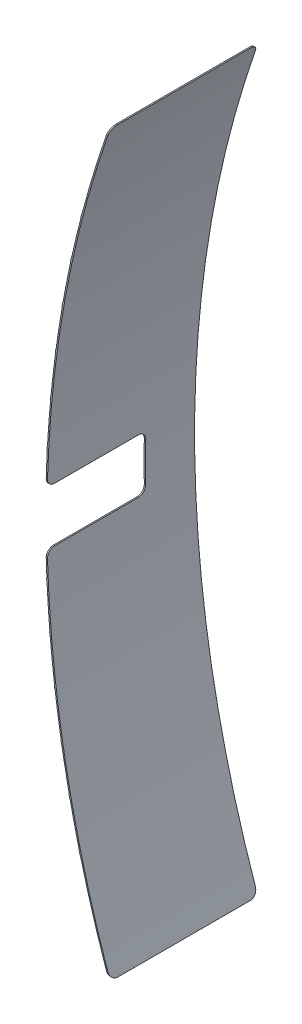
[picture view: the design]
ISO-10303-21;
HEADER;
FILE_DESCRIPTION(('STEP AP214'),'2;1');
FILE_NAME('part.step','',(''),(''),'','','');
FILE_SCHEMA(('AUTOMOTIVE_DESIGN { 1 0 10303 214 1 1 1 1 }'));
ENDSEC;
DATA;
#1=APPLICATION_CONTEXT('core data for automotive mechanical design processes');
#2=APPLICATION_PROTOCOL_DEFINITION('international standard','automotive_design',2000,#1);
#3=PRODUCT_CONTEXT('',#1,'mechanical');
#4=PRODUCT('Part','Part','',(#3));
#5=PRODUCT_RELATED_PRODUCT_CATEGORY('part','',(#4));
#6=PRODUCT_DEFINITION_FORMATION('','',#4);
#7=PRODUCT_DEFINITION_CONTEXT('part definition',#1,'design');
#8=PRODUCT_DEFINITION('design','',#6,#7);
#9=PRODUCT_DEFINITION_SHAPE('','',#8);
#10=(LENGTH_UNIT() NAMED_UNIT(*) SI_UNIT(.MILLI.,.METRE.));
#11=(NAMED_UNIT(*) PLANE_ANGLE_UNIT() SI_UNIT($,.RADIAN.));
#12=(NAMED_UNIT(*) SI_UNIT($,.STERADIAN.) SOLID_ANGLE_UNIT());
#13=UNCERTAINTY_MEASURE_WITH_UNIT(LENGTH_MEASURE(1.E-05),#10,'distance_accuracy_value','');
#14=(GEOMETRIC_REPRESENTATION_CONTEXT(3) GLOBAL_UNCERTAINTY_ASSIGNED_CONTEXT((#13)) GLOBAL_UNIT_ASSIGNED_CONTEXT((#10,
#11,#12)) REPRESENTATION_CONTEXT('',''));
#15=CARTESIAN_POINT('',(0.,0.,0.));
#16=DIRECTION('',(0.,0.,1.));
#17=DIRECTION('',(1.,0.,0.));
#18=AXIS2_PLACEMENT_3D('',#15,#16,#17);
#19=CARTESIAN_POINT('',(0.,0.,6.));
#20=DIRECTION('',(0.,0.,-1.));
#21=DIRECTION('',(-1.,0.,0.));
#22=AXIS2_PLACEMENT_3D('',#19,#20,#21);
#23=CYLINDRICAL_SURFACE('',#22,45.05);
#24=DIRECTION('',(0.,0.,1.));
#25=VECTOR('',#24,1.);
#26=CARTESIAN_POINT('',(-42.6888704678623,14.3931524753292,3.45));
#27=LINE('',#26,#25);
#28=CARTESIAN_POINT('',(-42.6888704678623,14.3931524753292,3.45));
#29=VERTEX_POINT('',#28);
#30=CARTESIAN_POINT('',(-42.6888704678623,14.3931524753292,3.65));
#31=VERTEX_POINT('',#30);
#32=EDGE_CURVE('E1607',#29,#31,#27,.T.);
#33=ORIENTED_EDGE('',*,*,#32,.T.);
#34=CARTESIAN_POINT('',(0.,0.,3.65));
#35=DIRECTION('',(0.,0.,-1.));
#36=DIRECTION('',(-0.947588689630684,0.319492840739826,0.));
#37=AXIS2_PLACEMENT_3D('',#34,#35,#36);
#38=CIRCLE('',#37,45.05);
#39=CARTESIAN_POINT('',(-43.0423392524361,13.2988545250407,3.65));
#40=VERTEX_POINT('',#39);
#41=EDGE_CURVE('E2961',#40,#31,#38,.T.);
#42=ORIENTED_EDGE('',*,*,#41,.F.);
#43=DIRECTION('',(0.,0.,1.));
#44=VECTOR('',#43,1.);
#45=CARTESIAN_POINT('',(-43.0423392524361,13.2988545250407,3.65));
#46=LINE('',#45,#44);
#47=CARTESIAN_POINT('',(-43.0423392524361,13.2988545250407,4.8));
#48=VERTEX_POINT('',#47);
#49=EDGE_CURVE('E3004',#40,#48,#46,.T.);
#50=ORIENTED_EDGE('',*,*,#49,.T.);
#51=CARTESIAN_POINT('',(0.,0.,4.8));
#52=DIRECTION('',(0.,0.,-1.));
#53=DIRECTION('',(-0.955434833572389,0.295202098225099,0.));
#54=AXIS2_PLACEMENT_3D('',#51,#52,#53);
#55=CIRCLE('',#54,45.05);
#56=CARTESIAN_POINT('',(-43.1009553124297,13.1076371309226,4.8));
#57=VERTEX_POINT('',#56);
#58=EDGE_CURVE('E2965',#57,#48,#55,.T.);
#59=ORIENTED_EDGE('',*,*,#58,.F.);
#60=DIRECTION('',(0.,0.,-1.));
#61=VECTOR('',#60,1.);
#62=CARTESIAN_POINT('',(-43.1009553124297,13.1076371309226,4.8));
#63=LINE('',#62,#61);
#64=CARTESIAN_POINT('',(-43.1009553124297,13.1076371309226,3.65));
#65=VERTEX_POINT('',#64);
#66=EDGE_CURVE('E2999',#57,#65,#63,.T.);
#67=ORIENTED_EDGE('',*,*,#66,.T.);
#68=CARTESIAN_POINT('',(0.,0.,3.65));
#69=DIRECTION('',(0.,0.,-1.));
#70=DIRECTION('',(-0.956735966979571,0.290957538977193,0.));
#71=AXIS2_PLACEMENT_3D('',#68,#69,#70);
#72=CIRCLE('',#71,45.05);
#73=CARTESIAN_POINT('',(-43.4214778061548,12.003239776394,3.65));
#74=VERTEX_POINT('',#73);
#75=EDGE_CURVE('E2994',#74,#65,#72,.T.);
#76=ORIENTED_EDGE('',*,*,#75,.F.);
#77=DIRECTION('',(0.,0.,-1.));
#78=VECTOR('',#77,1.);
#79=CARTESIAN_POINT('',(-43.4214778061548,12.003239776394,3.65));
#80=LINE('',#79,#78);
#81=CARTESIAN_POINT('',(-43.4214778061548,12.003239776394,3.45));
#82=VERTEX_POINT('',#81);
#83=EDGE_CURVE('E3003',#74,#82,#80,.T.);
#84=ORIENTED_EDGE('',*,*,#83,.T.);
#85=CARTESIAN_POINT('',(0.,0.,3.45));
#86=DIRECTION('',(0.,0.,-1.));
#87=DIRECTION('',(-0.956735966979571,0.290957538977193,0.));
#88=AXIS2_PLACEMENT_3D('',#85,#86,#87);
#89=CIRCLE('',#88,45.05);
#90=CARTESIAN_POINT('',(-43.1009553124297,13.1076371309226,3.45));
#91=VERTEX_POINT('',#90);
#92=EDGE_CURVE('E3011',#82,#91,#89,.T.);
#93=ORIENTED_EDGE('',*,*,#92,.T.);
#94=DIRECTION('',(0.,0.,-1.));
#95=VECTOR('',#94,1.);
#96=CARTESIAN_POINT('',(-43.1009553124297,13.1076371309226,3.45));
#97=LINE('',#96,#95);
#98=CARTESIAN_POINT('',(-43.1009553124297,13.1076371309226,2.3));
#99=VERTEX_POINT('',#98);
#100=EDGE_CURVE('E3015',#91,#99,#97,.T.);
#101=ORIENTED_EDGE('',*,*,#100,.T.);
#102=CARTESIAN_POINT('',(0.,0.,2.3));
#103=DIRECTION('',(0.,0.,-1.));
#104=DIRECTION('',(-0.955434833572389,0.295202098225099,0.));
#105=AXIS2_PLACEMENT_3D('',#102,#103,#104);
#106=CIRCLE('',#105,45.05);
#107=CARTESIAN_POINT('',(-43.0423392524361,13.2988545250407,2.3));
#108=VERTEX_POINT('',#107);
#109=EDGE_CURVE('E3019',#99,#108,#106,.T.);
#110=ORIENTED_EDGE('',*,*,#109,.T.);
#111=DIRECTION('',(0.,0.,1.));
#112=VECTOR('',#111,1.);
#113=CARTESIAN_POINT('',(-43.0423392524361,13.2988545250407,2.3));
#114=LINE('',#113,#112);
#115=CARTESIAN_POINT('',(-43.0423392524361,13.2988545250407,3.45));
#116=VERTEX_POINT('',#115);
#117=EDGE_CURVE('E3023',#108,#116,#114,.T.);
#118=ORIENTED_EDGE('',*,*,#117,.T.);
#119=CARTESIAN_POINT('',(0.,0.,3.45));
#120=DIRECTION('',(0.,0.,-1.));
#121=DIRECTION('',(-0.947588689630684,0.319492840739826,0.));
#122=AXIS2_PLACEMENT_3D('',#119,#120,#121);
#123=CIRCLE('',#122,45.05);
#124=EDGE_CURVE('E803',#116,#29,#123,.T.);
#125=ORIENTED_EDGE('',*,*,#124,.T.);
#126=EDGE_LOOP('',(#33,#42,#50,#59,#67,#76,#84,#93,#101,#110,#118,#125));
#127=FACE_BOUND('',#126,.T.);
#128=CARTESIAN_POINT('',(0.,0.,6.));
#129=DIRECTION('',(0.,0.,1.));
#130=DIRECTION('',(1.,0.,0.));
#131=AXIS2_PLACEMENT_3D('',#128,#129,#130);
#132=CIRCLE('',#131,45.05);
#133=CARTESIAN_POINT('',(-44.9868555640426,2.38439226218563,6.));
#134=VERTEX_POINT('',#133);
#135=CARTESIAN_POINT('',(-45.0282411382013,1.4,6.));
#136=VERTEX_POINT('',#135);
#137=EDGE_CURVE('E835',#134,#136,#132,.T.);
#138=ORIENTED_EDGE('',*,*,#137,.F.);
#139=DIRECTION('',(0.,0.,-1.));
#140=VECTOR('',#139,1.);
#141=CARTESIAN_POINT('',(-44.9868555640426,2.38439226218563,6.));
#142=LINE('',#141,#140);
#143=CARTESIAN_POINT('',(-44.9868555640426,2.38439226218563,2.));
#144=VERTEX_POINT('',#143);
#145=EDGE_CURVE('E798',#134,#144,#142,.T.);
#146=ORIENTED_EDGE('',*,*,#145,.T.);
#147=CARTESIAN_POINT('',(0.,0.,2.));
#148=DIRECTION('',(0.,0.,-1.));
#149=DIRECTION('',(-0.998353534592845,0.0573604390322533,0.));
#150=AXIS2_PLACEMENT_3D('',#147,#148,#149);
#151=CIRCLE('',#150,45.05);
#152=CARTESIAN_POINT('',(-44.9758267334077,2.58408777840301,2.));
#153=VERTEX_POINT('',#152);
#154=EDGE_CURVE('E802',#144,#153,#151,.T.);
#155=ORIENTED_EDGE('',*,*,#154,.T.);
#156=DIRECTION('',(0.,0.,1.));
#157=VECTOR('',#156,1.);
#158=CARTESIAN_POINT('',(-44.9758267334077,2.58408777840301,2.));
#159=LINE('',#158,#157);
#160=CARTESIAN_POINT('',(-44.9758267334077,2.58408777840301,6.));
#161=VERTEX_POINT('',#160);
#162=EDGE_CURVE('E807',#153,#161,#159,.T.);
#163=ORIENTED_EDGE('',*,*,#162,.T.);
#164=CARTESIAN_POINT('',(-44.8557062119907,4.1794880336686,6.));
#165=VERTEX_POINT('',#164);
#166=EDGE_CURVE('E829',#165,#161,#132,.T.);
#167=ORIENTED_EDGE('',*,*,#166,.F.);
#168=DIRECTION('',(0.,0.,-1.));
#169=VECTOR('',#168,1.);
#170=CARTESIAN_POINT('',(-44.8557062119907,4.1794880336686,5.99999999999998));
#171=LINE('',#170,#169);
#172=CARTESIAN_POINT('',(-44.8557062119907,4.1794880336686,1.99999999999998));
#173=VERTEX_POINT('',#172);
#174=EDGE_CURVE('E810',#165,#173,#171,.T.);
#175=ORIENTED_EDGE('',*,*,#174,.T.);
#176=CARTESIAN_POINT('',(0.,0.,1.99999999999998));
#177=DIRECTION('',(0.,0.,-1.));
#178=DIRECTION('',(-0.995265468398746,0.0971938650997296,0.));
#179=AXIS2_PLACEMENT_3D('',#176,#177,#178);
#180=CIRCLE('',#179,45.05);
#181=CARTESIAN_POINT('',(-44.8367093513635,4.37858362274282,1.99999999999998));
#182=VERTEX_POINT('',#181);
#183=EDGE_CURVE('E840',#173,#182,#180,.T.);
#184=ORIENTED_EDGE('',*,*,#183,.T.);
#185=DIRECTION('',(0.,0.,1.));
#186=VECTOR('',#185,1.);
#187=CARTESIAN_POINT('',(-44.8367093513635,4.37858362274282,1.99999999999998));
#188=LINE('',#187,#186);
#189=CARTESIAN_POINT('',(-44.8367093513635,4.37858362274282,6.));
#190=VERTEX_POINT('',#189);
#191=EDGE_CURVE('E844',#182,#190,#188,.T.);
#192=ORIENTED_EDGE('',*,*,#191,.T.);
#193=CARTESIAN_POINT('',(-44.6529564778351,5.96791234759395,6.));
#194=VERTEX_POINT('',#193);
#195=EDGE_CURVE('E869',#194,#190,#132,.T.);
#196=ORIENTED_EDGE('',*,*,#195,.F.);
#197=DIRECTION('',(0.,0.,-1.));
#198=VECTOR('',#197,1.);
#199=CARTESIAN_POINT('',(-44.6529564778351,5.96791234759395,5.99999999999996));
#200=LINE('',#199,#198);
#201=CARTESIAN_POINT('',(-44.6529564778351,5.96791234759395,1.99999999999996));
#202=VERTEX_POINT('',#201);
#203=EDGE_CURVE('E848',#194,#202,#200,.T.);
#204=ORIENTED_EDGE('',*,*,#203,.T.);
#205=CARTESIAN_POINT('',(0.,0.,1.99999999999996));
#206=DIRECTION('',(0.,0.,-1.));
#207=DIRECTION('',(-0.990588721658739,0.136872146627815,0.));
#208=AXIS2_PLACEMENT_3D('',#205,#206,#207);
#209=CIRCLE('',#208,45.05);
#210=CARTESIAN_POINT('',(-44.6260219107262,6.16609020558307,1.99999999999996));
#211=VERTEX_POINT('',#210);
#212=EDGE_CURVE('E1213',#202,#211,#209,.T.);
#213=ORIENTED_EDGE('',*,*,#212,.T.);
#214=DIRECTION('',(0.,0.,1.));
#215=VECTOR('',#214,1.);
#216=CARTESIAN_POINT('',(-44.6260219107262,6.16609020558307,1.99999999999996));
#217=LINE('',#216,#215);
#218=CARTESIAN_POINT('',(-44.6260219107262,6.16609020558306,6.));
#219=VERTEX_POINT('',#218);
#220=EDGE_CURVE('E1174',#211,#219,#217,.T.);
#221=ORIENTED_EDGE('',*,*,#220,.T.);
#222=CARTESIAN_POINT('',(-44.3789299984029,7.74681045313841,6.));
#223=VERTEX_POINT('',#222);
#224=EDGE_CURVE('E1207',#223,#219,#132,.T.);
#225=ORIENTED_EDGE('',*,*,#224,.F.);
#226=DIRECTION('',(0.,0.,-1.));
#227=VECTOR('',#226,1.);
#228=CARTESIAN_POINT('',(-44.3789299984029,7.74681045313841,5.99999999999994));
#229=LINE('',#228,#227);
#230=CARTESIAN_POINT('',(-44.3789299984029,7.74681045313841,1.99999999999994));
#231=VERTEX_POINT('',#230);
#232=EDGE_CURVE('E1169',#223,#231,#229,.T.);
#233=ORIENTED_EDGE('',*,*,#232,.T.);
#234=CARTESIAN_POINT('',(0.,0.,1.99999999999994));
#235=DIRECTION('',(0.,0.,-1.));
#236=DIRECTION('',(-0.984330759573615,0.176331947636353,0.));
#237=AXIS2_PLACEMENT_3D('',#234,#235,#236);
#238=CIRCLE('',#237,45.05);
#239=CARTESIAN_POINT('',(-44.3441007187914,7.9437542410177,1.99999999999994));
#240=VERTEX_POINT('',#239);
#241=EDGE_CURVE('E1173',#231,#240,#238,.T.);
#242=ORIENTED_EDGE('',*,*,#241,.T.);
#243=DIRECTION('',(0.,0.,1.));
#244=VECTOR('',#243,1.);
#245=CARTESIAN_POINT('',(-44.3441007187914,7.9437542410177,1.99999999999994));
#246=LINE('',#245,#244);
#247=CARTESIAN_POINT('',(-44.3441007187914,7.94375424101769,6.));
#248=VERTEX_POINT('',#247);
#249=EDGE_CURVE('E1133',#240,#248,#246,.T.);
#250=ORIENTED_EDGE('',*,*,#249,.T.);
#251=CARTESIAN_POINT('',(-44.0340641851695,9.51334280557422,6.));
#252=VERTEX_POINT('',#251);
#253=EDGE_CURVE('E1166',#252,#248,#132,.T.);
#254=ORIENTED_EDGE('',*,*,#253,.F.);
#255=DIRECTION('',(0.,0.,-1.));
#256=VECTOR('',#255,1.);
#257=CARTESIAN_POINT('',(-44.0340641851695,9.51334280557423,5.99999999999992));
#258=LINE('',#257,#256);
#259=CARTESIAN_POINT('',(-44.0340641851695,9.51334280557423,1.99999999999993));
#260=VERTEX_POINT('',#259);
#261=EDGE_CURVE('E1128',#252,#260,#258,.T.);
#262=ORIENTED_EDGE('',*,*,#261,.T.);
#263=CARTESIAN_POINT('',(0.,0.,1.99999999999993));
#264=DIRECTION('',(0.,0.,-1.));
#265=DIRECTION('',(-0.976501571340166,0.215510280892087,0.));
#266=AXIS2_PLACEMENT_3D('',#263,#264,#265);
#267=CIRCLE('',#266,45.05);
#268=CARTESIAN_POINT('',(-43.9913957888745,9.70873815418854,1.99999999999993));
#269=VERTEX_POINT('',#268);
#270=EDGE_CURVE('E1132',#260,#269,#267,.T.);
#271=ORIENTED_EDGE('',*,*,#270,.T.);
#272=DIRECTION('',(0.,0.,1.));
#273=VECTOR('',#272,1.);
#274=CARTESIAN_POINT('',(-43.9913957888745,9.70873815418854,1.99999999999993));
#275=LINE('',#274,#273);
#276=CARTESIAN_POINT('',(-43.9913957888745,9.70873815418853,6.));
#277=VERTEX_POINT('',#276);
#278=EDGE_CURVE('E1089',#269,#277,#275,.T.);
#279=ORIENTED_EDGE('',*,*,#278,.T.);
#280=CARTESIAN_POINT('',(-43.6189095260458,11.2646895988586,6.));
#281=VERTEX_POINT('',#280);
#282=EDGE_CURVE('E1125',#281,#277,#132,.T.);
#283=ORIENTED_EDGE('',*,*,#282,.F.);
#284=DIRECTION('',(0.,0.,-1.));
#285=VECTOR('',#284,1.);
#286=CARTESIAN_POINT('',(-43.6189095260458,11.2646895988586,5.99999999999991));
#287=LINE('',#286,#285);
#288=CARTESIAN_POINT('',(-43.6189095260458,11.2646895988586,1.99999999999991));
#289=VERTEX_POINT('',#288);
#290=EDGE_CURVE('E1084',#281,#289,#287,.T.);
#291=ORIENTED_EDGE('',*,*,#290,.T.);
#292=CARTESIAN_POINT('',(0.,0.,1.99999999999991));
#293=DIRECTION('',(0.,0.,-1.));
#294=DIRECTION('',(-0.967113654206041,0.254344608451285,0.));
#295=AXIS2_PLACEMENT_3D('',#292,#293,#294);
#296=CIRCLE('',#295,45.05);
#297=CARTESIAN_POINT('',(-43.5684701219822,11.4582246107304,1.99999999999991));
#298=VERTEX_POINT('',#297);
#299=EDGE_CURVE('E1088',#289,#298,#296,.T.);
#300=ORIENTED_EDGE('',*,*,#299,.T.);
#301=DIRECTION('',(0.,0.,1.));
#302=VECTOR('',#301,1.);
#303=CARTESIAN_POINT('',(-43.5684701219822,11.4582246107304,1.99999999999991));
#304=LINE('',#303,#302);
#305=CARTESIAN_POINT('',(-43.5684701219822,11.4582246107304,6.));
#306=VERTEX_POINT('',#305);
#307=EDGE_CURVE('E1093',#298,#306,#304,.T.);
#308=ORIENTED_EDGE('',*,*,#307,.T.);
#309=CARTESIAN_POINT('',(-42.5841813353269,14.7,6.));
#310=VERTEX_POINT('',#309);
#311=EDGE_CURVE('E1118',#310,#306,#132,.T.);
#312=ORIENTED_EDGE('',*,*,#311,.F.);
#313=CARTESIAN_POINT('',(-42.5841813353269,14.7,6.));
#314=CARTESIAN_POINT('',(-42.5780912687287,14.7176435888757,6.00001047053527));
#315=CARTESIAN_POINT('',(-42.5719889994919,14.7352842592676,5.99844396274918));
#316=CARTESIAN_POINT('',(-42.5599276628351,14.7700841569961,5.99223149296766));
#317=CARTESIAN_POINT('',(-42.5539687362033,14.7872429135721,5.98758262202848));
#318=CARTESIAN_POINT('',(-42.5423680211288,14.8205849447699,5.97527400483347));
#319=CARTESIAN_POINT('',(-42.5367265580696,14.8367672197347,5.96761123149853));
#320=CARTESIAN_POINT('',(-42.5259502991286,14.8676264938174,5.94944240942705));
#321=CARTESIAN_POINT('',(-42.5208151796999,14.8823044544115,5.93893819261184));
#322=CARTESIAN_POINT('',(-42.511362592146,14.9092840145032,5.91565912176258));
#323=CARTESIAN_POINT('',(-42.5070264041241,14.9216402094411,5.90295528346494));
#324=CARTESIAN_POINT('',(-42.4991634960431,14.9440203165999,5.87540998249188));
#325=CARTESIAN_POINT('',(-42.4956367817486,14.9540442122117,5.86056850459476));
#326=CARTESIAN_POINT('',(-42.4897118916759,14.9708703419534,5.83006126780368));
#327=CARTESIAN_POINT('',(-42.4872619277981,14.9778205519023,5.81448703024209));
#328=CARTESIAN_POINT('',(-42.4833208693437,14.9889954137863,5.78228609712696));
#329=CARTESIAN_POINT('',(-42.4818283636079,14.99322407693,5.76566099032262));
#330=CARTESIAN_POINT('',(-42.4803770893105,14.9973352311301,5.7407286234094));
#331=CARTESIAN_POINT('',(-42.4800244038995,14.9983341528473,5.73261314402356));
#332=CARTESIAN_POINT('',(-42.4795541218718,14.9996660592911,5.71633322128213));
#333=CARTESIAN_POINT('',(-42.4794361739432,15.0000000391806,5.70816886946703));
#334=CARTESIAN_POINT('',(-42.4794362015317,15.,5.70000000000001));
#335=B_SPLINE_CURVE_WITH_KNOTS('',3,(#313,#314,#315,#316,#317,#318,#319,#320,#321,#322,#323,
#324,#325,#326,#327,#328,#329,#330,#331,#332,#333,#334),.UNSPECIFIED.,.F.,.F.,(4,2,2,2,2,2,2,2,
2,2,4),(0.,0.0559326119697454,0.111918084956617,0.167959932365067,0.223965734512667,
0.278419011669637,0.332872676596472,0.384302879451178,0.435657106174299,0.460183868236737,
0.484673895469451),.UNSPECIFIED.);
#336=CARTESIAN_POINT('',(-42.4794362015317,15.,5.7));
#337=VERTEX_POINT('',#336);
#338=EDGE_CURVE('E1097',#310,#337,#335,.T.);
#339=ORIENTED_EDGE('',*,*,#338,.T.);
#340=DIRECTION('',(0.,0.,-1.));
#341=VECTOR('',#340,1.);
#342=CARTESIAN_POINT('',(-42.4794362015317,15.,6.));
#343=LINE('',#342,#341);
#344=CARTESIAN_POINT('',(-42.4794362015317,15.,0.3));
#345=VERTEX_POINT('',#344);
#346=EDGE_CURVE('E1366',#337,#345,#343,.T.);
#347=ORIENTED_EDGE('',*,*,#346,.T.);
#348=CARTESIAN_POINT('',(-42.4794362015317,15.,0.3));
#349=CARTESIAN_POINT('',(-42.4794298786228,15.000017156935,0.283811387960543));
#350=CARTESIAN_POINT('',(-42.4798984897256,14.9986908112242,0.267632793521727));
#351=CARTESIAN_POINT('',(-42.4817365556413,14.9934843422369,0.235782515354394));
#352=CARTESIAN_POINT('',(-42.4831038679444,14.9896102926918,0.220109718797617));
#353=CARTESIAN_POINT('',(-42.4866905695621,14.9794409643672,0.189678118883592));
#354=CARTESIAN_POINT('',(-42.4889098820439,14.9731459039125,0.174919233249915));
#355=CARTESIAN_POINT('',(-42.4941171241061,14.9583612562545,0.146692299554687));
#356=CARTESIAN_POINT('',(-42.4971052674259,14.9498710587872,0.133224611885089));
#357=CARTESIAN_POINT('',(-42.5038299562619,14.930741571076,0.107593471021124));
#358=CARTESIAN_POINT('',(-42.5075828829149,14.9200551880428,0.0954695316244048));
#359=CARTESIAN_POINT('',(-42.5156689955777,14.8969976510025,0.0731757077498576));
#360=CARTESIAN_POINT('',(-42.5200023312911,14.8846260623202,0.0630063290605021));
#361=CARTESIAN_POINT('',(-42.5293703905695,14.8578385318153,0.044328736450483));
#362=CARTESIAN_POINT('',(-42.5344303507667,14.8433482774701,0.0359398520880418));
#363=CARTESIAN_POINT('',(-42.5449099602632,14.8132842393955,0.0217136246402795));
#364=CARTESIAN_POINT('',(-42.550329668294,14.7977102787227,0.0158766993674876));
#365=CARTESIAN_POINT('',(-42.5604846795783,14.7684746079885,0.0075907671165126));
#366=CARTESIAN_POINT('',(-42.5651884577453,14.7549123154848,0.00474587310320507));
#367=CARTESIAN_POINT('',(-42.5746573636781,14.7275681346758,0.0009503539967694));
#368=CARTESIAN_POINT('',(-42.5794223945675,14.7137865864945,-2.9621701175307E-06));
#369=CARTESIAN_POINT('',(-42.5841813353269,14.7,0.));
#370=B_SPLINE_CURVE_WITH_KNOTS('',3,(#348,#349,#350,#351,#352,#353,#354,#355,#356,#357,#358,
#359,#360,#361,#362,#363,#364,#365,#366,#367,#368,#369),.UNSPECIFIED.,.F.,.F.,(4,2,2,2,2,2,2,2,
2,2,4),(0.,0.0484894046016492,0.0968636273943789,0.145233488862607,0.193616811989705,
0.243172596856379,0.292741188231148,0.344985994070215,0.397239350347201,0.441019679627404,
0.484737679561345),.UNSPECIFIED.);
#371=CARTESIAN_POINT('',(-42.5841813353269,14.7,0.));
#372=VERTEX_POINT('',#371);
#373=EDGE_CURVE('E1369',#345,#372,#370,.T.);
#374=ORIENTED_EDGE('',*,*,#373,.T.);
#375=CARTESIAN_POINT('',(0.,0.,0.));
#376=DIRECTION('',(0.,0.,1.));
#377=DIRECTION('',(1.,0.,0.));
#378=AXIS2_PLACEMENT_3D('',#375,#376,#377);
#379=CIRCLE('',#378,45.05);
#380=CARTESIAN_POINT('',(-44.9404229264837,3.14020495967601,0.));
#381=VERTEX_POINT('',#380);
#382=EDGE_CURVE('E1351',#372,#381,#379,.T.);
#383=ORIENTED_EDGE('',*,*,#382,.T.);
#384=CARTESIAN_POINT('',(-45.049773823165,0.142753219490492,2.));
#385=CARTESIAN_POINT('',(-45.0466050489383,1.14274861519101,1.33333305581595));
#386=CARTESIAN_POINT('',(-45.010127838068,2.14263688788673,0.666666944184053));
#387=CARTESIAN_POINT('',(-44.9404229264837,3.14020495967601,0.));
#388=B_SPLINE_CURVE_WITH_KNOTS('',3,(#384,#385,#386,#387),.UNSPECIFIED.,.F.,.F.,(4,4),(0.,1.),.UNSPECIFIED.);
#389=CARTESIAN_POINT('',(-45.049773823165,0.142753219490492,2.));
#390=VERTEX_POINT('',#389);
#391=EDGE_CURVE('E3118',#381,#390,#388,.F.);
#392=ORIENTED_EDGE('',*,*,#391,.T.);
#393=CARTESIAN_POINT('',(0.,0.,2.));
#394=DIRECTION('',(0.,0.,-1.));
#395=DIRECTION('',(-1.,0.,0.));
#396=AXIS2_PLACEMENT_3D('',#393,#394,#395);
#397=CIRCLE('',#396,45.05);
#398=CARTESIAN_POINT('',(-45.0428962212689,0.8,2.));
#399=VERTEX_POINT('',#398);
#400=EDGE_CURVE('E1353',#390,#399,#397,.T.);
#401=ORIENTED_EDGE('',*,*,#400,.T.);
#402=CARTESIAN_POINT('',(-45.0428962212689,0.8,2.));
#403=CARTESIAN_POINT('',(-45.0425967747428,0.816880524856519,1.99998568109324));
#404=CARTESIAN_POINT('',(-45.0422871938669,0.833756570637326,2.00142390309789));
#405=CARTESIAN_POINT('',(-45.041659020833,0.86701807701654,2.00709957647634));
#406=CARTESIAN_POINT('',(-45.0413404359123,0.883403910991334,2.01133483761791));
#407=CARTESIAN_POINT('',(-45.0407048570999,0.91523886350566,2.02250171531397));
#408=CARTESIAN_POINT('',(-45.0403878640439,0.93068752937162,2.0294346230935));
#409=CARTESIAN_POINT('',(-45.0397683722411,0.960199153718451,2.04579405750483));
#410=CARTESIAN_POINT('',(-45.0394658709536,0.974262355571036,2.05522014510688));
#411=CARTESIAN_POINT('',(-45.0388883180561,1.00060639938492,2.07629995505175));
#412=CARTESIAN_POINT('',(-45.0386132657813,1.01288728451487,2.08795362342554));
#413=CARTESIAN_POINT('',(-45.0381031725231,1.0353206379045,2.11316085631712));
#414=CARTESIAN_POINT('',(-45.0378681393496,1.0454726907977,2.12671479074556));
#415=CARTESIAN_POINT('',(-45.0374494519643,1.06335656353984,2.15533428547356));
#416=CARTESIAN_POINT('',(-45.0372657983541,1.0710883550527,2.17039986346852));
#417=CARTESIAN_POINT('',(-45.0369590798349,1.08390876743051,2.20161286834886));
#418=CARTESIAN_POINT('',(-45.0368359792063,1.08899894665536,2.21775965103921));
#419=CARTESIAN_POINT('',(-45.0366873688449,1.09512406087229,2.2450047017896));
#420=CARTESIAN_POINT('',(-45.0366428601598,1.09695143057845,2.25593128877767));
#421=CARTESIAN_POINT('',(-45.0365833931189,1.09938923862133,2.27790371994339));
#422=CARTESIAN_POINT('',(-45.0365683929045,1.10000140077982,2.28894937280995));
#423=CARTESIAN_POINT('',(-45.0365684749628,1.10000000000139,2.29999999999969));
#424=B_SPLINE_CURVE_WITH_KNOTS('',3,(#402,#403,#404,#405,#406,#407,#408,#409,#410,#411,#412,
#413,#414,#415,#416,#417,#418,#419,#420,#421,#422,#423),.UNSPECIFIED.,.F.,.F.,(4,2,2,2,2,2,2,2,
2,2,4),(0.,0.0505822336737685,0.101124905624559,0.151691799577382,0.202249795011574,
0.252806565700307,0.303373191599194,0.353940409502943,0.404477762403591,0.437650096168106,
0.4707753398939),.UNSPECIFIED.);
#425=CARTESIAN_POINT('',(-45.0365684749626,1.1,2.3));
#426=VERTEX_POINT('',#425);
#427=EDGE_CURVE('E1459',#399,#426,#424,.T.);
#428=ORIENTED_EDGE('',*,*,#427,.T.);
#429=DIRECTION('',(0.,0.,-1.));
#430=VECTOR('',#429,1.);
#431=CARTESIAN_POINT('',(-45.0365684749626,1.1,6.));
#432=LINE('',#431,#430);
#433=CARTESIAN_POINT('',(-45.0365684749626,1.1,5.7));
#434=VERTEX_POINT('',#433);
#435=EDGE_CURVE('E1466',#426,#434,#432,.F.);
#436=ORIENTED_EDGE('',*,*,#435,.T.);
#437=CARTESIAN_POINT('',(-45.0365684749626,1.1,5.7));
#438=CARTESIAN_POINT('',(-45.0365685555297,1.0999856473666,5.71687353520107));
#439=CARTESIAN_POINT('',(-45.0365337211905,1.1014227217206,5.73374276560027));
#440=CARTESIAN_POINT('',(-45.0363948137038,1.10709378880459,5.76699097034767));
#441=CARTESIAN_POINT('',(-45.0362907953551,1.11132556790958,5.78337032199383));
#442=CARTESIAN_POINT('',(-45.0360140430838,1.12248308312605,5.81519290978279));
#443=CARTESIAN_POINT('',(-45.0358412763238,1.12941010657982,5.83063569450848));
#444=CARTESIAN_POINT('',(-45.0354284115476,1.14575512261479,5.86013649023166));
#445=CARTESIAN_POINT('',(-45.0351883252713,1.15517268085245,5.87419474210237));
#446=CARTESIAN_POINT('',(-45.034643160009,1.17623380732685,5.90053198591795));
#447=CARTESIAN_POINT('',(-45.0343380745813,1.18787759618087,5.91281080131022));
#448=CARTESIAN_POINT('',(-45.0336667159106,1.2130624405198,5.93524181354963));
#449=CARTESIAN_POINT('',(-45.0333004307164,1.22660386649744,5.94539359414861));
#450=CARTESIAN_POINT('',(-45.0325123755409,1.25520264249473,5.96328400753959));
#451=CARTESIAN_POINT('',(-45.0320905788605,1.27026072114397,5.97102147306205));
#452=CARTESIAN_POINT('',(-45.0311997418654,1.30145788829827,5.98385473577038));
#453=CARTESIAN_POINT('',(-45.0307307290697,1.31759634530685,5.98895206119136));
#454=CARTESIAN_POINT('',(-45.0299230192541,1.34486073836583,5.99509831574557));
#455=CARTESIAN_POINT('',(-45.0295945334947,1.35581581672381,5.99693536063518));
#456=CARTESIAN_POINT('',(-45.0289258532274,1.37784578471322,5.99938604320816));
#457=CARTESIAN_POINT('',(-45.0285856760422,1.38892048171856,6.00000141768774));
#458=CARTESIAN_POINT('',(-45.0282411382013,1.39999999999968,6.00000000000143));
#459=B_SPLINE_CURVE_WITH_KNOTS('',3,(#437,#438,#439,#440,#441,#442,#443,#444,#445,#446,#447,
#448,#449,#450,#451,#452,#453,#454,#455,#456,#457,#458),.UNSPECIFIED.,.F.,.F.,(4,2,2,2,2,2,2,2,
2,2,4),(0.,0.0505533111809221,0.1010666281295,0.151604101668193,0.202132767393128,
0.252666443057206,0.303209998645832,0.353777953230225,0.404316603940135,0.437591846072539,
0.47081974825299),.UNSPECIFIED.);
#460=EDGE_CURVE('E1444',#434,#136,#459,.T.);
#461=ORIENTED_EDGE('',*,*,#460,.T.);
#462=EDGE_LOOP('',(#138,#146,#155,#163,#167,#175,#184,#192,#196,#204,#213,#221,#225,#233,#242,
#250,#254,#262,#271,#279,#283,#291,#300,#308,#312,#339,#347,#374,#383,#392,#401,#428,#436,#461));
#463=FACE_BOUND('',#462,.T.);
#464=ADVANCED_FACE('F690',(#127,#463),#23,.T.);
#465=CARTESIAN_POINT('',(0.,0.,6.));
#466=DIRECTION('',(0.,0.,1.));
#467=DIRECTION('',(1.,0.,0.));
#468=AXIS2_PLACEMENT_3D('',#465,#466,#467);
#469=PLANE('',#468);
#470=ORIENTED_EDGE('',*,*,#311,.T.);
#471=DIRECTION('',(0.967113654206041,-0.254344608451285,0.));
#472=VECTOR('',#471,1.);
#473=CARTESIAN_POINT('',(-43.5684701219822,11.4582246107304,6.));
#474=LINE('',#473,#472);
#475=CARTESIAN_POINT('',(-43.5781412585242,11.4607680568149,6.));
#476=VERTEX_POINT('',#475);
#477=EDGE_CURVE('E863',#476,#306,#474,.T.);
#478=ORIENTED_EDGE('',*,*,#477,.F.);
#479=CARTESIAN_POINT('',(0.,0.,6.));
#480=DIRECTION('',(0.,0.,-1.));
#481=DIRECTION('',(-1.,0.,0.));
#482=AXIS2_PLACEMENT_3D('',#479,#480,#481);
#483=CIRCLE('',#482,45.06);
#484=CARTESIAN_POINT('',(-43.6285918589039,11.2671900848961,6.));
#485=VERTEX_POINT('',#484);
#486=EDGE_CURVE('E1113',#476,#485,#483,.F.);
#487=ORIENTED_EDGE('',*,*,#486,.T.);
#488=DIRECTION('',(0.968233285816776,-0.250048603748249,0.));
#489=VECTOR('',#488,1.);
#490=CARTESIAN_POINT('',(-43.6189095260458,11.2646895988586,6.));
#491=LINE('',#490,#489);
#492=EDGE_CURVE('E1117',#485,#281,#491,.T.);
#493=ORIENTED_EDGE('',*,*,#492,.T.);
#494=ORIENTED_EDGE('',*,*,#282,.T.);
#495=DIRECTION('',(0.976501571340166,-0.215510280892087,0.));
#496=VECTOR('',#495,1.);
#497=CARTESIAN_POINT('',(-43.9913957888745,9.70873815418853,6.));
#498=LINE('',#497,#496);
#499=CARTESIAN_POINT('',(-44.0011608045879,9.71089325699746,6.));
#500=VERTEX_POINT('',#499);
#501=EDGE_CURVE('E1112',#500,#277,#498,.T.);
#502=ORIENTED_EDGE('',*,*,#501,.F.);
#503=CARTESIAN_POINT('',(0.,0.,6.));
#504=DIRECTION('',(0.,0.,-1.));
#505=DIRECTION('',(-1.,0.,0.));
#506=AXIS2_PLACEMENT_3D('',#503,#504,#505);
#507=CIRCLE('',#506,45.06);
#508=CARTESIAN_POINT('',(-44.0438386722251,9.51545453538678,6.));
#509=VERTEX_POINT('',#508);
#510=EDGE_CURVE('E1155',#500,#509,#507,.F.);
#511=ORIENTED_EDGE('',*,*,#510,.T.);
#512=DIRECTION('',(0.977448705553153,-0.21117298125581,0.));
#513=VECTOR('',#512,1.);
#514=CARTESIAN_POINT('',(-44.0340641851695,9.51334280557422,6.));
#515=LINE('',#514,#513);
#516=EDGE_CURVE('E1159',#509,#252,#515,.T.);
#517=ORIENTED_EDGE('',*,*,#516,.T.);
#518=ORIENTED_EDGE('',*,*,#253,.T.);
#519=DIRECTION('',(0.984330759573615,-0.176331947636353,0.));
#520=VECTOR('',#519,1.);
#521=CARTESIAN_POINT('',(-44.3441007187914,7.94375424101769,6.));
#522=LINE('',#521,#520);
#523=CARTESIAN_POINT('',(-44.3539440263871,7.94551756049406,6.));
#524=VERTEX_POINT('',#523);
#525=EDGE_CURVE('E1154',#524,#248,#522,.T.);
#526=ORIENTED_EDGE('',*,*,#525,.F.);
#527=CARTESIAN_POINT('',(0.,0.,6.));
#528=DIRECTION('',(0.,0.,-1.));
#529=DIRECTION('',(-1.,0.,0.));
#530=AXIS2_PLACEMENT_3D('',#527,#528,#529);
#531=CIRCLE('',#530,45.06);
#532=CARTESIAN_POINT('',(-44.3887810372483,7.74853005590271,6.));
#533=VERTEX_POINT('',#532);
#534=EDGE_CURVE('E1196',#524,#533,#531,.F.);
#535=ORIENTED_EDGE('',*,*,#534,.T.);
#536=DIRECTION('',(0.985103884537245,-0.171960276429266,0.));
#537=VECTOR('',#536,1.);
#538=CARTESIAN_POINT('',(-44.3789299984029,7.74681045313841,6.));
#539=LINE('',#538,#537);
#540=EDGE_CURVE('E1200',#533,#223,#539,.T.);
#541=ORIENTED_EDGE('',*,*,#540,.T.);
#542=ORIENTED_EDGE('',*,*,#224,.T.);
#543=DIRECTION('',(0.990588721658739,-0.136872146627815,0.));
#544=VECTOR('',#543,1.);
#545=CARTESIAN_POINT('',(-44.6260219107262,6.16609020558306,6.));
#546=LINE('',#545,#544);
#547=CARTESIAN_POINT('',(-44.6359277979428,6.16745892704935,6.));
#548=VERTEX_POINT('',#547);
#549=EDGE_CURVE('E1195',#548,#219,#546,.T.);
#550=ORIENTED_EDGE('',*,*,#549,.F.);
#551=CARTESIAN_POINT('',(0.,0.,6.));
#552=DIRECTION('',(0.,0.,-1.));
#553=DIRECTION('',(-1.,0.,0.));
#554=AXIS2_PLACEMENT_3D('',#551,#552,#553);
#555=CIRCLE('',#554,45.06);
#556=CARTESIAN_POINT('',(-44.6628683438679,5.96923707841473,6.));
#557=VERTEX_POINT('',#556);
#558=EDGE_CURVE('E1233',#548,#557,#555,.F.);
#559=ORIENTED_EDGE('',*,*,#558,.T.);
#560=DIRECTION('',(0.991186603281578,-0.132473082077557,0.));
#561=VECTOR('',#560,1.);
#562=CARTESIAN_POINT('',(-44.6529564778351,5.96791234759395,6.));
#563=LINE('',#562,#561);
#564=EDGE_CURVE('E1237',#557,#194,#563,.T.);
#565=ORIENTED_EDGE('',*,*,#564,.T.);
#566=ORIENTED_EDGE('',*,*,#195,.T.);
#567=DIRECTION('',(0.995265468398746,-0.0971938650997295,0.));
#568=VECTOR('',#567,1.);
#569=CARTESIAN_POINT('',(-44.8367093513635,4.37858362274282,6.));
#570=LINE('',#569,#568);
#571=CARTESIAN_POINT('',(-44.8466620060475,4.37955556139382,6.));
#572=VERTEX_POINT('',#571);
#573=EDGE_CURVE('E823',#572,#190,#570,.T.);
#574=ORIENTED_EDGE('',*,*,#573,.F.);
#575=CARTESIAN_POINT('',(0.,0.,6.));
#576=DIRECTION('',(0.,0.,-1.));
#577=DIRECTION('',(-1.,0.,0.));
#578=AXIS2_PLACEMENT_3D('',#575,#576,#577);
#579=CIRCLE('',#578,45.06);
#580=CARTESIAN_POINT('',(-44.8656630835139,4.18041577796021,6.));
#581=VERTEX_POINT('',#580);
#582=EDGE_CURVE('E864',#572,#581,#579,.F.);
#583=ORIENTED_EDGE('',*,*,#582,.T.);
#584=DIRECTION('',(0.995687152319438,-0.0927744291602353,0.));
#585=VECTOR('',#584,1.);
#586=CARTESIAN_POINT('',(-44.8557062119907,4.1794880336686,6.));
#587=LINE('',#586,#585);
#588=EDGE_CURVE('E868',#581,#165,#587,.T.);
#589=ORIENTED_EDGE('',*,*,#588,.T.);
#590=ORIENTED_EDGE('',*,*,#166,.T.);
#591=DIRECTION('',(0.998353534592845,-0.0573604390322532,0.));
#592=VECTOR('',#591,1.);
#593=CARTESIAN_POINT('',(-44.9758267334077,2.58408777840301,6.));
#594=LINE('',#593,#592);
#595=CARTESIAN_POINT('',(-44.9858102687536,2.58466138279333,6.));
#596=VERTEX_POINT('',#595);
#597=EDGE_CURVE('E13',#596,#161,#594,.T.);
#598=ORIENTED_EDGE('',*,*,#597,.F.);
#599=CARTESIAN_POINT('',(0.,0.,6.));
#600=DIRECTION('',(0.,0.,-1.));
#601=DIRECTION('',(-1.,0.,0.));
#602=AXIS2_PLACEMENT_3D('',#599,#600,#601);
#603=CIRCLE('',#602,45.06);
#604=CARTESIAN_POINT('',(-44.9968415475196,2.38492153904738,6.));
#605=VERTEX_POINT('',#604);
#606=EDGE_CURVE('E824',#596,#605,#603,.F.);
#607=ORIENTED_EDGE('',*,*,#606,.T.);
#608=DIRECTION('',(0.998598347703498,-0.0529276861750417,0.));
#609=VECTOR('',#608,1.);
#610=CARTESIAN_POINT('',(-44.9868555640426,2.38439226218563,6.));
#611=LINE('',#610,#609);
#612=EDGE_CURVE('E828',#605,#134,#611,.T.);
#613=ORIENTED_EDGE('',*,*,#612,.T.);
#614=ORIENTED_EDGE('',*,*,#137,.T.);
#615=DIRECTION('',(-1.,0.,0.));
#616=VECTOR('',#615,1.);
#617=CARTESIAN_POINT('',(-44.9865535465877,1.4,6.));
#618=LINE('',#617,#616);
#619=CARTESIAN_POINT('',(-44.9782169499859,1.4,6.));
#620=VERTEX_POINT('',#619);
#621=EDGE_CURVE('E1578',#136,#620,#618,.F.);
#622=ORIENTED_EDGE('',*,*,#621,.T.);
#623=CARTESIAN_POINT('',(0.,0.,6.));
#624=DIRECTION('',(0.,0.,-1.));
#625=DIRECTION('',(1.,0.,0.));
#626=AXIS2_PLACEMENT_3D('',#623,#624,#625);
#627=CIRCLE('',#626,45.);
#628=CARTESIAN_POINT('',(-42.5312826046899,14.7,6.));
#629=VERTEX_POINT('',#628);
#630=EDGE_CURVE('E1620',#620,#629,#627,.T.);
#631=ORIENTED_EDGE('',*,*,#630,.T.);
#632=DIRECTION('',(-1.,0.,0.));
#633=VECTOR('',#632,1.);
#634=CARTESIAN_POINT('',(-42.4794362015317,14.7,6.));
#635=LINE('',#634,#633);
#636=EDGE_CURVE('E1529',#629,#310,#635,.T.);
#637=ORIENTED_EDGE('',*,*,#636,.T.);
#638=EDGE_LOOP('',(#470,#478,#487,#493,#494,#502,#511,#517,#518,#526,#535,#541,#542,#550,#559,
#565,#566,#574,#583,#589,#590,#598,#607,#613,#614,#622,#631,#637));
#639=FACE_BOUND('',#638,.T.);
#640=ADVANCED_FACE('F1593',(#639),#469,.T.);
#641=CARTESIAN_POINT('',(0.,0.,6.));
#642=DIRECTION('',(0.,0.,-1.));
#643=DIRECTION('',(-1.,0.,0.));
#644=AXIS2_PLACEMENT_3D('',#641,#642,#643);
#645=CYLINDRICAL_SURFACE('',#644,45.);
#646=ORIENTED_EDGE('',*,*,#630,.F.);
#647=CARTESIAN_POINT('',(-44.9782169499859,1.4,6.));
#648=CARTESIAN_POINT('',(-44.978742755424,1.3831190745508,6.0000143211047));
#649=CARTESIAN_POINT('',(-44.9792582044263,1.36624202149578,5.99857602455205));
#650=CARTESIAN_POINT('',(-44.9802561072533,1.33297727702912,5.99289946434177));
#651=CARTESIAN_POINT('',(-44.9807385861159,1.31658921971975,5.98866335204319));
#652=CARTESIAN_POINT('',(-44.981659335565,1.28474893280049,5.97749340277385));
#653=CARTESIAN_POINT('',(-44.9820975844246,1.26929716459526,5.97055824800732));
#654=CARTESIAN_POINT('',(-44.9829208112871,1.23977937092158,5.95419268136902));
#655=CARTESIAN_POINT('',(-44.9833057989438,1.22571309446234,5.94476272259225));
#656=CARTESIAN_POINT('',(-44.9840159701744,1.19936704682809,5.92367628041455));
#657=CARTESIAN_POINT('',(-44.9843411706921,1.18708676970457,5.91202042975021));
#658=CARTESIAN_POINT('',(-44.9849275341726,1.16465486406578,5.88680840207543));
#659=CARTESIAN_POINT('',(-44.9851886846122,1.15450365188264,5.8732518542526));
#660=CARTESIAN_POINT('',(-44.9856440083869,1.13662369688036,5.84462960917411));
#661=CARTESIAN_POINT('',(-44.985838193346,1.12889453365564,5.82956417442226));
#662=CARTESIAN_POINT('',(-44.9861579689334,1.11607909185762,5.79835187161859));
#663=CARTESIAN_POINT('',(-44.9862836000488,1.11099125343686,5.78220564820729));
#664=CARTESIAN_POINT('',(-44.9864342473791,1.10487083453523,5.75496673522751));
#665=CARTESIAN_POINT('',(-44.9864790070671,1.10304537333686,5.7440457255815));
#666=CARTESIAN_POINT('',(-44.9865386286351,1.10061012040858,5.72208467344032));
#667=CARTESIAN_POINT('',(-44.9865535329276,1.09999860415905,5.71104482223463));
#668=CARTESIAN_POINT('',(-44.9865535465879,1.0999999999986,5.70000000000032));
#669=B_SPLINE_CURVE_WITH_KNOTS('',3,(#647,#648,#649,#650,#651,#652,#653,#654,#655,#656,#657,
#658,#659,#660,#661,#662,#663,#664,#665,#666,#667,#668),.UNSPECIFIED.,.F.,.F.,(4,2,2,2,2,2,2,2,
2,2,4),(0.,0.0506002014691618,0.101161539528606,0.151747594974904,0.202324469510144,
0.252886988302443,0.303459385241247,0.354022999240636,0.404556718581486,0.437711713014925,
0.470819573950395),.UNSPECIFIED.);
#670=CARTESIAN_POINT('',(-44.9865535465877,1.1,5.7));
#671=VERTEX_POINT('',#670);
#672=EDGE_CURVE('E1521',#620,#671,#669,.T.);
#673=ORIENTED_EDGE('',*,*,#672,.T.);
#674=DIRECTION('',(0.,0.,-1.));
#675=VECTOR('',#674,1.);
#676=CARTESIAN_POINT('',(-44.9865535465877,1.1,6.));
#677=LINE('',#676,#675);
#678=CARTESIAN_POINT('',(-44.9865535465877,1.1,2.3));
#679=VERTEX_POINT('',#678);
#680=EDGE_CURVE('E1528',#671,#679,#677,.T.);
#681=ORIENTED_EDGE('',*,*,#680,.T.);
#682=CARTESIAN_POINT('',(-44.9865535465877,1.1,2.3));
#683=CARTESIAN_POINT('',(-44.9865529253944,1.1000143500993,2.28312587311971));
#684=CARTESIAN_POINT('',(-44.986588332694,1.09857717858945,2.2662560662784));
#685=CARTESIAN_POINT('',(-44.9867266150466,1.09290573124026,2.23300679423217));
#686=CARTESIAN_POINT('',(-44.9868294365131,1.0886736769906,2.21662695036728));
#687=CARTESIAN_POINT('',(-44.9870980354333,1.07751543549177,2.18480344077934));
#688=CARTESIAN_POINT('',(-44.9872638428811,1.07058796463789,2.16936022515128));
#689=CARTESIAN_POINT('',(-44.9876498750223,1.05424178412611,2.13985852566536));
#690=CARTESIAN_POINT('',(-44.987870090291,1.04482350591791,2.12579980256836));
#691=CARTESIAN_POINT('',(-44.9883543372,1.02376001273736,2.09946097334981));
#692=CARTESIAN_POINT('',(-44.9886183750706,1.01211448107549,2.08718112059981));
#693=CARTESIAN_POINT('',(-44.9891779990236,0.986925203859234,2.0647482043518));
#694=CARTESIAN_POINT('',(-44.9894735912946,0.973381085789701,2.0545955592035));
#695=CARTESIAN_POINT('',(-44.990083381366,0.944776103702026,2.03670413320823));
#696=CARTESIAN_POINT('',(-44.9903975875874,0.929714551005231,2.02896645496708));
#697=CARTESIAN_POINT('',(-44.9910315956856,0.898509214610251,2.0161336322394));
#698=CARTESIAN_POINT('',(-44.9913513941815,0.882366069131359,2.01103694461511));
#699=CARTESIAN_POINT('',(-44.9918760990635,0.855103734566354,2.00489534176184));
#700=CARTESIAN_POINT('',(-44.9920828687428,0.844155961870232,2.00306071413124));
#701=CARTESIAN_POINT('',(-44.9924905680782,0.822140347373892,2.00061320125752));
#702=CARTESIAN_POINT('',(-44.9926915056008,0.811072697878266,1.99999858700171));
#703=CARTESIAN_POINT('',(-44.9928883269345,0.800000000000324,1.99999999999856));
#704=B_SPLINE_CURVE_WITH_KNOTS('',3,(#682,#683,#684,#685,#686,#687,#688,#689,#690,#691,#692,
#693,#694,#695,#696,#697,#698,#699,#700,#701,#702,#703),.UNSPECIFIED.,.F.,.F.,(4,2,2,2,2,2,2,2,
2,2,4),(0.,0.0505550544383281,0.101069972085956,0.15160897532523,0.202139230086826,
0.252676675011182,0.303224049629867,0.353794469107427,0.404335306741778,0.437579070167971,
0.470775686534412),.UNSPECIFIED.);
#705=CARTESIAN_POINT('',(-44.9928883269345,0.8,2.));
#706=VERTEX_POINT('',#705);
#707=EDGE_CURVE('E1467',#679,#706,#704,.T.);
#708=ORIENTED_EDGE('',*,*,#707,.T.);
#709=CARTESIAN_POINT('',(0.,0.,2.));
#710=DIRECTION('',(0.,0.,-1.));
#711=DIRECTION('',(-1.,0.,0.));
#712=AXIS2_PLACEMENT_3D('',#709,#710,#711);
#713=CIRCLE('',#712,45.);
#714=CARTESIAN_POINT('',(-44.9928883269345,-0.8,2.));
#715=VERTEX_POINT('',#714);
#716=EDGE_CURVE('E1495',#706,#715,#713,.F.);
#717=ORIENTED_EDGE('',*,*,#716,.T.);
#718=CARTESIAN_POINT('',(-44.9928883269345,-0.8,2.));
#719=CARTESIAN_POINT('',(-44.9925885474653,-0.816880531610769,1.99998568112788));
#720=CARTESIAN_POINT('',(-44.9922786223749,-0.833756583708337,2.00142390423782));
#721=CARTESIAN_POINT('',(-44.9916497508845,-0.867018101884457,2.00709958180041));
#722=CARTESIAN_POINT('',(-44.9913308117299,-0.883403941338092,2.01133484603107));
#723=CARTESIAN_POINT('',(-44.9906945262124,-0.915238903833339,2.02250173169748));
#724=CARTESIAN_POINT('',(-44.9903771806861,-0.930687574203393,2.02943464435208));
#725=CARTESIAN_POINT('',(-44.9897570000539,-0.960199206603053,2.04579409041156));
#726=CARTESIAN_POINT('',(-44.9894541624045,-0.974262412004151,2.05522018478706));
#727=CARTESIAN_POINT('',(-44.9888759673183,-1.00060646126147,2.07630001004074));
#728=CARTESIAN_POINT('',(-44.9886006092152,-1.01288734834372,2.08795368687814));
#729=CARTESIAN_POINT('',(-44.9880899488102,-1.03532070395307,2.11316093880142));
#730=CARTESIAN_POINT('',(-44.987854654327,-1.04547275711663,2.12671488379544));
#731=CARTESIAN_POINT('',(-44.9874355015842,-1.06335662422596,2.15533439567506));
#732=CARTESIAN_POINT('',(-44.9872516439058,-1.07108841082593,2.17039997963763));
#733=CARTESIAN_POINT('',(-44.9869445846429,-1.08390881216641,2.20161299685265));
#734=CARTESIAN_POINT('',(-44.9868213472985,-1.08899898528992,2.21775978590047));
#735=CARTESIAN_POINT('',(-44.9866725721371,-1.09512408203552,2.24500482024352));
#736=CARTESIAN_POINT('',(-44.9866280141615,-1.09695144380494,2.25593138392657));
#737=CARTESIAN_POINT('',(-44.986568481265,-1.09938924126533,2.2779037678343));
#738=CARTESIAN_POINT('',(-44.986553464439,-1.100001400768,2.28894939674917));
#739=CARTESIAN_POINT('',(-44.9865535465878,-1.10000000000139,2.29999999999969));
#740=B_SPLINE_CURVE_WITH_KNOTS('',3,(#718,#719,#720,#721,#722,#723,#724,#725,#726,#727,#728,
#729,#730,#731,#732,#733,#734,#735,#736,#737,#738,#739),.UNSPECIFIED.,.F.,.F.,(4,2,2,2,2,2,2,2,
2,2,4),(0.,0.0505822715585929,0.101124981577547,0.151691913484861,0.202249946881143,
0.252806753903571,0.303373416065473,0.353940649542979,0.404478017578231,0.437650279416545,
0.470775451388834),.UNSPECIFIED.);
#741=CARTESIAN_POINT('',(-44.9865535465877,-1.1,2.3));
#742=VERTEX_POINT('',#741);
#743=EDGE_CURVE('E1487',#715,#742,#740,.T.);
#744=ORIENTED_EDGE('',*,*,#743,.T.);
#745=DIRECTION('',(0.,0.,-1.));
#746=VECTOR('',#745,1.);
#747=CARTESIAN_POINT('',(-44.9865535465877,-1.1,6.));
#748=LINE('',#747,#746);
#749=CARTESIAN_POINT('',(-44.9865535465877,-1.1,5.7));
#750=VERTEX_POINT('',#749);
#751=EDGE_CURVE('E1494',#742,#750,#748,.F.);
#752=ORIENTED_EDGE('',*,*,#751,.T.);
#753=CARTESIAN_POINT('',(-44.9865535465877,-1.1,5.7));
#754=CARTESIAN_POINT('',(-44.9865536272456,-1.09998564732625,5.71687352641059));
#755=CARTESIAN_POINT('',(-44.9865187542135,-1.10142272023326,5.73374274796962));
#756=CARTESIAN_POINT('',(-44.9863796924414,-1.10709378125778,5.76699093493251));
#757=CARTESIAN_POINT('',(-44.986275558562,-1.11132555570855,5.78337027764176));
#758=CARTESIAN_POINT('',(-44.9859984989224,-1.12248305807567,5.81519284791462));
#759=CARTESIAN_POINT('',(-44.9858255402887,-1.12941007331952,5.83063562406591));
#760=CARTESIAN_POINT('',(-44.9854122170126,-1.14575506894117,5.86013640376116));
#761=CARTESIAN_POINT('',(-44.985171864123,-1.1551726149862,5.87419464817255));
#762=CARTESIAN_POINT('',(-44.9846260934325,-1.17623371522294,5.900531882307));
#763=CARTESIAN_POINT('',(-44.984320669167,-1.18787749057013,5.9128106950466));
#764=CARTESIAN_POINT('',(-44.9836485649,-1.21306230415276,5.93524170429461));
#765=CARTESIAN_POINT('',(-44.9832818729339,-1.22660371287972,5.94539348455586));
#766=CARTESIAN_POINT('',(-44.9824929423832,-1.25520245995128,5.96328390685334));
#767=CARTESIAN_POINT('',(-44.9820706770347,-1.27026052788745,5.97102138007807));
#768=CARTESIAN_POINT('',(-44.9811788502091,-1.30145767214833,5.98385466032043));
#769=CARTESIAN_POINT('',(-44.980709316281,-1.3175961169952,5.9889519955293));
#770=CARTESIAN_POINT('',(-44.9799007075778,-1.34486053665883,5.99509827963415));
#771=CARTESIAN_POINT('',(-44.9795718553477,-1.35581565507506,5.9969353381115));
#772=CARTESIAN_POINT('',(-44.9789024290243,-1.37784570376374,5.99938603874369));
#773=CARTESIAN_POINT('',(-44.9785618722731,-1.3889204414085,6.00000141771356));
#774=CARTESIAN_POINT('',(-44.9782169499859,-1.39999999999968,6.00000000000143));
#775=B_SPLINE_CURVE_WITH_KNOTS('',3,(#753,#754,#755,#756,#757,#758,#759,#760,#761,#762,#763,
#764,#765,#766,#767,#768,#769,#770,#771,#772,#773,#774),.UNSPECIFIED.,.F.,.F.,(4,2,2,2,2,2,2,2,
2,2,4),(0.,0.0505532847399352,0.101066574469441,0.151604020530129,0.202132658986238,
0.25266631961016,0.303209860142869,0.35377783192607,0.404316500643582,0.437591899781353,
0.470819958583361),.UNSPECIFIED.);
#776=CARTESIAN_POINT('',(-44.9782169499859,-1.4,6.));
#777=VERTEX_POINT('',#776);
#778=EDGE_CURVE('E1530',#750,#777,#775,.T.);
#779=ORIENTED_EDGE('',*,*,#778,.T.);
#780=CARTESIAN_POINT('',(-42.5312826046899,-14.7,6.));
#781=VERTEX_POINT('',#780);
#782=EDGE_CURVE('E1515',#781,#777,#627,.T.);
#783=ORIENTED_EDGE('',*,*,#782,.F.);
#784=CARTESIAN_POINT('',(-42.5312826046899,-14.7,6.));
#785=CARTESIAN_POINT('',(-42.5251842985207,-14.7176455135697,6.00001045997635));
#786=CARTESIAN_POINT('',(-42.5190737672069,-14.7352881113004,5.99844362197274));
#787=CARTESIAN_POINT('',(-42.5069960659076,-14.7700918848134,5.99222976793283));
#788=CARTESIAN_POINT('',(-42.501029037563,-14.7872525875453,5.98757982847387));
#789=CARTESIAN_POINT('',(-42.4894125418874,-14.8205984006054,5.9752682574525));
#790=CARTESIAN_POINT('',(-42.4837634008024,-14.8367825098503,5.96760359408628));
#791=CARTESIAN_POINT('',(-42.4729725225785,-14.8676451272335,5.94943007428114));
#792=CARTESIAN_POINT('',(-42.4678304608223,-14.8823245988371,5.93892305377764));
#793=CARTESIAN_POINT('',(-42.4583655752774,-14.9093055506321,5.91563835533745));
#794=CARTESIAN_POINT('',(-42.4540239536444,-14.9216617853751,5.90293190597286));
#795=CARTESIAN_POINT('',(-42.4461513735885,-14.9440414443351,5.87538079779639));
#796=CARTESIAN_POINT('',(-42.4426204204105,-14.9540648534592,5.86053612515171));
#797=CARTESIAN_POINT('',(-42.4366891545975,-14.970888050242,5.83002438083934));
#798=CARTESIAN_POINT('',(-42.4342368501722,-14.9778362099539,5.81444907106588));
#799=CARTESIAN_POINT('',(-42.4302923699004,-14.9890068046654,5.78224612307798));
#800=CARTESIAN_POINT('',(-42.4287987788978,-14.9932332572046,5.76562007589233));
#801=CARTESIAN_POINT('',(-42.4273473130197,-14.9973398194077,5.74069369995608));
#802=CARTESIAN_POINT('',(-42.4269947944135,-14.9983370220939,5.73258512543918));
#803=CARTESIAN_POINT('',(-42.4265247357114,-14.999666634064,5.71631914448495));
#804=CARTESIAN_POINT('',(-42.4264068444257,-15.0000000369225,5.70816182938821));
#805=CARTESIAN_POINT('',(-42.4264068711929,-15.,5.70000000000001));
#806=B_SPLINE_CURVE_WITH_KNOTS('',3,(#784,#785,#786,#787,#788,#789,#790,#791,#792,#793,#794,
#795,#796,#797,#798,#799,#800,#801,#802,#803,#804,#805),.UNSPECIFIED.,.F.,.F.,(4,2,2,2,2,2,2,2,
2,2,4),(0.,0.0559461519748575,0.111945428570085,0.168001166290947,0.224020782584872,
0.278483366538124,0.332946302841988,0.384377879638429,0.435733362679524,0.460239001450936,
0.484707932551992),.UNSPECIFIED.);
#807=CARTESIAN_POINT('',(-42.4264068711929,-15.,5.7));
#808=VERTEX_POINT('',#807);
#809=EDGE_CURVE('E1378',#781,#808,#806,.T.);
#810=ORIENTED_EDGE('',*,*,#809,.T.);
#811=DIRECTION('',(0.,0.,-1.));
#812=VECTOR('',#811,1.);
#813=CARTESIAN_POINT('',(-42.4264068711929,-15.,6.));
#814=LINE('',#813,#812);
#815=CARTESIAN_POINT('',(-42.4264068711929,-15.,0.3));
#816=VERTEX_POINT('',#815);
#817=EDGE_CURVE('E1375',#808,#816,#814,.T.);
#818=ORIENTED_EDGE('',*,*,#817,.T.);
#819=CARTESIAN_POINT('',(-42.4264068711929,-15.,0.3));
#820=CARTESIAN_POINT('',(-42.4264005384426,-15.0000171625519,0.283812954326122));
#821=CARTESIAN_POINT('',(-42.4268696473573,-14.998691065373,0.267635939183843));
#822=CARTESIAN_POINT('',(-42.4287096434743,-14.9934856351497,0.235788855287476));
#823=CARTESIAN_POINT('',(-42.4300783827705,-14.989612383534,0.220117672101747));
#824=CARTESIAN_POINT('',(-42.4336687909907,-14.9794452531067,0.189689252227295));
#825=CARTESIAN_POINT('',(-42.4358903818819,-14.9731515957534,0.174931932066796));
#826=CARTESIAN_POINT('',(-42.4411029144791,-14.9583703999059,0.146707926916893));
#827=CARTESIAN_POINT('',(-42.4440940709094,-14.9498822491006,0.133241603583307));
#828=CARTESIAN_POINT('',(-42.4508256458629,-14.9307570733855,0.107612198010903));
#829=CARTESIAN_POINT('',(-42.454582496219,-14.9200728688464,0.0954887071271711));
#830=CARTESIAN_POINT('',(-42.4626770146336,-14.8970201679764,0.0731954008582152));
#831=CARTESIAN_POINT('',(-42.4670148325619,-14.8846512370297,0.063026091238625));
#832=CARTESIAN_POINT('',(-42.4763931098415,-14.8578679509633,0.0443469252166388));
#833=CARTESIAN_POINT('',(-42.4814588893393,-14.8433791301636,0.0359566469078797));
#834=CARTESIAN_POINT('',(-42.4919505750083,-14.8133179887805,0.0217274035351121));
#835=CARTESIAN_POINT('',(-42.4973765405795,-14.7977454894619,0.0158888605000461));
#836=CARTESIAN_POINT('',(-42.5075457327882,-14.7685054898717,0.0075976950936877));
#837=CARTESIAN_POINT('',(-42.5122574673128,-14.7549371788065,0.00475020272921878));
#838=CARTESIAN_POINT('',(-42.521742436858,-14.7275806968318,0.000951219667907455));
#839=CARTESIAN_POINT('',(-42.5265155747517,-14.7137928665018,-2.9650561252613E-06));
#840=CARTESIAN_POINT('',(-42.5312826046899,-14.7,0.));
#841=B_SPLINE_CURVE_WITH_KNOTS('',3,(#819,#820,#821,#822,#823,#824,#825,#826,#827,#828,#829,
#830,#831,#832,#833,#834,#835,#836,#837,#838,#839,#840),.UNSPECIFIED.,.F.,.F.,(4,2,2,2,2,2,2,2,
2,2,4),(0.,0.0484846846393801,0.0968540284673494,0.145218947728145,0.193597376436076,
0.24315068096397,0.292716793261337,0.34496511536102,0.397222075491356,0.441028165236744,
0.484771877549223),.UNSPECIFIED.);
#842=CARTESIAN_POINT('',(-42.5312826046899,-14.7,0.));
#843=VERTEX_POINT('',#842);
#844=EDGE_CURVE('E1377',#816,#843,#841,.T.);
#845=ORIENTED_EDGE('',*,*,#844,.T.);
#846=CARTESIAN_POINT('',(0.,0.,0.));
#847=DIRECTION('',(0.,0.,-1.));
#848=DIRECTION('',(1.,0.,0.));
#849=AXIS2_PLACEMENT_3D('',#846,#847,#848);
#850=CIRCLE('',#849,45.);
#851=CARTESIAN_POINT('',(-42.5312826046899,14.7,0.));
#852=VERTEX_POINT('',#851);
#853=EDGE_CURVE('E1381',#843,#852,#850,.T.);
#854=ORIENTED_EDGE('',*,*,#853,.T.);
#855=CARTESIAN_POINT('',(-42.5312826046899,14.7,0.));
#856=CARTESIAN_POINT('',(-42.5251842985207,14.7176455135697,-1.04599763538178E-05));
#857=CARTESIAN_POINT('',(-42.5190737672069,14.7352881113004,0.00155637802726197));
#858=CARTESIAN_POINT('',(-42.5069960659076,14.7700918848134,0.00777023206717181));
#859=CARTESIAN_POINT('',(-42.501029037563,14.7872525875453,0.0124201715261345));
#860=CARTESIAN_POINT('',(-42.4894125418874,14.8205984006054,0.0247317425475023));
#861=CARTESIAN_POINT('',(-42.4837634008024,14.8367825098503,0.0323964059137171));
#862=CARTESIAN_POINT('',(-42.4729725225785,14.8676451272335,0.0505699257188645));
#863=CARTESIAN_POINT('',(-42.4678304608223,14.8823245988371,0.0610769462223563));
#864=CARTESIAN_POINT('',(-42.4583655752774,14.9093055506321,0.0843616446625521));
#865=CARTESIAN_POINT('',(-42.4540239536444,14.9216617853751,0.0970680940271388));
#866=CARTESIAN_POINT('',(-42.4461513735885,14.9440414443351,0.124619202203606));
#867=CARTESIAN_POINT('',(-42.4426204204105,14.9540648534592,0.139463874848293));
#868=CARTESIAN_POINT('',(-42.4366891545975,14.970888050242,0.169975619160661));
#869=CARTESIAN_POINT('',(-42.4342368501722,14.9778362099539,0.185550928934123));
#870=CARTESIAN_POINT('',(-42.4302923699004,14.9890068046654,0.21775387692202));
#871=CARTESIAN_POINT('',(-42.4287987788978,14.9932332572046,0.234379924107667));
#872=CARTESIAN_POINT('',(-42.4273473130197,14.9973398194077,0.259306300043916));
#873=CARTESIAN_POINT('',(-42.4269947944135,14.9983370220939,0.267414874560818));
#874=CARTESIAN_POINT('',(-42.4265247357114,14.999666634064,0.283680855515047));
#875=CARTESIAN_POINT('',(-42.4264068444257,15.0000000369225,0.291838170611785));
#876=CARTESIAN_POINT('',(-42.4264068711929,15.,0.299999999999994));
#877=B_SPLINE_CURVE_WITH_KNOTS('',3,(#855,#856,#857,#858,#859,#860,#861,#862,#863,#864,#865,
#866,#867,#868,#869,#870,#871,#872,#873,#874,#875,#876),.UNSPECIFIED.,.F.,.F.,(4,2,2,2,2,2,2,2,
2,2,4),(0.,0.0559461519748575,0.111945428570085,0.168001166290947,0.224020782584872,
0.278483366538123,0.332946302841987,0.384377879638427,0.435733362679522,0.460239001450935,
0.484707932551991),.UNSPECIFIED.);
#878=CARTESIAN_POINT('',(-42.4264068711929,15.,0.3));
#879=VERTEX_POINT('',#878);
#880=EDGE_CURVE('E1571',#852,#879,#877,.T.);
#881=ORIENTED_EDGE('',*,*,#880,.T.);
#882=DIRECTION('',(0.,0.,-1.));
#883=VECTOR('',#882,1.);
#884=CARTESIAN_POINT('',(-42.4264068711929,15.,6.));
#885=LINE('',#884,#883);
#886=CARTESIAN_POINT('',(-42.4264068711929,15.,5.7));
#887=VERTEX_POINT('',#886);
#888=EDGE_CURVE('E1360',#887,#879,#885,.T.);
#889=ORIENTED_EDGE('',*,*,#888,.F.);
#890=CARTESIAN_POINT('',(-42.4264068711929,15.,5.7));
#891=CARTESIAN_POINT('',(-42.4264005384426,15.0000171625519,5.71618704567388));
#892=CARTESIAN_POINT('',(-42.4268696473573,14.998691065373,5.73236406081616));
#893=CARTESIAN_POINT('',(-42.4287096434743,14.9934856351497,5.76421114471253));
#894=CARTESIAN_POINT('',(-42.4300783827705,14.989612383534,5.77988232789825));
#895=CARTESIAN_POINT('',(-42.4336687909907,14.9794452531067,5.8103107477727));
#896=CARTESIAN_POINT('',(-42.4358903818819,14.9731515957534,5.8250680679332));
#897=CARTESIAN_POINT('',(-42.4411029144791,14.9583703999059,5.85329207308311));
#898=CARTESIAN_POINT('',(-42.4440940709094,14.9498822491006,5.86675839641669));
#899=CARTESIAN_POINT('',(-42.4508256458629,14.9307570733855,5.8923878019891));
#900=CARTESIAN_POINT('',(-42.454582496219,14.9200728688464,5.90451129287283));
#901=CARTESIAN_POINT('',(-42.4626770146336,14.8970201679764,5.92680459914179));
#902=CARTESIAN_POINT('',(-42.4670148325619,14.8846512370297,5.93697390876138));
#903=CARTESIAN_POINT('',(-42.4763931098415,14.8578679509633,5.95565307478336));
#904=CARTESIAN_POINT('',(-42.4814588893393,14.8433791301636,5.96404335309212));
#905=CARTESIAN_POINT('',(-42.4919505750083,14.8133179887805,5.97827259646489));
#906=CARTESIAN_POINT('',(-42.4973765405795,14.7977454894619,5.98411113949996));
#907=CARTESIAN_POINT('',(-42.5075457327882,14.7685054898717,5.99240230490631));
#908=CARTESIAN_POINT('',(-42.5122574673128,14.7549371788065,5.99524979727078));
#909=CARTESIAN_POINT('',(-42.521742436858,14.7275806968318,5.99904878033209));
#910=CARTESIAN_POINT('',(-42.5265155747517,14.7137928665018,6.00000296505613));
#911=CARTESIAN_POINT('',(-42.5312826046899,14.7,6.));
#912=B_SPLINE_CURVE_WITH_KNOTS('',3,(#890,#891,#892,#893,#894,#895,#896,#897,#898,#899,#900,
#901,#902,#903,#904,#905,#906,#907,#908,#909,#910,#911),.UNSPECIFIED.,.F.,.F.,(4,2,2,2,2,2,2,2,
2,2,4),(0.,0.0484846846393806,0.096854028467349,0.145218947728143,0.193597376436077,
0.243150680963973,0.292716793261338,0.344965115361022,0.397222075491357,0.441028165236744,
0.484771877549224),.UNSPECIFIED.);
#913=EDGE_CURVE('E1498',#887,#629,#912,.T.);
#914=ORIENTED_EDGE('',*,*,#913,.T.);
#915=EDGE_LOOP('',(#646,#673,#681,#708,#717,#744,#752,#779,#783,#810,#818,#845,#854,#881,#889,#914));
#916=FACE_BOUND('',#915,.T.);
#917=ADVANCED_FACE('F1484',(#916),#645,.F.);
#918=CARTESIAN_POINT('',(-42.4794362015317,15.,6.));
#919=DIRECTION('',(0.,-1.,0.));
#920=DIRECTION('',(0.,0.,-1.));
#921=AXIS2_PLACEMENT_3D('',#918,#919,#920);
#922=PLANE('',#921);
#923=ORIENTED_EDGE('',*,*,#346,.F.);
#924=DIRECTION('',(-1.,0.,0.));
#925=VECTOR('',#924,1.);
#926=CARTESIAN_POINT('',(-42.4264068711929,15.,5.7));
#927=LINE('',#926,#925);
#928=EDGE_CURVE('E1365',#337,#887,#927,.F.);
#929=ORIENTED_EDGE('',*,*,#928,.T.);
#930=ORIENTED_EDGE('',*,*,#888,.T.);
#931=DIRECTION('',(-1.,0.,0.));
#932=VECTOR('',#931,1.);
#933=CARTESIAN_POINT('',(-42.4794362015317,15.,0.3));
#934=LINE('',#933,#932);
#935=EDGE_CURVE('E1364',#879,#345,#934,.T.);
#936=ORIENTED_EDGE('',*,*,#935,.T.);
#937=EDGE_LOOP('',(#923,#929,#930,#936));
#938=FACE_BOUND('',#937,.T.);
#939=ADVANCED_FACE('F1400',(#938),#922,.F.);
#940=DIRECTION('',(0.,0.,-1.));
#941=VECTOR('',#940,1.);
#942=CARTESIAN_POINT('',(-42.6888704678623,-14.3931524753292,3.65));
#943=LINE('',#942,#941);
#944=CARTESIAN_POINT('',(-42.6888704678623,-14.3931524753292,3.65));
#945=VERTEX_POINT('',#944);
#946=CARTESIAN_POINT('',(-42.6888704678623,-14.3931524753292,3.45));
#947=VERTEX_POINT('',#946);
#948=EDGE_CURVE('E1501',#945,#947,#943,.T.);
#949=ORIENTED_EDGE('',*,*,#948,.T.);
#950=CARTESIAN_POINT('',(0.,0.,3.45));
#951=DIRECTION('',(0.,0.,-1.));
#952=DIRECTION('',(-0.963850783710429,-0.266442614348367,0.));
#953=AXIS2_PLACEMENT_3D('',#950,#951,#952);
#954=CIRCLE('',#953,45.05);
#955=CARTESIAN_POINT('',(-43.4214778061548,-12.0032397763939,3.45));
#956=VERTEX_POINT('',#955);
#957=EDGE_CURVE('E772',#947,#956,#954,.T.);
#958=ORIENTED_EDGE('',*,*,#957,.T.);
#959=DIRECTION('',(0.,0.,1.));
#960=VECTOR('',#959,1.);
#961=CARTESIAN_POINT('',(-43.4214778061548,-12.0032397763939,3.45));
#962=LINE('',#961,#960);
#963=CARTESIAN_POINT('',(-43.4214778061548,-12.003239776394,3.65));
#964=VERTEX_POINT('',#963);
#965=EDGE_CURVE('E767',#956,#964,#962,.T.);
#966=ORIENTED_EDGE('',*,*,#965,.T.);
#967=CARTESIAN_POINT('',(0.,0.,3.65));
#968=DIRECTION('',(0.,0.,-1.));
#969=DIRECTION('',(-0.963850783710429,-0.266442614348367,0.));
#970=AXIS2_PLACEMENT_3D('',#967,#968,#969);
#971=CIRCLE('',#970,45.05);
#972=EDGE_CURVE('E2931',#945,#964,#971,.T.);
#973=ORIENTED_EDGE('',*,*,#972,.F.);
#974=EDGE_LOOP('',(#949,#958,#966,#973));
#975=FACE_BOUND('',#974,.T.);
#976=CARTESIAN_POINT('',(0.,0.,2.));
#977=DIRECTION('',(0.,0.,-1.));
#978=DIRECTION('',(-0.998913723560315,-0.0465979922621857,0.));
#979=AXIS2_PLACEMENT_3D('',#976,#977,#978);
#980=CIRCLE('',#979,45.05);
#981=CARTESIAN_POINT('',(-44.9913002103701,-2.29900095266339,2.));
#982=VERTEX_POINT('',#981);
#983=CARTESIAN_POINT('',(-45.0010632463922,-2.09923955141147,2.));
#984=VERTEX_POINT('',#983);
#985=EDGE_CURVE('E744',#982,#984,#980,.T.);
#986=ORIENTED_EDGE('',*,*,#985,.T.);
#987=DIRECTION('',(0.,0.,1.));
#988=VECTOR('',#987,1.);
#989=CARTESIAN_POINT('',(-45.0010632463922,-2.09923955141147,2.));
#990=LINE('',#989,#988);
#991=CARTESIAN_POINT('',(-45.0010632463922,-2.09923955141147,6.));
#992=VERTEX_POINT('',#991);
#993=EDGE_CURVE('E754',#984,#992,#990,.T.);
#994=ORIENTED_EDGE('',*,*,#993,.T.);
#995=CARTESIAN_POINT('',(-45.0282411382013,-1.4,6.));
#996=VERTEX_POINT('',#995);
#997=EDGE_CURVE('E780',#996,#992,#132,.T.);
#998=ORIENTED_EDGE('',*,*,#997,.F.);
#999=CARTESIAN_POINT('',(-45.0282411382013,-1.4,6.));
#1000=CARTESIAN_POINT('',(-45.0287663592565,-1.38311908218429,6.00001432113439));
#1001=CARTESIAN_POINT('',(-45.0292812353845,-1.36624203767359,5.99857602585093));
#1002=CARTESIAN_POINT('',(-45.0302780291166,-1.3329773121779,5.99289947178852));
#1003=CARTESIAN_POINT('',(-45.0307599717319,-1.31658926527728,5.98866336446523));
#1004=CARTESIAN_POINT('',(-45.0316796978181,-1.28474900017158,5.97749342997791));
#1005=CARTESIAN_POINT('',(-45.0321174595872,-1.26929724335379,5.97055828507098));
#1006=CARTESIAN_POINT('',(-45.0329397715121,-1.23977947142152,5.95419274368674));
#1007=CARTESIAN_POINT('',(-45.0333243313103,-1.22571320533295,5.94476280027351));
#1008=CARTESIAN_POINT('',(-45.03403371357,-1.19936716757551,5.92367638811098));
#1009=CARTESIAN_POINT('',(-45.0343585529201,-1.18708689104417,5.91202055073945));
#1010=CARTESIAN_POINT('',(-45.0349442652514,-1.16465498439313,5.88680855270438));
#1011=CARTESIAN_POINT('',(-45.0352051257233,-1.15450377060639,5.87325202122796));
#1012=CARTESIAN_POINT('',(-45.0356599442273,-1.13662380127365,5.84462979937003));
#1013=CARTESIAN_POINT('',(-45.0358539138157,-1.12889462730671,5.82956437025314));
#1014=CARTESIAN_POINT('',(-45.0361733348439,-1.11607916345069,5.79835207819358));
#1015=CARTESIAN_POINT('',(-45.0362988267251,-1.11099131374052,5.78220585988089));
#1016=CARTESIAN_POINT('',(-45.0364493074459,-1.10487086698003,5.75496691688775));
#1017=CARTESIAN_POINT('',(-45.0364940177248,-1.10304539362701,5.74404587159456));
#1018=CARTESIAN_POINT('',(-45.0365535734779,-1.10061012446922,5.72208474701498));
#1019=CARTESIAN_POINT('',(-45.0365684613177,-1.09999860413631,5.71104485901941));
#1020=CARTESIAN_POINT('',(-45.0365684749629,-1.0999999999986,5.70000000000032));
#1021=B_SPLINE_CURVE_WITH_KNOTS('',3,(#999,#1000,#1001,#1002,#1003,#1004,#1005,#1006,#1007,
#1008,#1009,#1010,#1011,#1012,#1013,#1014,#1015,#1016,#1017,#1018,#1019,#1020),.UNSPECIFIED.,
.F.,.F.,(4,2,2,2,2,2,2,2,2,2,4),(0.,0.0506001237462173,0.101161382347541,0.151747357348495,
0.202324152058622,0.2528866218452,0.303458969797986,0.354022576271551,0.404556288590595,
0.437711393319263,0.470819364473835),.UNSPECIFIED.);
#1022=CARTESIAN_POINT('',(-45.0365684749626,-1.1,5.7));
#1023=VERTEX_POINT('',#1022);
#1024=EDGE_CURVE('E761',#996,#1023,#1021,.T.);
#1025=ORIENTED_EDGE('',*,*,#1024,.T.);
#1026=DIRECTION('',(0.,0.,-1.));
#1027=VECTOR('',#1026,1.);
#1028=CARTESIAN_POINT('',(-45.0365684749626,-1.1,6.));
#1029=LINE('',#1028,#1027);
#1030=CARTESIAN_POINT('',(-45.0365684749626,-1.1,2.3));
#1031=VERTEX_POINT('',#1030);
#1032=EDGE_CURVE('E1346',#1023,#1031,#1029,.T.);
#1033=ORIENTED_EDGE('',*,*,#1032,.T.);
#1034=CARTESIAN_POINT('',(-45.0365684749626,-1.1,2.3));
#1035=CARTESIAN_POINT('',(-45.0365678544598,-1.10001435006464,2.28312586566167));
#1036=CARTESIAN_POINT('',(-45.0366032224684,-1.09857717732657,2.26625605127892));
#1037=CARTESIAN_POINT('',(-45.0367413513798,-1.09290572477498,2.233006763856));
#1038=CARTESIAN_POINT('',(-45.0368440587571,-1.08867366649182,2.2166269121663));
#1039=CARTESIAN_POINT('',(-45.0371123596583,-1.07751541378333,2.18480338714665));
#1040=CARTESIAN_POINT('',(-45.0372779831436,-1.07058793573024,2.16936016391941));
#1041=CARTESIAN_POINT('',(-45.0376635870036,-1.05424173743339,2.13985845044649));
#1042=CARTESIAN_POINT('',(-45.0378835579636,-1.0448234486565,2.1257997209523));
#1043=CARTESIAN_POINT('',(-45.0383672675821,-1.02375993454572,2.09946088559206));
#1044=CARTESIAN_POINT('',(-45.0386310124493,-1.01211439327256,2.08718103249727));
#1045=CARTESIAN_POINT('',(-45.0391900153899,-0.986925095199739,2.06474811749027));
#1046=CARTESIAN_POINT('',(-45.0394852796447,-0.97338096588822,2.05459547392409));
#1047=CARTESIAN_POINT('',(-45.0400943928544,-0.944775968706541,2.03670405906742));
#1048=CARTESIAN_POINT('',(-45.0404082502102,-0.92971441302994,2.02896638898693));
#1049=CARTESIAN_POINT('',(-45.041041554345,-0.898509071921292,2.01613358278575));
#1050=CARTESIAN_POINT('',(-45.0413609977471,-0.882365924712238,2.01103690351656));
#1051=CARTESIAN_POINT('',(-45.041885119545,-0.85510361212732,2.0048953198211));
#1052=CARTESIAN_POINT('',(-45.0420916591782,-0.844155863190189,2.00306070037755));
#1053=CARTESIAN_POINT('',(-45.0424989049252,-0.822140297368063,2.00061319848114));
#1054=CARTESIAN_POINT('',(-45.0426996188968,-0.811072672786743,1.99999858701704));
#1055=CARTESIAN_POINT('',(-45.0428962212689,-0.800000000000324,1.99999999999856));
#1056=B_SPLINE_CURVE_WITH_KNOTS('',3,(#1034,#1035,#1036,#1037,#1038,#1039,#1040,#1041,#1042,
#1043,#1044,#1045,#1046,#1047,#1048,#1049,#1050,#1051,#1052,#1053,#1054,#1055),.UNSPECIFIED.,
.F.,.F.,(4,2,2,2,2,2,2,2,2,2,4),(0.,0.050555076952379,0.101070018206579,0.151609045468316,
0.202139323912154,0.25267677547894,0.303224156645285,0.353794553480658,0.4043353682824,
0.437579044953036,0.470775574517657),.UNSPECIFIED.);
#1057=CARTESIAN_POINT('',(-45.0428962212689,-0.8,2.));
#1058=VERTEX_POINT('',#1057);
#1059=EDGE_CURVE('E1342',#1031,#1058,#1056,.T.);
#1060=ORIENTED_EDGE('',*,*,#1059,.T.);
#1061=EDGE_CURVE('E1337',#1058,#390,#397,.T.);
#1062=ORIENTED_EDGE('',*,*,#1061,.T.);
#1063=CARTESIAN_POINT('',(-44.9594215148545,-2.85533133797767,0.));
#1064=CARTESIAN_POINT('',(-45.0228029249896,-1.85734154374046,0.666666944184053));
#1065=CARTESIAN_POINT('',(-45.0529425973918,-0.857242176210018,1.33333305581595));
#1066=CARTESIAN_POINT('',(-45.049773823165,0.142753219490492,2.));
#1067=B_SPLINE_CURVE_WITH_KNOTS('',3,(#1063,#1064,#1065,#1066),.UNSPECIFIED.,.F.,.F.,(4,4),(0.,
1.),.UNSPECIFIED.);
#1068=CARTESIAN_POINT('',(-44.9594215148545,-2.85533133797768,0.));
#1069=VERTEX_POINT('',#1068);
#1070=EDGE_CURVE('E1319',#390,#1069,#1067,.F.);
#1071=ORIENTED_EDGE('',*,*,#1070,.T.);
#1072=CARTESIAN_POINT('',(-42.5841813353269,-14.7,0.));
#1073=VERTEX_POINT('',#1072);
#1074=EDGE_CURVE('E1336',#1069,#1073,#379,.T.);
#1075=ORIENTED_EDGE('',*,*,#1074,.T.);
#1076=CARTESIAN_POINT('',(-42.5841813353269,-14.7,0.));
#1077=CARTESIAN_POINT('',(-42.5780912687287,-14.7176435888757,-1.04705352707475E-05));
#1078=CARTESIAN_POINT('',(-42.5719889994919,-14.7352842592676,0.00155603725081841));
#1079=CARTESIAN_POINT('',(-42.5599276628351,-14.7700841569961,0.00776850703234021));
#1080=CARTESIAN_POINT('',(-42.5539687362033,-14.7872429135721,0.0124173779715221));
#1081=CARTESIAN_POINT('',(-42.5423680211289,-14.8205849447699,0.0247259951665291));
#1082=CARTESIAN_POINT('',(-42.5367265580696,-14.8367672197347,0.0323887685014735));
#1083=CARTESIAN_POINT('',(-42.5259502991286,-14.8676264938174,0.0505575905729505));
#1084=CARTESIAN_POINT('',(-42.5208151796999,-14.8823044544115,0.0610618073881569));
#1085=CARTESIAN_POINT('',(-42.511362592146,-14.9092840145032,0.0843408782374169));
#1086=CARTESIAN_POINT('',(-42.5070264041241,-14.9216402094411,0.0970447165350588));
#1087=CARTESIAN_POINT('',(-42.4991634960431,-14.9440203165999,0.124590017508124));
#1088=CARTESIAN_POINT('',(-42.4956367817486,-14.9540442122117,0.139431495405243));
#1089=CARTESIAN_POINT('',(-42.4897118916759,-14.9708703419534,0.169938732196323));
#1090=CARTESIAN_POINT('',(-42.4872619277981,-14.9778205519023,0.185512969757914));
#1091=CARTESIAN_POINT('',(-42.4833208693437,-14.9889954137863,0.217713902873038));
#1092=CARTESIAN_POINT('',(-42.4818283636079,-14.99322407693,0.234339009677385));
#1093=CARTESIAN_POINT('',(-42.4803770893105,-14.9973352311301,0.2592713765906));
#1094=CARTESIAN_POINT('',(-42.4800244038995,-14.9983341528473,0.267386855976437));
#1095=CARTESIAN_POINT('',(-42.4795541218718,-14.9996660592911,0.283666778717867));
#1096=CARTESIAN_POINT('',(-42.4794361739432,-15.0000000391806,0.291831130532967));
#1097=CARTESIAN_POINT('',(-42.4794362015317,-15.,0.299999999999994));
#1098=B_SPLINE_CURVE_WITH_KNOTS('',3,(#1076,#1077,#1078,#1079,#1080,#1081,#1082,#1083,#1084,
#1085,#1086,#1087,#1088,#1089,#1090,#1091,#1092,#1093,#1094,#1095,#1096,#1097),.UNSPECIFIED.,
.F.,.F.,(4,2,2,2,2,2,2,2,2,2,4),(0.,0.0559326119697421,0.111918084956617,0.167959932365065,
0.223965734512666,0.278419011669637,0.332872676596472,0.384302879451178,0.435657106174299,
0.460183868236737,0.48467389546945),.UNSPECIFIED.);
#1099=CARTESIAN_POINT('',(-42.4794362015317,-15.,0.3));
#1100=VERTEX_POINT('',#1099);
#1101=EDGE_CURVE('E1340',#1073,#1100,#1098,.T.);
#1102=ORIENTED_EDGE('',*,*,#1101,.T.);
#1103=DIRECTION('',(0.,0.,-1.));
#1104=VECTOR('',#1103,1.);
#1105=CARTESIAN_POINT('',(-42.4794362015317,-15.,6.));
#1106=LINE('',#1105,#1104);
#1107=CARTESIAN_POINT('',(-42.4794362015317,-15.,5.7));
#1108=VERTEX_POINT('',#1107);
#1109=EDGE_CURVE('E1370',#1108,#1100,#1106,.T.);
#1110=ORIENTED_EDGE('',*,*,#1109,.F.);
#1111=CARTESIAN_POINT('',(-42.4794362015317,-15.,5.7));
#1112=CARTESIAN_POINT('',(-42.4794298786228,-15.000017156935,5.71618861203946));
#1113=CARTESIAN_POINT('',(-42.4798984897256,-14.9986908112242,5.73236720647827));
#1114=CARTESIAN_POINT('',(-42.4817365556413,-14.9934843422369,5.76421748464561));
#1115=CARTESIAN_POINT('',(-42.4831038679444,-14.9896102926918,5.77989028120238));
#1116=CARTESIAN_POINT('',(-42.4866905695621,-14.9794409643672,5.81032188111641));
#1117=CARTESIAN_POINT('',(-42.4889098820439,-14.9731459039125,5.82508076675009));
#1118=CARTESIAN_POINT('',(-42.4941171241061,-14.9583612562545,5.85330770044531));
#1119=CARTESIAN_POINT('',(-42.4971052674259,-14.9498710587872,5.86677538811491));
#1120=CARTESIAN_POINT('',(-42.5038299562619,-14.930741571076,5.89240652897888));
#1121=CARTESIAN_POINT('',(-42.5075828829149,-14.9200551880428,5.9045304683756));
#1122=CARTESIAN_POINT('',(-42.5156689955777,-14.8969976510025,5.92682429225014));
#1123=CARTESIAN_POINT('',(-42.5200023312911,-14.8846260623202,5.9369936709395));
#1124=CARTESIAN_POINT('',(-42.5293703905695,-14.8578385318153,5.95567126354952));
#1125=CARTESIAN_POINT('',(-42.5344303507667,-14.8433482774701,5.96406014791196));
#1126=CARTESIAN_POINT('',(-42.5449099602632,-14.8132842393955,5.97828637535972));
#1127=CARTESIAN_POINT('',(-42.550329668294,-14.7977102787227,5.98412330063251));
#1128=CARTESIAN_POINT('',(-42.5604846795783,-14.7684746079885,5.99240923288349));
#1129=CARTESIAN_POINT('',(-42.5651884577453,-14.7549123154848,5.9952541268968));
#1130=CARTESIAN_POINT('',(-42.5746573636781,-14.7275681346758,5.99904964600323));
#1131=CARTESIAN_POINT('',(-42.5794223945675,-14.7137865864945,6.00000296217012));
#1132=CARTESIAN_POINT('',(-42.5841813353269,-14.7,6.));
#1133=B_SPLINE_CURVE_WITH_KNOTS('',3,(#1111,#1112,#1113,#1114,#1115,#1116,#1117,#1118,#1119,
#1120,#1121,#1122,#1123,#1124,#1125,#1126,#1127,#1128,#1129,#1130,#1131,#1132),.UNSPECIFIED.,
.F.,.F.,(4,2,2,2,2,2,2,2,2,2,4),(0.,0.0484894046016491,0.0968636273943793,0.145233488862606,
0.193616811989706,0.243172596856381,0.29274118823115,0.344985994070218,0.397239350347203,
0.441019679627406,0.484737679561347),.UNSPECIFIED.);
#1134=CARTESIAN_POINT('',(-42.5841813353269,-14.7,6.));
#1135=VERTEX_POINT('',#1134);
#1136=EDGE_CURVE('E1048',#1108,#1135,#1133,.T.);
#1137=ORIENTED_EDGE('',*,*,#1136,.T.);
#1138=CARTESIAN_POINT('',(-43.6402118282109,-11.1818787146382,6.));
#1139=VERTEX_POINT('',#1138);
#1140=EDGE_CURVE('E1083',#1139,#1135,#132,.T.);
#1141=ORIENTED_EDGE('',*,*,#1140,.F.);
#1142=DIRECTION('',(0.,0.,-1.));
#1143=VECTOR('',#1142,1.);
#1144=CARTESIAN_POINT('',(-43.6402118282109,-11.1818787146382,5.99999999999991));
#1145=LINE('',#1144,#1143);
#1146=CARTESIAN_POINT('',(-43.6402118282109,-11.1818787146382,1.99999999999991));
#1147=VERTEX_POINT('',#1146);
#1148=EDGE_CURVE('E1043',#1139,#1147,#1145,.T.);
#1149=ORIENTED_EDGE('',*,*,#1148,.T.);
#1150=CARTESIAN_POINT('',(0.,0.,1.99999999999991));
#1151=DIRECTION('',(0.,0.,-1.));
#1152=DIRECTION('',(-0.969798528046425,-0.243907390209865,0.));
#1153=AXIS2_PLACEMENT_3D('',#1150,#1151,#1152);
#1154=CIRCLE('',#1153,45.05);
#1155=CARTESIAN_POINT('',(-43.6894236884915,-10.9880279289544,1.99999999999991));
#1156=VERTEX_POINT('',#1155);
#1157=EDGE_CURVE('E1047',#1147,#1156,#1154,.T.);
#1158=ORIENTED_EDGE('',*,*,#1157,.T.);
#1159=DIRECTION('',(0.,0.,1.));
#1160=VECTOR('',#1159,1.);
#1161=CARTESIAN_POINT('',(-43.6894236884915,-10.9880279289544,1.99999999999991));
#1162=LINE('',#1161,#1160);
#1163=CARTESIAN_POINT('',(-43.6894236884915,-10.9880279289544,6.));
#1164=VERTEX_POINT('',#1163);
#1165=EDGE_CURVE('E1007',#1156,#1164,#1162,.T.);
#1166=ORIENTED_EDGE('',*,*,#1165,.T.);
#1167=CARTESIAN_POINT('',(-44.0520416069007,-9.42974709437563,6.));
#1168=VERTEX_POINT('',#1167);
#1169=EDGE_CURVE('E1042',#1168,#1164,#132,.T.);
#1170=ORIENTED_EDGE('',*,*,#1169,.F.);
#1171=DIRECTION('',(0.,0.,-1.));
#1172=VECTOR('',#1171,1.);
#1173=CARTESIAN_POINT('',(-44.0520416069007,-9.42974709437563,5.99999999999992));
#1174=LINE('',#1173,#1172);
#1175=CARTESIAN_POINT('',(-44.0520416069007,-9.42974709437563,1.99999999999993));
#1176=VERTEX_POINT('',#1175);
#1177=EDGE_CURVE('E1002',#1168,#1176,#1174,.T.);
#1178=ORIENTED_EDGE('',*,*,#1177,.T.);
#1179=CARTESIAN_POINT('',(0.,0.,1.99999999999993));
#1180=DIRECTION('',(0.,0.,-1.));
#1181=DIRECTION('',(-0.978767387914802,-0.204974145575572,0.));
#1182=AXIS2_PLACEMENT_3D('',#1179,#1180,#1181);
#1183=CIRCLE('',#1182,45.05);
#1184=CARTESIAN_POINT('',(-44.0934708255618,-9.23408525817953,1.99999999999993));
#1185=VERTEX_POINT('',#1184);
#1186=EDGE_CURVE('E1006',#1176,#1185,#1183,.T.);
#1187=ORIENTED_EDGE('',*,*,#1186,.T.);
#1188=DIRECTION('',(0.,0.,1.));
#1189=VECTOR('',#1188,1.);
#1190=CARTESIAN_POINT('',(-44.0934708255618,-9.23408525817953,1.99999999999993));
#1191=LINE('',#1190,#1189);
#1192=CARTESIAN_POINT('',(-44.0934708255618,-9.23408525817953,6.));
#1193=VERTEX_POINT('',#1192);
#1194=EDGE_CURVE('E966',#1185,#1193,#1191,.T.);
#1195=ORIENTED_EDGE('',*,*,#1194,.T.);
#1196=CARTESIAN_POINT('',(-44.3935538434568,-7.66256335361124,6.));
#1197=VERTEX_POINT('',#1196);
#1198=EDGE_CURVE('E1001',#1197,#1193,#132,.T.);
#1199=ORIENTED_EDGE('',*,*,#1198,.F.);
#1200=DIRECTION('',(0.,0.,-1.));
#1201=VECTOR('',#1200,1.);
#1202=CARTESIAN_POINT('',(-44.3935538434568,-7.66256335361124,5.99999999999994));
#1203=LINE('',#1202,#1201);
#1204=CARTESIAN_POINT('',(-44.3935538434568,-7.66256335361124,1.99999999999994));
#1205=VERTEX_POINT('',#1204);
#1206=EDGE_CURVE('E961',#1197,#1205,#1203,.T.);
#1207=ORIENTED_EDGE('',*,*,#1206,.T.);
#1208=CARTESIAN_POINT('',(0.,0.,1.99999999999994));
#1209=DIRECTION('',(0.,0.,-1.));
#1210=DIRECTION('',(-0.986173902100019,-0.165713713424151,0.));
#1211=AXIS2_PLACEMENT_3D('',#1208,#1209,#1210);
#1212=CIRCLE('',#1211,45.05);
#1213=CARTESIAN_POINT('',(-44.4271342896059,-7.465402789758,1.99999999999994));
#1214=VERTEX_POINT('',#1213);
#1215=EDGE_CURVE('E965',#1205,#1214,#1212,.T.);
#1216=ORIENTED_EDGE('',*,*,#1215,.T.);
#1217=DIRECTION('',(0.,0.,1.));
#1218=VECTOR('',#1217,1.);
#1219=CARTESIAN_POINT('',(-44.4271342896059,-7.465402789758,1.99999999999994));
#1220=LINE('',#1219,#1218);
#1221=CARTESIAN_POINT('',(-44.4271342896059,-7.465402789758,6.));
#1222=VERTEX_POINT('',#1221);
#1223=EDGE_CURVE('E925',#1214,#1222,#1220,.T.);
#1224=ORIENTED_EDGE('',*,*,#1223,.T.);
#1225=CARTESIAN_POINT('',(-44.6642034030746,-5.88314833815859,6.));
#1226=VERTEX_POINT('',#1225);
#1227=EDGE_CURVE('E960',#1226,#1222,#132,.T.);
#1228=ORIENTED_EDGE('',*,*,#1227,.F.);
#1229=DIRECTION('',(0.,0.,-1.));
#1230=VECTOR('',#1229,1.);
#1231=CARTESIAN_POINT('',(-44.6642034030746,-5.88314833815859,5.99999999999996));
#1232=LINE('',#1231,#1230);
#1233=CARTESIAN_POINT('',(-44.6642034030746,-5.88314833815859,1.99999999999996));
#1234=VERTEX_POINT('',#1233);
#1235=EDGE_CURVE('E920',#1226,#1234,#1232,.T.);
#1236=ORIENTED_EDGE('',*,*,#1235,.T.);
#1237=CARTESIAN_POINT('',(0.,0.,1.99999999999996));
#1238=DIRECTION('',(0.,0.,-1.));
#1239=DIRECTION('',(-0.992006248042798,-0.126188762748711,0.));
#1240=AXIS2_PLACEMENT_3D('',#1237,#1238,#1239);
#1241=CIRCLE('',#1240,45.05);
#1242=CARTESIAN_POINT('',(-44.6898814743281,-5.68480376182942,1.99999999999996));
#1243=VERTEX_POINT('',#1242);
#1244=EDGE_CURVE('E924',#1234,#1243,#1241,.T.);
#1245=ORIENTED_EDGE('',*,*,#1244,.T.);
#1246=DIRECTION('',(0.,0.,1.));
#1247=VECTOR('',#1246,1.);
#1248=CARTESIAN_POINT('',(-44.6898814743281,-5.68480376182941,1.99999999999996));
#1249=LINE('',#1248,#1247);
#1250=CARTESIAN_POINT('',(-44.6898814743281,-5.68480376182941,6.));
#1251=VERTEX_POINT('',#1250);
#1252=EDGE_CURVE('E883',#1243,#1251,#1249,.T.);
#1253=ORIENTED_EDGE('',*,*,#1252,.T.);
#1254=CARTESIAN_POINT('',(-44.8635582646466,-4.09434241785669,6.));
#1255=VERTEX_POINT('',#1254);
#1256=EDGE_CURVE('E919',#1255,#1251,#132,.T.);
#1257=ORIENTED_EDGE('',*,*,#1256,.F.);
#1258=DIRECTION('',(0.,0.,-1.));
#1259=VECTOR('',#1258,1.);
#1260=CARTESIAN_POINT('',(-44.8635582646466,-4.09434241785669,5.99999999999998));
#1261=LINE('',#1260,#1259);
#1262=CARTESIAN_POINT('',(-44.8635582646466,-4.09434241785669,1.99999999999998));
#1263=VERTEX_POINT('',#1262);
#1264=EDGE_CURVE('E878',#1255,#1263,#1261,.T.);
#1265=ORIENTED_EDGE('',*,*,#1264,.T.);
#1266=CARTESIAN_POINT('',(0.,0.,1.99999999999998));
#1267=DIRECTION('',(0.,0.,-1.));
#1268=DIRECTION('',(-0.996255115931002,-0.0864623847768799,0.));
#1269=AXIS2_PLACEMENT_3D('',#1266,#1267,#1268);
#1270=CIRCLE('',#1269,45.05);
#1271=CARTESIAN_POINT('',(-44.8812929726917,-3.89513043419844,1.99999999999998));
#1272=VERTEX_POINT('',#1271);
#1273=EDGE_CURVE('E882',#1263,#1272,#1270,.T.);
#1274=ORIENTED_EDGE('',*,*,#1273,.T.);
#1275=DIRECTION('',(0.,0.,1.));
#1276=VECTOR('',#1275,1.);
#1277=CARTESIAN_POINT('',(-44.8812929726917,-3.89513043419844,1.99999999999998));
#1278=LINE('',#1277,#1276);
#1279=CARTESIAN_POINT('',(-44.8812929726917,-3.89513043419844,6.));
#1280=VERTEX_POINT('',#1279);
#1281=EDGE_CURVE('E887',#1272,#1280,#1278,.T.);
#1282=ORIENTED_EDGE('',*,*,#1281,.T.);
#1283=CARTESIAN_POINT('',(-44.9913002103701,-2.29900095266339,6.));
#1284=VERTEX_POINT('',#1283);
#1285=EDGE_CURVE('E797',#1284,#1280,#132,.T.);
#1286=ORIENTED_EDGE('',*,*,#1285,.F.);
#1287=DIRECTION('',(0.,0.,-1.));
#1288=VECTOR('',#1287,1.);
#1289=CARTESIAN_POINT('',(-44.9913002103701,-2.29900095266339,6.));
#1290=LINE('',#1289,#1288);
#1291=EDGE_CURVE('E694',#1284,#982,#1290,.T.);
#1292=ORIENTED_EDGE('',*,*,#1291,.T.);
#1293=EDGE_LOOP('',(#986,#994,#998,#1025,#1033,#1060,#1062,#1071,#1075,#1102,#1110,#1137,#1141,
#1149,#1158,#1166,#1170,#1178,#1187,#1195,#1199,#1207,#1216,#1224,#1228,#1236,#1245,#1253,#1257,
#1265,#1274,#1282,#1286,#1292));
#1294=FACE_BOUND('',#1293,.T.);
#1295=ADVANCED_FACE('F763',(#975,#1294),#23,.T.);
#1296=CARTESIAN_POINT('',(-42.4794362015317,-15.,6.));
#1297=DIRECTION('',(0.,1.,0.));
#1298=DIRECTION('',(0.,0.,1.));
#1299=AXIS2_PLACEMENT_3D('',#1296,#1297,#1298);
#1300=PLANE('',#1299);
#1301=ORIENTED_EDGE('',*,*,#817,.F.);
#1302=DIRECTION('',(1.,0.,0.));
#1303=VECTOR('',#1302,1.);
#1304=CARTESIAN_POINT('',(-42.4794362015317,-15.,5.7));
#1305=LINE('',#1304,#1303);
#1306=EDGE_CURVE('E1374',#808,#1108,#1305,.F.);
#1307=ORIENTED_EDGE('',*,*,#1306,.T.);
#1308=ORIENTED_EDGE('',*,*,#1109,.T.);
#1309=DIRECTION('',(1.,0.,0.));
#1310=VECTOR('',#1309,1.);
#1311=CARTESIAN_POINT('',(-42.4794362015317,-15.,0.3));
#1312=LINE('',#1311,#1310);
#1313=EDGE_CURVE('E1373',#1100,#816,#1312,.T.);
#1314=ORIENTED_EDGE('',*,*,#1313,.T.);
#1315=EDGE_LOOP('',(#1301,#1307,#1308,#1314));
#1316=FACE_BOUND('',#1315,.T.);
#1317=ADVANCED_FACE('F1399',(#1316),#1300,.F.);
#1318=ORIENTED_EDGE('',*,*,#782,.T.);
#1319=DIRECTION('',(1.,0.,0.));
#1320=VECTOR('',#1319,1.);
#1321=CARTESIAN_POINT('',(-45.0365684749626,-1.4,6.));
#1322=LINE('',#1321,#1320);
#1323=EDGE_CURVE('E1516',#777,#996,#1322,.F.);
#1324=ORIENTED_EDGE('',*,*,#1323,.T.);
#1325=ORIENTED_EDGE('',*,*,#997,.T.);
#1326=DIRECTION('',(0.998913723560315,0.0465979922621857,0.));
#1327=VECTOR('',#1326,1.);
#1328=CARTESIAN_POINT('',(-45.0010632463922,-2.09923955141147,6.));
#1329=LINE('',#1328,#1327);
#1330=CARTESIAN_POINT('',(-45.0110523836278,-2.09970553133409,6.));
#1331=VERTEX_POINT('',#1330);
#1332=EDGE_CURVE('E756',#1331,#992,#1329,.T.);
#1333=ORIENTED_EDGE('',*,*,#1332,.F.);
#1334=CARTESIAN_POINT('',(0.,0.,6.));
#1335=DIRECTION('',(0.,0.,-1.));
#1336=DIRECTION('',(-1.,0.,0.));
#1337=AXIS2_PLACEMENT_3D('',#1334,#1335,#1336);
#1338=CIRCLE('',#1337,45.06);
#1339=CARTESIAN_POINT('',(-45.0012871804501,-2.29951127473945,6.));
#1340=VERTEX_POINT('',#1339);
#1341=EDGE_CURVE('E775',#1331,#1340,#1338,.F.);
#1342=ORIENTED_EDGE('',*,*,#1341,.T.);
#1343=DIRECTION('',(0.998697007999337,0.0510322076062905,0.));
#1344=VECTOR('',#1343,1.);
#1345=CARTESIAN_POINT('',(-44.9913002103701,-2.29900095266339,6.));
#1346=LINE('',#1345,#1344);
#1347=EDGE_CURVE('E779',#1340,#1284,#1346,.T.);
#1348=ORIENTED_EDGE('',*,*,#1347,.T.);
#1349=ORIENTED_EDGE('',*,*,#1285,.T.);
#1350=DIRECTION('',(0.996255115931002,0.0864623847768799,0.));
#1351=VECTOR('',#1350,1.);
#1352=CARTESIAN_POINT('',(-44.8812929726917,-3.89513043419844,6.));
#1353=LINE('',#1352,#1351);
#1354=CARTESIAN_POINT('',(-44.891255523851,-3.89599505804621,6.));
#1355=VERTEX_POINT('',#1354);
#1356=EDGE_CURVE('E900',#1355,#1280,#1353,.T.);
#1357=ORIENTED_EDGE('',*,*,#1356,.F.);
#1358=CARTESIAN_POINT('',(0.,0.,6.));
#1359=DIRECTION('',(0.,0.,-1.));
#1360=DIRECTION('',(-1.,0.,0.));
#1361=AXIS2_PLACEMENT_3D('',#1358,#1359,#1360);
#1362=CIRCLE('',#1361,45.06);
#1363=CARTESIAN_POINT('',(-44.8735168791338,-4.09525126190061,6.));
#1364=VERTEX_POINT('',#1363);
#1365=EDGE_CURVE('E891',#1355,#1364,#1362,.F.);
#1366=ORIENTED_EDGE('',*,*,#1365,.T.);
#1367=DIRECTION('',(0.995861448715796,0.0908844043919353,0.));
#1368=VECTOR('',#1367,1.);
#1369=CARTESIAN_POINT('',(-44.8635582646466,-4.09434241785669,6.));
#1370=LINE('',#1369,#1368);
#1371=EDGE_CURVE('E895',#1364,#1255,#1370,.T.);
#1372=ORIENTED_EDGE('',*,*,#1371,.T.);
#1373=ORIENTED_EDGE('',*,*,#1256,.T.);
#1374=DIRECTION('',(0.992006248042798,0.126188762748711,0.));
#1375=VECTOR('',#1374,1.);
#1376=CARTESIAN_POINT('',(-44.6898814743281,-5.68480376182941,6.));
#1377=LINE('',#1376,#1375);
#1378=CARTESIAN_POINT('',(-44.6998015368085,-5.6860656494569,6.));
#1379=VERTEX_POINT('',#1378);
#1380=EDGE_CURVE('E941',#1379,#1251,#1377,.T.);
#1381=ORIENTED_EDGE('',*,*,#1380,.F.);
#1382=CARTESIAN_POINT('',(0.,0.,6.));
#1383=DIRECTION('',(0.,0.,-1.));
#1384=DIRECTION('',(-1.,0.,0.));
#1385=AXIS2_PLACEMENT_3D('',#1382,#1383,#1384);
#1386=CIRCLE('',#1385,45.06);
#1387=CARTESIAN_POINT('',(-44.6741177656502,-5.88445425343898,6.));
#1388=VERTEX_POINT('',#1387);
#1389=EDGE_CURVE('E932',#1379,#1388,#1386,.F.);
#1390=ORIENTED_EDGE('',*,*,#1389,.T.);
#1391=DIRECTION('',(0.991436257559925,0.130591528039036,0.));
#1392=VECTOR('',#1391,1.);
#1393=CARTESIAN_POINT('',(-44.6642034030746,-5.88314833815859,6.));
#1394=LINE('',#1393,#1392);
#1395=EDGE_CURVE('E936',#1388,#1226,#1394,.T.);
#1396=ORIENTED_EDGE('',*,*,#1395,.T.);
#1397=ORIENTED_EDGE('',*,*,#1227,.T.);
#1398=DIRECTION('',(0.986173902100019,0.165713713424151,0.));
#1399=VECTOR('',#1398,1.);
#1400=CARTESIAN_POINT('',(-44.4271342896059,-7.465402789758,6.));
#1401=LINE('',#1400,#1399);
#1402=CARTESIAN_POINT('',(-44.4369960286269,-7.46705992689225,6.));
#1403=VERTEX_POINT('',#1402);
#1404=EDGE_CURVE('E982',#1403,#1222,#1401,.T.);
#1405=ORIENTED_EDGE('',*,*,#1404,.F.);
#1406=CARTESIAN_POINT('',(0.,0.,6.));
#1407=DIRECTION('',(0.,0.,-1.));
#1408=DIRECTION('',(-1.,0.,0.));
#1409=AXIS2_PLACEMENT_3D('',#1406,#1407,#1408);
#1410=CIRCLE('',#1409,45.06);
#1411=CARTESIAN_POINT('',(-44.4034081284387,-7.66426425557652,6.));
#1412=VERTEX_POINT('',#1411);
#1413=EDGE_CURVE('E973',#1403,#1412,#1410,.F.);
#1414=ORIENTED_EDGE('',*,*,#1413,.T.);
#1415=DIRECTION('',(0.985428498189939,0.170090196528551,0.));
#1416=VECTOR('',#1415,1.);
#1417=CARTESIAN_POINT('',(-44.3935538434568,-7.66256335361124,6.));
#1418=LINE('',#1417,#1416);
#1419=EDGE_CURVE('E977',#1412,#1197,#1418,.T.);
#1420=ORIENTED_EDGE('',*,*,#1419,.T.);
#1421=ORIENTED_EDGE('',*,*,#1198,.T.);
#1422=DIRECTION('',(0.978767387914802,0.204974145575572,0.));
#1423=VECTOR('',#1422,1.);
#1424=CARTESIAN_POINT('',(-44.0934708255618,-9.23408525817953,6.));
#1425=LINE('',#1424,#1423);
#1426=CARTESIAN_POINT('',(-44.103258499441,-9.23613499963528,6.));
#1427=VERTEX_POINT('',#1426);
#1428=EDGE_CURVE('E1023',#1427,#1193,#1425,.T.);
#1429=ORIENTED_EDGE('',*,*,#1428,.F.);
#1430=CARTESIAN_POINT('',(0.,0.,6.));
#1431=DIRECTION('',(0.,0.,-1.));
#1432=DIRECTION('',(-1.,0.,0.));
#1433=AXIS2_PLACEMENT_3D('',#1430,#1431,#1432);
#1434=CIRCLE('',#1433,45.06);
#1435=CARTESIAN_POINT('',(-44.0618200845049,-9.43184026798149,6.));
#1436=VERTEX_POINT('',#1435);
#1437=EDGE_CURVE('E1014',#1427,#1436,#1434,.F.);
#1438=ORIENTED_EDGE('',*,*,#1437,.T.);
#1439=DIRECTION('',(0.97784776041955,0.209317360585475,0.));
#1440=VECTOR('',#1439,1.);
#1441=CARTESIAN_POINT('',(-44.0520416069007,-9.42974709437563,6.));
#1442=LINE('',#1441,#1440);
#1443=EDGE_CURVE('E1018',#1436,#1168,#1442,.T.);
#1444=ORIENTED_EDGE('',*,*,#1443,.T.);
#1445=ORIENTED_EDGE('',*,*,#1169,.T.);
#1446=DIRECTION('',(0.969798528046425,0.243907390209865,0.));
#1447=VECTOR('',#1446,1.);
#1448=CARTESIAN_POINT('',(-43.6894236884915,-10.9880279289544,6.));
#1449=LINE('',#1448,#1447);
#1450=CARTESIAN_POINT('',(-43.6991216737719,-10.9904670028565,6.));
#1451=VERTEX_POINT('',#1450);
#1452=EDGE_CURVE('E1064',#1451,#1164,#1449,.T.);
#1453=ORIENTED_EDGE('',*,*,#1452,.F.);
#1454=CARTESIAN_POINT('',(0.,0.,6.));
#1455=DIRECTION('',(0.,0.,-1.));
#1456=DIRECTION('',(-1.,0.,0.));
#1457=AXIS2_PLACEMENT_3D('',#1454,#1455,#1456);
#1458=CIRCLE('',#1457,45.06);
#1459=CARTESIAN_POINT('',(-43.64989888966,-11.1843608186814,6.));
#1460=VERTEX_POINT('',#1459);
#1461=EDGE_CURVE('E1055',#1451,#1460,#1458,.F.);
#1462=ORIENTED_EDGE('',*,*,#1461,.T.);
#1463=DIRECTION('',(0.968706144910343,0.248210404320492,0.));
#1464=VECTOR('',#1463,1.);
#1465=CARTESIAN_POINT('',(-43.6402118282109,-11.1818787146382,6.));
#1466=LINE('',#1465,#1464);
#1467=EDGE_CURVE('E1059',#1460,#1139,#1466,.T.);
#1468=ORIENTED_EDGE('',*,*,#1467,.T.);
#1469=ORIENTED_EDGE('',*,*,#1140,.T.);
#1470=DIRECTION('',(1.,0.,0.));
#1471=VECTOR('',#1470,1.);
#1472=CARTESIAN_POINT('',(-42.4264068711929,-14.7,6.));
#1473=LINE('',#1472,#1471);
#1474=EDGE_CURVE('E1506',#1135,#781,#1473,.T.);
#1475=ORIENTED_EDGE('',*,*,#1474,.T.);
#1476=EDGE_LOOP('',(#1318,#1324,#1325,#1333,#1342,#1348,#1349,#1357,#1366,#1372,#1373,#1381,
#1390,#1396,#1397,#1405,#1414,#1420,#1421,#1429,#1438,#1444,#1445,#1453,#1462,#1468,#1469,#1475));
#1477=FACE_BOUND('',#1476,.T.);
#1478=ADVANCED_FACE('F1600',(#1477),#469,.T.);
#1479=CARTESIAN_POINT('',(0.,0.,0.));
#1480=DIRECTION('',(0.,0.,1.));
#1481=DIRECTION('',(1.,0.,0.));
#1482=AXIS2_PLACEMENT_3D('',#1479,#1480,#1481);
#1483=PLANE('',#1482);
#1484=ORIENTED_EDGE('',*,*,#853,.F.);
#1485=DIRECTION('',(1.,0.,0.));
#1486=VECTOR('',#1485,1.);
#1487=CARTESIAN_POINT('',(0.,-14.7,0.));
#1488=LINE('',#1487,#1486);
#1489=EDGE_CURVE('E1502',#843,#1073,#1488,.F.);
#1490=ORIENTED_EDGE('',*,*,#1489,.T.);
#1491=ORIENTED_EDGE('',*,*,#1074,.F.);
#1492=CARTESIAN_POINT('',(-44.9694014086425,-2.85596515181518,0.));
#1493=CARTESIAN_POINT('',(-44.9594215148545,-2.85533133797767,0.));
#1494=B_SPLINE_CURVE_WITH_KNOTS('',1,(#1492,#1493),.UNSPECIFIED.,.F.,.F.,(2,2),(0.,1.),.UNSPECIFIED.);
#1495=CARTESIAN_POINT('',(-44.9694014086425,-2.85596515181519,0.));
#1496=VERTEX_POINT('',#1495);
#1497=EDGE_CURVE('E1326',#1496,#1069,#1494,.T.);
#1498=ORIENTED_EDGE('',*,*,#1497,.F.);
#1499=CARTESIAN_POINT('',(0.,0.,0.));
#1500=DIRECTION('',(0.,0.,-1.));
#1501=DIRECTION('',(-1.,0.,0.));
#1502=AXIS2_PLACEMENT_3D('',#1499,#1500,#1501);
#1503=CIRCLE('',#1502,45.06);
#1504=CARTESIAN_POINT('',(-44.950398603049,3.14090200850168,0.));
#1505=VERTEX_POINT('',#1504);
#1506=EDGE_CURVE('E1259',#1505,#1496,#1503,.F.);
#1507=ORIENTED_EDGE('',*,*,#1506,.F.);
#1508=CARTESIAN_POINT('',(-44.9404229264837,3.14020495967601,0.));
#1509=CARTESIAN_POINT('',(-44.950398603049,3.14090200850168,0.));
#1510=B_SPLINE_CURVE_WITH_KNOTS('',1,(#1508,#1509),.UNSPECIFIED.,.F.,.F.,(2,2),(0.,1.),.UNSPECIFIED.);
#1511=EDGE_CURVE('E1505',#1505,#381,#1510,.F.);
#1512=ORIENTED_EDGE('',*,*,#1511,.T.);
#1513=ORIENTED_EDGE('',*,*,#382,.F.);
#1514=DIRECTION('',(-1.,0.,0.));
#1515=VECTOR('',#1514,1.);
#1516=CARTESIAN_POINT('',(0.,14.7,0.));
#1517=LINE('',#1516,#1515);
#1518=EDGE_CURVE('E1507',#372,#852,#1517,.F.);
#1519=ORIENTED_EDGE('',*,*,#1518,.T.);
#1520=EDGE_LOOP('',(#1484,#1490,#1491,#1498,#1507,#1512,#1513,#1519));
#1521=FACE_BOUND('',#1520,.T.);
#1522=ADVANCED_FACE('F2794',(#1521),#1483,.F.);
#1523=CARTESIAN_POINT('',(-45.05,-1.1,2.));
#1524=DIRECTION('',(0.,0.,-1.));
#1525=DIRECTION('',(-1.,0.,0.));
#1526=AXIS2_PLACEMENT_3D('',#1523,#1524,#1525);
#1527=PLANE('',#1526);
#1528=ORIENTED_EDGE('',*,*,#1061,.F.);
#1529=DIRECTION('',(1.,0.,0.));
#1530=VECTOR('',#1529,1.);
#1531=CARTESIAN_POINT('',(-44.9865535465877,-0.8,2.));
#1532=LINE('',#1531,#1530);
#1533=EDGE_CURVE('E1510',#1058,#715,#1532,.T.);
#1534=ORIENTED_EDGE('',*,*,#1533,.T.);
#1535=ORIENTED_EDGE('',*,*,#716,.F.);
#1536=DIRECTION('',(1.,0.,0.));
#1537=VECTOR('',#1536,1.);
#1538=CARTESIAN_POINT('',(-45.0365684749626,0.8,2.));
#1539=LINE('',#1538,#1537);
#1540=EDGE_CURVE('E1358',#706,#399,#1539,.F.);
#1541=ORIENTED_EDGE('',*,*,#1540,.T.);
#1542=ORIENTED_EDGE('',*,*,#400,.F.);
#1543=EDGE_LOOP('',(#1528,#1534,#1535,#1541,#1542));
#1544=FACE_BOUND('',#1543,.T.);
#1545=ADVANCED_FACE('F2784',(#1544),#1527,.F.);
#1546=CARTESIAN_POINT('',(-45.05,1.1,2.));
#1547=DIRECTION('',(0.,1.,0.));
#1548=DIRECTION('',(0.,0.,1.));
#1549=AXIS2_PLACEMENT_3D('',#1546,#1547,#1548);
#1550=PLANE('',#1549);
#1551=ORIENTED_EDGE('',*,*,#435,.F.);
#1552=DIRECTION('',(1.,0.,0.));
#1553=VECTOR('',#1552,1.);
#1554=CARTESIAN_POINT('',(-44.9865535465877,1.1,2.3));
#1555=LINE('',#1554,#1553);
#1556=EDGE_CURVE('E2904',#426,#679,#1555,.T.);
#1557=ORIENTED_EDGE('',*,*,#1556,.T.);
#1558=ORIENTED_EDGE('',*,*,#680,.F.);
#1559=DIRECTION('',(-1.,0.,0.));
#1560=VECTOR('',#1559,1.);
#1561=CARTESIAN_POINT('',(-45.0365684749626,1.1,5.7));
#1562=LINE('',#1561,#1560);
#1563=EDGE_CURVE('E2901',#671,#434,#1562,.T.);
#1564=ORIENTED_EDGE('',*,*,#1563,.T.);
#1565=EDGE_LOOP('',(#1551,#1557,#1558,#1564));
#1566=FACE_BOUND('',#1565,.T.);
#1567=ADVANCED_FACE('F2774',(#1566),#1550,.F.);
#1568=CARTESIAN_POINT('',(-45.05,-1.1,6.));
#1569=DIRECTION('',(0.,-1.,0.));
#1570=DIRECTION('',(0.,0.,-1.));
#1571=AXIS2_PLACEMENT_3D('',#1568,#1569,#1570);
#1572=PLANE('',#1571);
#1573=ORIENTED_EDGE('',*,*,#751,.F.);
#1574=DIRECTION('',(1.,0.,0.));
#1575=VECTOR('',#1574,1.);
#1576=CARTESIAN_POINT('',(-45.0365684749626,-1.1,2.3));
#1577=LINE('',#1576,#1575);
#1578=EDGE_CURVE('E2903',#742,#1031,#1577,.F.);
#1579=ORIENTED_EDGE('',*,*,#1578,.T.);
#1580=ORIENTED_EDGE('',*,*,#1032,.F.);
#1581=DIRECTION('',(1.,0.,0.));
#1582=VECTOR('',#1581,1.);
#1583=CARTESIAN_POINT('',(-44.9865535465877,-1.1,5.7));
#1584=LINE('',#1583,#1582);
#1585=EDGE_CURVE('E2906',#1023,#750,#1584,.T.);
#1586=ORIENTED_EDGE('',*,*,#1585,.T.);
#1587=EDGE_LOOP('',(#1573,#1579,#1580,#1586));
#1588=FACE_BOUND('',#1587,.T.);
#1589=ADVANCED_FACE('F1482',(#1588),#1572,.F.);
#1590=CARTESIAN_POINT('',(-45.05,-0.8,2.3));
#1591=DIRECTION('',(-1.,0.,0.));
#1592=DIRECTION('',(0.,0.,1.));
#1593=AXIS2_PLACEMENT_3D('',#1590,#1591,#1592);
#1594=CYLINDRICAL_SURFACE('',#1593,0.3);
#1595=ORIENTED_EDGE('',*,*,#1059,.F.);
#1596=ORIENTED_EDGE('',*,*,#1578,.F.);
#1597=ORIENTED_EDGE('',*,*,#743,.F.);
#1598=ORIENTED_EDGE('',*,*,#1533,.F.);
#1599=EDGE_LOOP('',(#1595,#1596,#1597,#1598));
#1600=FACE_BOUND('',#1599,.T.);
#1601=ADVANCED_FACE('F1476',(#1600),#1594,.F.);
#1602=CARTESIAN_POINT('',(-45.05,0.8,2.3));
#1603=DIRECTION('',(-1.,0.,0.));
#1604=DIRECTION('',(0.,0.,1.));
#1605=AXIS2_PLACEMENT_3D('',#1602,#1603,#1604);
#1606=CYLINDRICAL_SURFACE('',#1605,0.3);
#1607=ORIENTED_EDGE('',*,*,#427,.F.);
#1608=ORIENTED_EDGE('',*,*,#1540,.F.);
#1609=ORIENTED_EDGE('',*,*,#707,.F.);
#1610=ORIENTED_EDGE('',*,*,#1556,.F.);
#1611=EDGE_LOOP('',(#1607,#1608,#1609,#1610));
#1612=FACE_BOUND('',#1611,.T.);
#1613=ADVANCED_FACE('F1472',(#1612),#1606,.F.);
#1614=CARTESIAN_POINT('',(-45.05,1.4,5.7));
#1615=DIRECTION('',(1.,0.,0.));
#1616=DIRECTION('',(0.,0.,-1.));
#1617=AXIS2_PLACEMENT_3D('',#1614,#1615,#1616);
#1618=CYLINDRICAL_SURFACE('',#1617,0.3);
#1619=ORIENTED_EDGE('',*,*,#672,.F.);
#1620=ORIENTED_EDGE('',*,*,#621,.F.);
#1621=ORIENTED_EDGE('',*,*,#460,.F.);
#1622=ORIENTED_EDGE('',*,*,#1563,.F.);
#1623=EDGE_LOOP('',(#1619,#1620,#1621,#1622));
#1624=FACE_BOUND('',#1623,.T.);
#1625=ADVANCED_FACE('F1475',(#1624),#1618,.T.);
#1626=CARTESIAN_POINT('',(-45.05,-1.4,5.7));
#1627=DIRECTION('',(-1.,0.,0.));
#1628=DIRECTION('',(0.,0.,1.));
#1629=AXIS2_PLACEMENT_3D('',#1626,#1627,#1628);
#1630=CYLINDRICAL_SURFACE('',#1629,0.3);
#1631=ORIENTED_EDGE('',*,*,#1024,.F.);
#1632=ORIENTED_EDGE('',*,*,#1323,.F.);
#1633=ORIENTED_EDGE('',*,*,#778,.F.);
#1634=ORIENTED_EDGE('',*,*,#1585,.F.);
#1635=EDGE_LOOP('',(#1631,#1632,#1633,#1634));
#1636=FACE_BOUND('',#1635,.T.);
#1637=ADVANCED_FACE('F1542',(#1636),#1630,.T.);
#1638=CARTESIAN_POINT('',(0.,-14.7,5.7));
#1639=DIRECTION('',(-1.,0.,0.));
#1640=DIRECTION('',(0.,0.,1.));
#1641=AXIS2_PLACEMENT_3D('',#1638,#1639,#1640);
#1642=CYLINDRICAL_SURFACE('',#1641,0.3);
#1643=ORIENTED_EDGE('',*,*,#1136,.F.);
#1644=ORIENTED_EDGE('',*,*,#1306,.F.);
#1645=ORIENTED_EDGE('',*,*,#809,.F.);
#1646=ORIENTED_EDGE('',*,*,#1474,.F.);
#1647=EDGE_LOOP('',(#1643,#1644,#1645,#1646));
#1648=FACE_BOUND('',#1647,.T.);
#1649=ADVANCED_FACE('F1545',(#1648),#1642,.T.);
#1650=CARTESIAN_POINT('',(-42.4794362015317,-14.7,0.3));
#1651=DIRECTION('',(1.,0.,0.));
#1652=DIRECTION('',(0.,0.,-1.));
#1653=AXIS2_PLACEMENT_3D('',#1650,#1651,#1652);
#1654=CYLINDRICAL_SURFACE('',#1653,0.3);
#1655=ORIENTED_EDGE('',*,*,#1101,.F.);
#1656=ORIENTED_EDGE('',*,*,#1489,.F.);
#1657=ORIENTED_EDGE('',*,*,#844,.F.);
#1658=ORIENTED_EDGE('',*,*,#1313,.F.);
#1659=EDGE_LOOP('',(#1655,#1656,#1657,#1658));
#1660=FACE_BOUND('',#1659,.T.);
#1661=ADVANCED_FACE('F1550',(#1660),#1654,.T.);
#1662=CARTESIAN_POINT('',(0.,14.7,5.7));
#1663=DIRECTION('',(1.,0.,0.));
#1664=DIRECTION('',(0.,0.,-1.));
#1665=AXIS2_PLACEMENT_3D('',#1662,#1663,#1664);
#1666=CYLINDRICAL_SURFACE('',#1665,0.3);
#1667=ORIENTED_EDGE('',*,*,#913,.F.);
#1668=ORIENTED_EDGE('',*,*,#928,.F.);
#1669=ORIENTED_EDGE('',*,*,#338,.F.);
#1670=ORIENTED_EDGE('',*,*,#636,.F.);
#1671=EDGE_LOOP('',(#1667,#1668,#1669,#1670));
#1672=FACE_BOUND('',#1671,.T.);
#1673=ADVANCED_FACE('F1555',(#1672),#1666,.T.);
#1674=CARTESIAN_POINT('',(-42.4794362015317,14.7,0.3));
#1675=DIRECTION('',(-1.,0.,0.));
#1676=DIRECTION('',(0.,0.,1.));
#1677=AXIS2_PLACEMENT_3D('',#1674,#1675,#1676);
#1678=CYLINDRICAL_SURFACE('',#1677,0.3);
#1679=ORIENTED_EDGE('',*,*,#880,.F.);
#1680=ORIENTED_EDGE('',*,*,#1518,.F.);
#1681=ORIENTED_EDGE('',*,*,#373,.F.);
#1682=ORIENTED_EDGE('',*,*,#935,.F.);
#1683=EDGE_LOOP('',(#1679,#1680,#1681,#1682));
#1684=FACE_BOUND('',#1683,.T.);
#1685=ADVANCED_FACE('F1579',(#1684),#1678,.T.);
#1686=CARTESIAN_POINT('',(-44.950398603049,3.14090200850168,0.));
#1687=CARTESIAN_POINT('',(-45.0201189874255,2.14311250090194,0.666666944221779));
#1688=CARTESIAN_POINT('',(-45.0566042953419,1.14300227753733,1.33333305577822));
#1689=CARTESIAN_POINT('',(-45.0597737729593,0.142784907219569,2.));
#1690=CARTESIAN_POINT('',(-44.9404229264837,3.14020495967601,0.));
#1691=CARTESIAN_POINT('',(-45.010127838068,2.14263688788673,0.666666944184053));
#1692=CARTESIAN_POINT('',(-45.0466050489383,1.14274861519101,1.33333305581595));
#1693=CARTESIAN_POINT('',(-45.049773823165,0.142753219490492,2.));
#1694=B_SPLINE_SURFACE_WITH_KNOTS('',1,3,((#1686,#1687,#1688,#1689),(#1690,#1691,#1692,#1693)),
.UNSPECIFIED.,.F.,.F.,.F.,(2,2),(4,4),(0.,1.),(0.,1.),.UNSPECIFIED.);
#1695=CARTESIAN_POINT('',(-44.950398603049,3.14090200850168,0.));
#1696=CARTESIAN_POINT('',(-45.0201189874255,2.14311250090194,0.666666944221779));
#1697=CARTESIAN_POINT('',(-45.0566042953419,1.14300227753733,1.33333305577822));
#1698=CARTESIAN_POINT('',(-45.0597737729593,0.142784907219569,2.));
#1699=B_SPLINE_CURVE_WITH_KNOTS('',3,(#1695,#1696,#1697,#1698),.UNSPECIFIED.,.F.,.F.,(4,4),(0.,
1.),.UNSPECIFIED.);
#1700=CARTESIAN_POINT('',(-45.0597737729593,0.142784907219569,2.));
#1701=VERTEX_POINT('',#1700);
#1702=EDGE_CURVE('E1294',#1505,#1701,#1699,.T.);
#1703=CARTESIAN_POINT('',(-45.0597737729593,0.142784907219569,2.));
#1704=CARTESIAN_POINT('',(-45.049773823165,0.142753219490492,2.));
#1705=B_SPLINE_CURVE_WITH_KNOTS('',1,(#1703,#1704),.UNSPECIFIED.,.F.,.F.,(2,2),(0.,1.),.UNSPECIFIED.);
#1706=EDGE_CURVE('E1322',#1701,#390,#1705,.T.);
#1707=ORIENTED_EDGE('',*,*,#1511,.F.);
#1708=ORIENTED_EDGE('',*,*,#1702,.T.);
#1709=ORIENTED_EDGE('',*,*,#1706,.T.);
#1710=ORIENTED_EDGE('',*,*,#391,.F.);
#1711=EDGE_LOOP('',(#1707,#1708,#1709,#1710));
#1712=FACE_BOUND('',#1711,.T.);
#1713=ADVANCED_FACE('F1582',(#1712),#1694,.F.);
#1714=CARTESIAN_POINT('',(-45.0597737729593,0.142784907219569,2.));
#1715=CARTESIAN_POINT('',(-45.0629432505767,-0.857432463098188,1.33333305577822));
#1716=CARTESIAN_POINT('',(-45.0327968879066,-1.85775382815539,0.666666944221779));
#1717=CARTESIAN_POINT('',(-44.9694014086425,-2.85596515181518,0.));
#1718=CARTESIAN_POINT('',(-45.049773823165,0.142753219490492,2.));
#1719=CARTESIAN_POINT('',(-45.0529425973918,-0.857242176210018,1.33333305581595));
#1720=CARTESIAN_POINT('',(-45.0228029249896,-1.85734154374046,0.666666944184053));
#1721=CARTESIAN_POINT('',(-44.9594215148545,-2.85533133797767,0.));
#1722=B_SPLINE_SURFACE_WITH_KNOTS('',1,3,((#1714,#1715,#1716,#1717),(#1718,#1719,#1720,#1721)),
.UNSPECIFIED.,.F.,.F.,.F.,(2,2),(4,4),(0.,1.),(0.,1.),.UNSPECIFIED.);
#1723=CARTESIAN_POINT('',(-45.0597737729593,0.142784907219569,2.));
#1724=CARTESIAN_POINT('',(-45.0629432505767,-0.857432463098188,1.33333305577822));
#1725=CARTESIAN_POINT('',(-45.0327968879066,-1.85775382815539,0.666666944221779));
#1726=CARTESIAN_POINT('',(-44.9694014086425,-2.85596515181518,0.));
#1727=B_SPLINE_CURVE_WITH_KNOTS('',3,(#1723,#1724,#1725,#1726),.UNSPECIFIED.,.F.,.F.,(4,4),(0.,
1.),.UNSPECIFIED.);
#1728=EDGE_CURVE('E1253',#1701,#1496,#1727,.T.);
#1729=ORIENTED_EDGE('',*,*,#1706,.F.);
#1730=ORIENTED_EDGE('',*,*,#1728,.T.);
#1731=ORIENTED_EDGE('',*,*,#1497,.T.);
#1732=ORIENTED_EDGE('',*,*,#1070,.F.);
#1733=EDGE_LOOP('',(#1729,#1730,#1731,#1732));
#1734=FACE_BOUND('',#1733,.T.);
#1735=ADVANCED_FACE('F1272',(#1734),#1722,.F.);
#1736=CARTESIAN_POINT('',(0.,0.,6.));
#1737=DIRECTION('',(0.,0.,-1.));
#1738=DIRECTION('',(-1.,0.,0.));
#1739=AXIS2_PLACEMENT_3D('',#1736,#1737,#1738);
#1740=CYLINDRICAL_SURFACE('',#1739,45.06);
#1741=ORIENTED_EDGE('',*,*,#1728,.F.);
#1742=ORIENTED_EDGE('',*,*,#1702,.F.);
#1743=ORIENTED_EDGE('',*,*,#1506,.T.);
#1744=EDGE_LOOP('',(#1741,#1742,#1743));
#1745=FACE_BOUND('',#1744,.T.);
#1746=ADVANCED_FACE('F1261',(#1745),#1740,.T.);
#1747=CARTESIAN_POINT('',(0.,0.,3.45));
#1748=DIRECTION('',(0.,0.,1.));
#1749=DIRECTION('',(1.,0.,0.));
#1750=AXIS2_PLACEMENT_3D('',#1747,#1748,#1749);
#1751=PLANE('',#1750);
#1752=DIRECTION('',(-0.963850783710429,-0.266442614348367,0.));
#1753=VECTOR('',#1752,1.);
#1754=CARTESIAN_POINT('',(-43.4214778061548,-12.0032397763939,3.45));
#1755=LINE('',#1754,#1753);
#1756=CARTESIAN_POINT('',(-43.4311163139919,-12.0059042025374,3.45));
#1757=VERTEX_POINT('',#1756);
#1758=EDGE_CURVE('E2930',#956,#1757,#1755,.T.);
#1759=ORIENTED_EDGE('',*,*,#1758,.F.);
#1760=ORIENTED_EDGE('',*,*,#957,.F.);
#1761=DIRECTION('',(-0.947588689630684,-0.319492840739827,0.));
#1762=VECTOR('',#1761,1.);
#1763=CARTESIAN_POINT('',(-42.6888704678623,-14.3931524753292,3.45));
#1764=LINE('',#1763,#1762);
#1765=CARTESIAN_POINT('',(-42.6983463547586,-14.3963474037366,3.45));
#1766=VERTEX_POINT('',#1765);
#1767=EDGE_CURVE('E2934',#947,#1766,#1764,.T.);
#1768=ORIENTED_EDGE('',*,*,#1767,.T.);
#1769=CARTESIAN_POINT('',(0.,0.,3.45));
#1770=DIRECTION('',(0.,0.,-1.));
#1771=DIRECTION('',(-1.,0.,0.));
#1772=AXIS2_PLACEMENT_3D('',#1769,#1770,#1771);
#1773=CIRCLE('',#1772,45.06);
#1774=EDGE_CURVE('E2936',#1766,#1757,#1773,.T.);
#1775=ORIENTED_EDGE('',*,*,#1774,.T.);
#1776=EDGE_LOOP('',(#1759,#1760,#1768,#1775));
#1777=FACE_BOUND('',#1776,.T.);
#1778=ADVANCED_FACE('F1271',(#1777),#1751,.F.);
#1779=CARTESIAN_POINT('',(-42.6888704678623,-14.3931524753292,3.55));
#1780=DIRECTION('',(-0.319492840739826,0.947588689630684,0.));
#1781=DIRECTION('',(0.,0.,-1.));
#1782=AXIS2_PLACEMENT_3D('',#1779,#1780,#1781);
#1783=PLANE('',#1782);
#1784=ORIENTED_EDGE('',*,*,#1767,.F.);
#1785=ORIENTED_EDGE('',*,*,#948,.F.);
#1786=DIRECTION('',(-0.947588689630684,-0.319492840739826,0.));
#1787=VECTOR('',#1786,1.);
#1788=CARTESIAN_POINT('',(-42.6888704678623,-14.3931524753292,3.65));
#1789=LINE('',#1788,#1787);
#1790=CARTESIAN_POINT('',(-42.6983463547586,-14.3963474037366,3.65));
#1791=VERTEX_POINT('',#1790);
#1792=EDGE_CURVE('E2937',#945,#1791,#1789,.T.);
#1793=ORIENTED_EDGE('',*,*,#1792,.T.);
#1794=DIRECTION('',(0.,0.,-1.));
#1795=VECTOR('',#1794,1.);
#1796=CARTESIAN_POINT('',(-42.6983463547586,-14.3963474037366,6.));
#1797=LINE('',#1796,#1795);
#1798=EDGE_CURVE('E2939',#1791,#1766,#1797,.T.);
#1799=ORIENTED_EDGE('',*,*,#1798,.T.);
#1800=EDGE_LOOP('',(#1784,#1785,#1793,#1799));
#1801=FACE_BOUND('',#1800,.T.);
#1802=ADVANCED_FACE('F2677',(#1801),#1783,.F.);
#1803=CARTESIAN_POINT('',(0.,0.,3.65));
#1804=DIRECTION('',(0.,0.,1.));
#1805=DIRECTION('',(1.,0.,0.));
#1806=AXIS2_PLACEMENT_3D('',#1803,#1804,#1805);
#1807=PLANE('',#1806);
#1808=ORIENTED_EDGE('',*,*,#1792,.F.);
#1809=ORIENTED_EDGE('',*,*,#972,.T.);
#1810=DIRECTION('',(-0.963850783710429,-0.266442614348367,0.));
#1811=VECTOR('',#1810,1.);
#1812=CARTESIAN_POINT('',(-43.4214778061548,-12.0032397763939,3.65));
#1813=LINE('',#1812,#1811);
#1814=CARTESIAN_POINT('',(-43.4311163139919,-12.0059042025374,3.65));
#1815=VERTEX_POINT('',#1814);
#1816=EDGE_CURVE('E2928',#964,#1815,#1813,.T.);
#1817=ORIENTED_EDGE('',*,*,#1816,.T.);
#1818=CARTESIAN_POINT('',(0.,0.,3.65));
#1819=DIRECTION('',(0.,0.,-1.));
#1820=DIRECTION('',(-1.,0.,0.));
#1821=AXIS2_PLACEMENT_3D('',#1818,#1819,#1820);
#1822=CIRCLE('',#1821,45.06);
#1823=EDGE_CURVE('E2951',#1791,#1815,#1822,.T.);
#1824=ORIENTED_EDGE('',*,*,#1823,.F.);
#1825=EDGE_LOOP('',(#1808,#1809,#1817,#1824));
#1826=FACE_BOUND('',#1825,.T.);
#1827=ADVANCED_FACE('F2667',(#1826),#1807,.T.);
#1828=CARTESIAN_POINT('',(-43.4214778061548,-12.0032397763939,3.55));
#1829=DIRECTION('',(0.266442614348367,-0.963850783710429,0.));
#1830=DIRECTION('',(0.,0.,1.));
#1831=AXIS2_PLACEMENT_3D('',#1828,#1829,#1830);
#1832=PLANE('',#1831);
#1833=ORIENTED_EDGE('',*,*,#965,.F.);
#1834=ORIENTED_EDGE('',*,*,#1758,.T.);
#1835=DIRECTION('',(0.,0.,-1.));
#1836=VECTOR('',#1835,1.);
#1837=CARTESIAN_POINT('',(-43.4311163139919,-12.0059042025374,6.));
#1838=LINE('',#1837,#1836);
#1839=EDGE_CURVE('E2933',#1757,#1815,#1838,.F.);
#1840=ORIENTED_EDGE('',*,*,#1839,.T.);
#1841=ORIENTED_EDGE('',*,*,#1816,.F.);
#1842=EDGE_LOOP('',(#1833,#1834,#1840,#1841));
#1843=FACE_BOUND('',#1842,.T.);
#1844=ADVANCED_FACE('F2656',(#1843),#1832,.F.);
#1845=CARTESIAN_POINT('',(0.,0.,6.));
#1846=DIRECTION('',(0.,0.,-1.));
#1847=DIRECTION('',(-1.,0.,0.));
#1848=AXIS2_PLACEMENT_3D('',#1845,#1846,#1847);
#1849=CYLINDRICAL_SURFACE('',#1848,45.06);
#1850=ORIENTED_EDGE('',*,*,#1823,.T.);
#1851=ORIENTED_EDGE('',*,*,#1839,.F.);
#1852=ORIENTED_EDGE('',*,*,#1774,.F.);
#1853=ORIENTED_EDGE('',*,*,#1798,.F.);
#1854=EDGE_LOOP('',(#1850,#1851,#1852,#1853));
#1855=FACE_BOUND('',#1854,.T.);
#1856=ADVANCED_FACE('F2646',(#1855),#1849,.T.);
#1857=CARTESIAN_POINT('',(0.,0.,3.65));
#1858=DIRECTION('',(0.,0.,1.));
#1859=DIRECTION('',(1.,0.,0.));
#1860=AXIS2_PLACEMENT_3D('',#1857,#1858,#1859);
#1861=PLANE('',#1860);
#1862=DIRECTION('',(-0.955434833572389,0.295202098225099,0.));
#1863=VECTOR('',#1862,1.);
#1864=CARTESIAN_POINT('',(-43.0423392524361,13.2988545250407,3.65));
#1865=LINE('',#1864,#1863);
#1866=CARTESIAN_POINT('',(-43.0518936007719,13.301806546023,3.65));
#1867=VERTEX_POINT('',#1866);
#1868=EDGE_CURVE('E2964',#40,#1867,#1865,.T.);
#1869=ORIENTED_EDGE('',*,*,#1868,.F.);
#1870=ORIENTED_EDGE('',*,*,#41,.T.);
#1871=DIRECTION('',(-0.947588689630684,0.319492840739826,0.));
#1872=VECTOR('',#1871,1.);
#1873=CARTESIAN_POINT('',(-42.6888704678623,14.3931524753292,3.65));
#1874=LINE('',#1873,#1872);
#1875=CARTESIAN_POINT('',(-42.6983463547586,14.3963474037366,3.65));
#1876=VERTEX_POINT('',#1875);
#1877=EDGE_CURVE('E2968',#31,#1876,#1874,.T.);
#1878=ORIENTED_EDGE('',*,*,#1877,.T.);
#1879=CARTESIAN_POINT('',(0.,0.,3.65));
#1880=DIRECTION('',(0.,0.,-1.));
#1881=DIRECTION('',(-1.,0.,0.));
#1882=AXIS2_PLACEMENT_3D('',#1879,#1880,#1881);
#1883=CIRCLE('',#1882,45.06);
#1884=EDGE_CURVE('E3041',#1867,#1876,#1883,.T.);
#1885=ORIENTED_EDGE('',*,*,#1884,.F.);
#1886=EDGE_LOOP('',(#1869,#1870,#1878,#1885));
#1887=FACE_BOUND('',#1886,.T.);
#1888=ADVANCED_FACE('F2636',(#1887),#1861,.T.);
#1889=CARTESIAN_POINT('',(-42.6888704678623,14.3931524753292,3.55));
#1890=DIRECTION('',(-0.319492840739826,-0.947588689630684,0.));
#1891=DIRECTION('',(0.,0.,1.));
#1892=AXIS2_PLACEMENT_3D('',#1889,#1890,#1891);
#1893=PLANE('',#1892);
#1894=ORIENTED_EDGE('',*,*,#1877,.F.);
#1895=ORIENTED_EDGE('',*,*,#32,.F.);
#1896=DIRECTION('',(-0.947588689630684,0.319492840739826,0.));
#1897=VECTOR('',#1896,1.);
#1898=CARTESIAN_POINT('',(-42.6888704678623,14.3931524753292,3.45));
#1899=LINE('',#1898,#1897);
#1900=CARTESIAN_POINT('',(-42.6983463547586,14.3963474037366,3.45));
#1901=VERTEX_POINT('',#1900);
#1902=EDGE_CURVE('E2970',#29,#1901,#1899,.T.);
#1903=ORIENTED_EDGE('',*,*,#1902,.T.);
#1904=DIRECTION('',(0.,0.,-1.));
#1905=VECTOR('',#1904,1.);
#1906=CARTESIAN_POINT('',(-42.6983463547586,14.3963474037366,6.));
#1907=LINE('',#1906,#1905);
#1908=EDGE_CURVE('E2972',#1901,#1876,#1907,.F.);
#1909=ORIENTED_EDGE('',*,*,#1908,.T.);
#1910=EDGE_LOOP('',(#1894,#1895,#1903,#1909));
#1911=FACE_BOUND('',#1910,.T.);
#1912=ADVANCED_FACE('F2626',(#1911),#1893,.F.);
#1913=CARTESIAN_POINT('',(0.,0.,3.45));
#1914=DIRECTION('',(0.,0.,1.));
#1915=DIRECTION('',(1.,0.,0.));
#1916=AXIS2_PLACEMENT_3D('',#1913,#1914,#1915);
#1917=PLANE('',#1916);
#1918=ORIENTED_EDGE('',*,*,#1902,.F.);
#1919=ORIENTED_EDGE('',*,*,#124,.F.);
#1920=DIRECTION('',(-0.955434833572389,0.295202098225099,0.));
#1921=VECTOR('',#1920,1.);
#1922=CARTESIAN_POINT('',(-43.0423392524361,13.2988545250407,3.45));
#1923=LINE('',#1922,#1921);
#1924=CARTESIAN_POINT('',(-43.0518936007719,13.301806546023,3.45));
#1925=VERTEX_POINT('',#1924);
#1926=EDGE_CURVE('E2973',#116,#1925,#1923,.T.);
#1927=ORIENTED_EDGE('',*,*,#1926,.T.);
#1928=CARTESIAN_POINT('',(0.,0.,3.45));
#1929=DIRECTION('',(0.,0.,-1.));
#1930=DIRECTION('',(-1.,0.,0.));
#1931=AXIS2_PLACEMENT_3D('',#1928,#1929,#1930);
#1932=CIRCLE('',#1931,45.06);
#1933=EDGE_CURVE('E2975',#1925,#1901,#1932,.T.);
#1934=ORIENTED_EDGE('',*,*,#1933,.T.);
#1935=EDGE_LOOP('',(#1918,#1919,#1927,#1934));
#1936=FACE_BOUND('',#1935,.T.);
#1937=ADVANCED_FACE('F2616',(#1936),#1917,.F.);
#1938=CARTESIAN_POINT('',(-43.0423392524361,13.2988545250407,2.875));
#1939=DIRECTION('',(-0.295202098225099,-0.955434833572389,0.));
#1940=DIRECTION('',(0.,0.,1.));
#1941=AXIS2_PLACEMENT_3D('',#1938,#1939,#1940);
#1942=PLANE('',#1941);
#1943=ORIENTED_EDGE('',*,*,#1926,.F.);
#1944=ORIENTED_EDGE('',*,*,#117,.F.);
#1945=DIRECTION('',(-0.955434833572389,0.295202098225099,0.));
#1946=VECTOR('',#1945,1.);
#1947=CARTESIAN_POINT('',(-43.0423392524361,13.2988545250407,2.3));
#1948=LINE('',#1947,#1946);
#1949=CARTESIAN_POINT('',(-43.0518936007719,13.301806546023,2.3));
#1950=VERTEX_POINT('',#1949);
#1951=EDGE_CURVE('E2976',#108,#1950,#1948,.T.);
#1952=ORIENTED_EDGE('',*,*,#1951,.T.);
#1953=DIRECTION('',(0.,0.,-1.));
#1954=VECTOR('',#1953,1.);
#1955=CARTESIAN_POINT('',(-43.0518936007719,13.301806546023,6.));
#1956=LINE('',#1955,#1954);
#1957=EDGE_CURVE('E2978',#1950,#1925,#1956,.F.);
#1958=ORIENTED_EDGE('',*,*,#1957,.T.);
#1959=EDGE_LOOP('',(#1943,#1944,#1952,#1958));
#1960=FACE_BOUND('',#1959,.T.);
#1961=ADVANCED_FACE('F2606',(#1960),#1942,.F.);
#1962=CARTESIAN_POINT('',(0.,0.,2.3));
#1963=DIRECTION('',(0.,0.,1.));
#1964=DIRECTION('',(1.,0.,0.));
#1965=AXIS2_PLACEMENT_3D('',#1962,#1963,#1964);
#1966=PLANE('',#1965);
#1967=ORIENTED_EDGE('',*,*,#1951,.F.);
#1968=ORIENTED_EDGE('',*,*,#109,.F.);
#1969=DIRECTION('',(-0.956735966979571,0.290957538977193,0.));
#1970=VECTOR('',#1969,1.);
#1971=CARTESIAN_POINT('',(-43.1009553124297,13.1076371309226,2.3));
#1972=LINE('',#1971,#1970);
#1973=CARTESIAN_POINT('',(-43.1105226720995,13.1105467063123,2.3));
#1974=VERTEX_POINT('',#1973);
#1975=EDGE_CURVE('E2979',#99,#1974,#1972,.T.);
#1976=ORIENTED_EDGE('',*,*,#1975,.T.);
#1977=CARTESIAN_POINT('',(0.,0.,2.3));
#1978=DIRECTION('',(0.,0.,-1.));
#1979=DIRECTION('',(-1.,0.,0.));
#1980=AXIS2_PLACEMENT_3D('',#1977,#1978,#1979);
#1981=CIRCLE('',#1980,45.06);
#1982=EDGE_CURVE('E2981',#1974,#1950,#1981,.T.);
#1983=ORIENTED_EDGE('',*,*,#1982,.T.);
#1984=EDGE_LOOP('',(#1967,#1968,#1976,#1983));
#1985=FACE_BOUND('',#1984,.T.);
#1986=ADVANCED_FACE('F2596',(#1985),#1966,.F.);
#1987=CARTESIAN_POINT('',(-43.1009553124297,13.1076371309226,2.875));
#1988=DIRECTION('',(0.290957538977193,0.956735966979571,0.));
#1989=DIRECTION('',(0.,0.,-1.));
#1990=AXIS2_PLACEMENT_3D('',#1987,#1988,#1989);
#1991=PLANE('',#1990);
#1992=ORIENTED_EDGE('',*,*,#1975,.F.);
#1993=ORIENTED_EDGE('',*,*,#100,.F.);
#1994=DIRECTION('',(-0.956735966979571,0.290957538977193,0.));
#1995=VECTOR('',#1994,1.);
#1996=CARTESIAN_POINT('',(-43.1009553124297,13.1076371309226,3.45));
#1997=LINE('',#1996,#1995);
#1998=CARTESIAN_POINT('',(-43.1105226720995,13.1105467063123,3.45));
#1999=VERTEX_POINT('',#1998);
#2000=EDGE_CURVE('E2982',#91,#1999,#1997,.T.);
#2001=ORIENTED_EDGE('',*,*,#2000,.T.);
#2002=DIRECTION('',(0.,0.,-1.));
#2003=VECTOR('',#2002,1.);
#2004=CARTESIAN_POINT('',(-43.1105226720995,13.1105467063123,6.));
#2005=LINE('',#2004,#2003);
#2006=EDGE_CURVE('E2984',#1999,#1974,#2005,.T.);
#2007=ORIENTED_EDGE('',*,*,#2006,.T.);
#2008=EDGE_LOOP('',(#1992,#1993,#2001,#2007));
#2009=FACE_BOUND('',#2008,.T.);
#2010=ADVANCED_FACE('F2586',(#2009),#1991,.F.);
#2011=CARTESIAN_POINT('',(0.,0.,3.45));
#2012=DIRECTION('',(0.,0.,1.));
#2013=DIRECTION('',(1.,0.,0.));
#2014=AXIS2_PLACEMENT_3D('',#2011,#2012,#2013);
#2015=PLANE('',#2014);
#2016=ORIENTED_EDGE('',*,*,#2000,.F.);
#2017=ORIENTED_EDGE('',*,*,#92,.F.);
#2018=DIRECTION('',(-0.963850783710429,0.266442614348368,0.));
#2019=VECTOR('',#2018,1.);
#2020=CARTESIAN_POINT('',(-43.4214778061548,12.003239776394,3.45));
#2021=LINE('',#2020,#2019);
#2022=CARTESIAN_POINT('',(-43.4311163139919,12.0059042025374,3.45));
#2023=VERTEX_POINT('',#2022);
#2024=EDGE_CURVE('E2985',#82,#2023,#2021,.T.);
#2025=ORIENTED_EDGE('',*,*,#2024,.T.);
#2026=CARTESIAN_POINT('',(0.,0.,3.45));
#2027=DIRECTION('',(0.,0.,-1.));
#2028=DIRECTION('',(-1.,0.,0.));
#2029=AXIS2_PLACEMENT_3D('',#2026,#2027,#2028);
#2030=CIRCLE('',#2029,45.06);
#2031=EDGE_CURVE('E2987',#2023,#1999,#2030,.T.);
#2032=ORIENTED_EDGE('',*,*,#2031,.T.);
#2033=EDGE_LOOP('',(#2016,#2017,#2025,#2032));
#2034=FACE_BOUND('',#2033,.T.);
#2035=ADVANCED_FACE('F2576',(#2034),#2015,.F.);
#2036=CARTESIAN_POINT('',(-43.4214778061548,12.003239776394,3.55));
#2037=DIRECTION('',(0.266442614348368,0.963850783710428,0.));
#2038=DIRECTION('',(0.,0.,-1.));
#2039=AXIS2_PLACEMENT_3D('',#2036,#2037,#2038);
#2040=PLANE('',#2039);
#2041=ORIENTED_EDGE('',*,*,#2024,.F.);
#2042=ORIENTED_EDGE('',*,*,#83,.F.);
#2043=DIRECTION('',(-0.963850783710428,0.266442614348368,0.));
#2044=VECTOR('',#2043,1.);
#2045=CARTESIAN_POINT('',(-43.4214778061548,12.003239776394,3.65));
#2046=LINE('',#2045,#2044);
#2047=CARTESIAN_POINT('',(-43.4311163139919,12.0059042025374,3.65));
#2048=VERTEX_POINT('',#2047);
#2049=EDGE_CURVE('E2988',#74,#2048,#2046,.T.);
#2050=ORIENTED_EDGE('',*,*,#2049,.T.);
#2051=DIRECTION('',(0.,0.,-1.));
#2052=VECTOR('',#2051,1.);
#2053=CARTESIAN_POINT('',(-43.4311163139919,12.0059042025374,6.));
#2054=LINE('',#2053,#2052);
#2055=EDGE_CURVE('E2990',#2048,#2023,#2054,.T.);
#2056=ORIENTED_EDGE('',*,*,#2055,.T.);
#2057=EDGE_LOOP('',(#2041,#2042,#2050,#2056));
#2058=FACE_BOUND('',#2057,.T.);
#2059=ADVANCED_FACE('F2566',(#2058),#2040,.F.);
#2060=CARTESIAN_POINT('',(0.,0.,3.65));
#2061=DIRECTION('',(0.,0.,1.));
#2062=DIRECTION('',(1.,0.,0.));
#2063=AXIS2_PLACEMENT_3D('',#2060,#2061,#2062);
#2064=PLANE('',#2063);
#2065=ORIENTED_EDGE('',*,*,#2049,.F.);
#2066=ORIENTED_EDGE('',*,*,#75,.T.);
#2067=DIRECTION('',(-0.956735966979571,0.290957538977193,0.));
#2068=VECTOR('',#2067,1.);
#2069=CARTESIAN_POINT('',(-43.1009553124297,13.1076371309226,3.65));
#2070=LINE('',#2069,#2068);
#2071=CARTESIAN_POINT('',(-43.1105226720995,13.1105467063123,3.65));
#2072=VERTEX_POINT('',#2071);
#2073=EDGE_CURVE('E2991',#65,#2072,#2070,.T.);
#2074=ORIENTED_EDGE('',*,*,#2073,.T.);
#2075=CARTESIAN_POINT('',(0.,0.,3.65));
#2076=DIRECTION('',(0.,0.,-1.));
#2077=DIRECTION('',(-1.,0.,0.));
#2078=AXIS2_PLACEMENT_3D('',#2075,#2076,#2077);
#2079=CIRCLE('',#2078,45.06);
#2080=EDGE_CURVE('E1070',#2048,#2072,#2079,.T.);
#2081=ORIENTED_EDGE('',*,*,#2080,.F.);
#2082=EDGE_LOOP('',(#2065,#2066,#2074,#2081));
#2083=FACE_BOUND('',#2082,.T.);
#2084=ADVANCED_FACE('F2556',(#2083),#2064,.T.);
#2085=CARTESIAN_POINT('',(-43.1009553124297,13.1076371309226,4.225));
#2086=DIRECTION('',(0.290957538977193,0.956735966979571,0.));
#2087=DIRECTION('',(0.,0.,-1.));
#2088=AXIS2_PLACEMENT_3D('',#2085,#2086,#2087);
#2089=PLANE('',#2088);
#2090=ORIENTED_EDGE('',*,*,#2073,.F.);
#2091=ORIENTED_EDGE('',*,*,#66,.F.);
#2092=DIRECTION('',(-0.956735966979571,0.290957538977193,0.));
#2093=VECTOR('',#2092,1.);
#2094=CARTESIAN_POINT('',(-43.1009553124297,13.1076371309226,4.8));
#2095=LINE('',#2094,#2093);
#2096=CARTESIAN_POINT('',(-43.1105226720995,13.1105467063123,4.8));
#2097=VERTEX_POINT('',#2096);
#2098=EDGE_CURVE('E2993',#57,#2097,#2095,.T.);
#2099=ORIENTED_EDGE('',*,*,#2098,.T.);
#2100=DIRECTION('',(0.,0.,-1.));
#2101=VECTOR('',#2100,1.);
#2102=CARTESIAN_POINT('',(-43.1105226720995,13.1105467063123,6.));
#2103=LINE('',#2102,#2101);
#2104=EDGE_CURVE('E2996',#2097,#2072,#2103,.T.);
#2105=ORIENTED_EDGE('',*,*,#2104,.T.);
#2106=EDGE_LOOP('',(#2090,#2091,#2099,#2105));
#2107=FACE_BOUND('',#2106,.T.);
#2108=ADVANCED_FACE('F2546',(#2107),#2089,.F.);
#2109=CARTESIAN_POINT('',(0.,0.,4.8));
#2110=DIRECTION('',(0.,0.,1.));
#2111=DIRECTION('',(1.,0.,0.));
#2112=AXIS2_PLACEMENT_3D('',#2109,#2110,#2111);
#2113=PLANE('',#2112);
#2114=ORIENTED_EDGE('',*,*,#2098,.F.);
#2115=ORIENTED_EDGE('',*,*,#58,.T.);
#2116=DIRECTION('',(-0.955434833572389,0.295202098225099,0.));
#2117=VECTOR('',#2116,1.);
#2118=CARTESIAN_POINT('',(-43.0423392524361,13.2988545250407,4.8));
#2119=LINE('',#2118,#2117);
#2120=CARTESIAN_POINT('',(-43.0518936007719,13.301806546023,4.8));
#2121=VERTEX_POINT('',#2120);
#2122=EDGE_CURVE('E2962',#48,#2121,#2119,.T.);
#2123=ORIENTED_EDGE('',*,*,#2122,.T.);
#2124=CARTESIAN_POINT('',(0.,0.,4.8));
#2125=DIRECTION('',(0.,0.,-1.));
#2126=DIRECTION('',(-1.,0.,0.));
#2127=AXIS2_PLACEMENT_3D('',#2124,#2125,#2126);
#2128=CIRCLE('',#2127,45.06);
#2129=EDGE_CURVE('E3040',#2097,#2121,#2128,.T.);
#2130=ORIENTED_EDGE('',*,*,#2129,.F.);
#2131=EDGE_LOOP('',(#2114,#2115,#2123,#2130));
#2132=FACE_BOUND('',#2131,.T.);
#2133=ADVANCED_FACE('F2536',(#2132),#2113,.T.);
#2134=CARTESIAN_POINT('',(-43.0423392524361,13.2988545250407,4.225));
#2135=DIRECTION('',(-0.295202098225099,-0.955434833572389,0.));
#2136=DIRECTION('',(0.,0.,1.));
#2137=AXIS2_PLACEMENT_3D('',#2134,#2135,#2136);
#2138=PLANE('',#2137);
#2139=ORIENTED_EDGE('',*,*,#49,.F.);
#2140=ORIENTED_EDGE('',*,*,#1868,.T.);
#2141=DIRECTION('',(0.,0.,-1.));
#2142=VECTOR('',#2141,1.);
#2143=CARTESIAN_POINT('',(-43.0518936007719,13.301806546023,6.));
#2144=LINE('',#2143,#2142);
#2145=EDGE_CURVE('E2967',#1867,#2121,#2144,.F.);
#2146=ORIENTED_EDGE('',*,*,#2145,.T.);
#2147=ORIENTED_EDGE('',*,*,#2122,.F.);
#2148=EDGE_LOOP('',(#2139,#2140,#2146,#2147));
#2149=FACE_BOUND('',#2148,.T.);
#2150=ADVANCED_FACE('F2523',(#2149),#2138,.F.);
#2151=CARTESIAN_POINT('',(0.,0.,6.));
#2152=DIRECTION('',(0.,0.,-1.));
#2153=DIRECTION('',(-1.,0.,0.));
#2154=AXIS2_PLACEMENT_3D('',#2151,#2152,#2153);
#2155=CYLINDRICAL_SURFACE('',#2154,45.06);
#2156=ORIENTED_EDGE('',*,*,#2129,.T.);
#2157=ORIENTED_EDGE('',*,*,#2145,.F.);
#2158=ORIENTED_EDGE('',*,*,#1884,.T.);
#2159=ORIENTED_EDGE('',*,*,#1908,.F.);
#2160=ORIENTED_EDGE('',*,*,#1933,.F.);
#2161=ORIENTED_EDGE('',*,*,#1957,.F.);
#2162=ORIENTED_EDGE('',*,*,#1982,.F.);
#2163=ORIENTED_EDGE('',*,*,#2006,.F.);
#2164=ORIENTED_EDGE('',*,*,#2031,.F.);
#2165=ORIENTED_EDGE('',*,*,#2055,.F.);
#2166=ORIENTED_EDGE('',*,*,#2080,.T.);
#2167=ORIENTED_EDGE('',*,*,#2104,.F.);
#2168=EDGE_LOOP('',(#2156,#2157,#2158,#2159,#2160,#2161,#2162,#2163,#2164,#2165,#2166,#2167));
#2169=FACE_BOUND('',#2168,.T.);
#2170=ADVANCED_FACE('F2514',(#2169),#2155,.T.);
#2171=CARTESIAN_POINT('',(0.,0.,1.99999999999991));
#2172=DIRECTION('',(0.,0.,1.));
#2173=DIRECTION('',(1.,0.,0.));
#2174=AXIS2_PLACEMENT_3D('',#2171,#2172,#2173);
#2175=PLANE('',#2174);
#2176=DIRECTION('',(0.968706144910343,0.248210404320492,0.));
#2177=VECTOR('',#2176,1.);
#2178=CARTESIAN_POINT('',(-43.6402118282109,-11.1818787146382,1.99999999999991));
#2179=LINE('',#2178,#2177);
#2180=CARTESIAN_POINT('',(-43.64989888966,-11.1843608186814,1.99999999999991));
#2181=VERTEX_POINT('',#2180);
#2182=EDGE_CURVE('E1029',#2181,#1147,#2179,.T.);
#2183=ORIENTED_EDGE('',*,*,#2182,.F.);
#2184=CARTESIAN_POINT('',(0.,0.,1.99999999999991));
#2185=DIRECTION('',(0.,0.,-1.));
#2186=DIRECTION('',(-1.,0.,0.));
#2187=AXIS2_PLACEMENT_3D('',#2184,#2185,#2186);
#2188=CIRCLE('',#2187,45.06);
#2189=CARTESIAN_POINT('',(-43.6991216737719,-10.9904670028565,1.99999999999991));
#2190=VERTEX_POINT('',#2189);
#2191=EDGE_CURVE('E1066',#2181,#2190,#2188,.T.);
#2192=ORIENTED_EDGE('',*,*,#2191,.T.);
#2193=DIRECTION('',(0.969798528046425,0.243907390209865,0.));
#2194=VECTOR('',#2193,1.);
#2195=CARTESIAN_POINT('',(-43.6894236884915,-10.9880279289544,1.99999999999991));
#2196=LINE('',#2195,#2194);
#2197=EDGE_CURVE('E1065',#2190,#1156,#2196,.T.);
#2198=ORIENTED_EDGE('',*,*,#2197,.T.);
#2199=ORIENTED_EDGE('',*,*,#1157,.F.);
#2200=EDGE_LOOP('',(#2183,#2192,#2198,#2199));
#2201=FACE_BOUND('',#2200,.T.);
#2202=ADVANCED_FACE('F2505',(#2201),#2175,.F.);
#2203=CARTESIAN_POINT('',(-43.6894236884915,-10.9880279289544,3.99999999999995));
#2204=DIRECTION('',(0.243907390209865,-0.969798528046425,0.));
#2205=DIRECTION('',(0.,0.,1.));
#2206=AXIS2_PLACEMENT_3D('',#2203,#2204,#2205);
#2207=PLANE('',#2206);
#2208=ORIENTED_EDGE('',*,*,#2197,.F.);
#2209=DIRECTION('',(0.,0.,-1.));
#2210=VECTOR('',#2209,1.);
#2211=CARTESIAN_POINT('',(-43.6991216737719,-10.9904670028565,6.));
#2212=LINE('',#2211,#2210);
#2213=EDGE_CURVE('E1060',#2190,#1451,#2212,.F.);
#2214=ORIENTED_EDGE('',*,*,#2213,.T.);
#2215=ORIENTED_EDGE('',*,*,#1452,.T.);
#2216=ORIENTED_EDGE('',*,*,#1165,.F.);
#2217=EDGE_LOOP('',(#2208,#2214,#2215,#2216));
#2218=FACE_BOUND('',#2217,.T.);
#2219=ADVANCED_FACE('F2496',(#2218),#2207,.F.);
#2220=CARTESIAN_POINT('',(-43.6402118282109,-11.1818787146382,3.99999999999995));
#2221=DIRECTION('',(-0.248210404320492,0.968706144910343,0.));
#2222=DIRECTION('',(0.,0.,-1.));
#2223=AXIS2_PLACEMENT_3D('',#2220,#2221,#2222);
#2224=PLANE('',#2223);
#2225=DIRECTION('',(0.,0.,-1.));
#2226=VECTOR('',#2225,1.);
#2227=CARTESIAN_POINT('',(-43.64989888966,-11.1843608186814,6.));
#2228=LINE('',#2227,#2226);
#2229=EDGE_CURVE('E1071',#1460,#2181,#2228,.T.);
#2230=ORIENTED_EDGE('',*,*,#2229,.T.);
#2231=ORIENTED_EDGE('',*,*,#2182,.T.);
#2232=ORIENTED_EDGE('',*,*,#1148,.F.);
#2233=ORIENTED_EDGE('',*,*,#1467,.F.);
#2234=EDGE_LOOP('',(#2230,#2231,#2232,#2233));
#2235=FACE_BOUND('',#2234,.T.);
#2236=ADVANCED_FACE('F2487',(#2235),#2224,.F.);
#2237=CARTESIAN_POINT('',(0.,0.,6.));
#2238=DIRECTION('',(0.,0.,-1.));
#2239=DIRECTION('',(-1.,0.,0.));
#2240=AXIS2_PLACEMENT_3D('',#2237,#2238,#2239);
#2241=CYLINDRICAL_SURFACE('',#2240,45.06);
#2242=ORIENTED_EDGE('',*,*,#1461,.F.);
#2243=ORIENTED_EDGE('',*,*,#2213,.F.);
#2244=ORIENTED_EDGE('',*,*,#2191,.F.);
#2245=ORIENTED_EDGE('',*,*,#2229,.F.);
#2246=EDGE_LOOP('',(#2242,#2243,#2244,#2245));
#2247=FACE_BOUND('',#2246,.T.);
#2248=ADVANCED_FACE('F2478',(#2247),#2241,.T.);
#2249=CARTESIAN_POINT('',(0.,0.,1.99999999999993));
#2250=DIRECTION('',(0.,0.,1.));
#2251=DIRECTION('',(1.,0.,0.));
#2252=AXIS2_PLACEMENT_3D('',#2249,#2250,#2251);
#2253=PLANE('',#2252);
#2254=DIRECTION('',(0.97784776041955,0.209317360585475,0.));
#2255=VECTOR('',#2254,1.);
#2256=CARTESIAN_POINT('',(-44.0520416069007,-9.42974709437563,1.99999999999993));
#2257=LINE('',#2256,#2255);
#2258=CARTESIAN_POINT('',(-44.0618200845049,-9.43184026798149,1.99999999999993));
#2259=VERTEX_POINT('',#2258);
#2260=EDGE_CURVE('E988',#2259,#1176,#2257,.T.);
#2261=ORIENTED_EDGE('',*,*,#2260,.F.);
#2262=CARTESIAN_POINT('',(0.,0.,1.99999999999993));
#2263=DIRECTION('',(0.,0.,-1.));
#2264=DIRECTION('',(-1.,0.,0.));
#2265=AXIS2_PLACEMENT_3D('',#2262,#2263,#2264);
#2266=CIRCLE('',#2265,45.06);
#2267=CARTESIAN_POINT('',(-44.103258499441,-9.23613499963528,1.99999999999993));
#2268=VERTEX_POINT('',#2267);
#2269=EDGE_CURVE('E1025',#2259,#2268,#2266,.T.);
#2270=ORIENTED_EDGE('',*,*,#2269,.T.);
#2271=DIRECTION('',(0.978767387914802,0.204974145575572,0.));
#2272=VECTOR('',#2271,1.);
#2273=CARTESIAN_POINT('',(-44.0934708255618,-9.23408525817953,1.99999999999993));
#2274=LINE('',#2273,#2272);
#2275=EDGE_CURVE('E1024',#2268,#1185,#2274,.T.);
#2276=ORIENTED_EDGE('',*,*,#2275,.T.);
#2277=ORIENTED_EDGE('',*,*,#1186,.F.);
#2278=EDGE_LOOP('',(#2261,#2270,#2276,#2277));
#2279=FACE_BOUND('',#2278,.T.);
#2280=ADVANCED_FACE('F2469',(#2279),#2253,.F.);
#2281=CARTESIAN_POINT('',(-44.0934708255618,-9.23408525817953,3.99999999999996));
#2282=DIRECTION('',(0.204974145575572,-0.978767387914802,0.));
#2283=DIRECTION('',(0.,0.,1.));
#2284=AXIS2_PLACEMENT_3D('',#2281,#2282,#2283);
#2285=PLANE('',#2284);
#2286=ORIENTED_EDGE('',*,*,#2275,.F.);
#2287=DIRECTION('',(0.,0.,-1.));
#2288=VECTOR('',#2287,1.);
#2289=CARTESIAN_POINT('',(-44.103258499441,-9.23613499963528,6.));
#2290=LINE('',#2289,#2288);
#2291=EDGE_CURVE('E1019',#2268,#1427,#2290,.F.);
#2292=ORIENTED_EDGE('',*,*,#2291,.T.);
#2293=ORIENTED_EDGE('',*,*,#1428,.T.);
#2294=ORIENTED_EDGE('',*,*,#1194,.F.);
#2295=EDGE_LOOP('',(#2286,#2292,#2293,#2294));
#2296=FACE_BOUND('',#2295,.T.);
#2297=ADVANCED_FACE('F2460',(#2296),#2285,.F.);
#2298=CARTESIAN_POINT('',(-44.0520416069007,-9.42974709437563,3.99999999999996));
#2299=DIRECTION('',(-0.209317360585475,0.97784776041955,0.));
#2300=DIRECTION('',(0.,0.,-1.));
#2301=AXIS2_PLACEMENT_3D('',#2298,#2299,#2300);
#2302=PLANE('',#2301);
#2303=DIRECTION('',(0.,0.,-1.));
#2304=VECTOR('',#2303,1.);
#2305=CARTESIAN_POINT('',(-44.0618200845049,-9.43184026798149,6.));
#2306=LINE('',#2305,#2304);
#2307=EDGE_CURVE('E1030',#1436,#2259,#2306,.T.);
#2308=ORIENTED_EDGE('',*,*,#2307,.T.);
#2309=ORIENTED_EDGE('',*,*,#2260,.T.);
#2310=ORIENTED_EDGE('',*,*,#1177,.F.);
#2311=ORIENTED_EDGE('',*,*,#1443,.F.);
#2312=EDGE_LOOP('',(#2308,#2309,#2310,#2311));
#2313=FACE_BOUND('',#2312,.T.);
#2314=ADVANCED_FACE('F2451',(#2313),#2302,.F.);
#2315=CARTESIAN_POINT('',(0.,0.,6.));
#2316=DIRECTION('',(0.,0.,-1.));
#2317=DIRECTION('',(-1.,0.,0.));
#2318=AXIS2_PLACEMENT_3D('',#2315,#2316,#2317);
#2319=CYLINDRICAL_SURFACE('',#2318,45.06);
#2320=ORIENTED_EDGE('',*,*,#1437,.F.);
#2321=ORIENTED_EDGE('',*,*,#2291,.F.);
#2322=ORIENTED_EDGE('',*,*,#2269,.F.);
#2323=ORIENTED_EDGE('',*,*,#2307,.F.);
#2324=EDGE_LOOP('',(#2320,#2321,#2322,#2323));
#2325=FACE_BOUND('',#2324,.T.);
#2326=ADVANCED_FACE('F2442',(#2325),#2319,.T.);
#2327=CARTESIAN_POINT('',(0.,0.,1.99999999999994));
#2328=DIRECTION('',(0.,0.,1.));
#2329=DIRECTION('',(1.,0.,0.));
#2330=AXIS2_PLACEMENT_3D('',#2327,#2328,#2329);
#2331=PLANE('',#2330);
#2332=DIRECTION('',(0.985428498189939,0.170090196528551,0.));
#2333=VECTOR('',#2332,1.);
#2334=CARTESIAN_POINT('',(-44.3935538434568,-7.66256335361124,1.99999999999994));
#2335=LINE('',#2334,#2333);
#2336=CARTESIAN_POINT('',(-44.4034081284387,-7.66426425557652,1.99999999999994));
#2337=VERTEX_POINT('',#2336);
#2338=EDGE_CURVE('E947',#2337,#1205,#2335,.T.);
#2339=ORIENTED_EDGE('',*,*,#2338,.F.);
#2340=CARTESIAN_POINT('',(0.,0.,1.99999999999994));
#2341=DIRECTION('',(0.,0.,-1.));
#2342=DIRECTION('',(-1.,0.,0.));
#2343=AXIS2_PLACEMENT_3D('',#2340,#2341,#2342);
#2344=CIRCLE('',#2343,45.06);
#2345=CARTESIAN_POINT('',(-44.4369960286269,-7.46705992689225,1.99999999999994));
#2346=VERTEX_POINT('',#2345);
#2347=EDGE_CURVE('E984',#2337,#2346,#2344,.T.);
#2348=ORIENTED_EDGE('',*,*,#2347,.T.);
#2349=DIRECTION('',(0.986173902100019,0.165713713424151,0.));
#2350=VECTOR('',#2349,1.);
#2351=CARTESIAN_POINT('',(-44.4271342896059,-7.465402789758,1.99999999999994));
#2352=LINE('',#2351,#2350);
#2353=EDGE_CURVE('E983',#2346,#1214,#2352,.T.);
#2354=ORIENTED_EDGE('',*,*,#2353,.T.);
#2355=ORIENTED_EDGE('',*,*,#1215,.F.);
#2356=EDGE_LOOP('',(#2339,#2348,#2354,#2355));
#2357=FACE_BOUND('',#2356,.T.);
#2358=ADVANCED_FACE('F2433',(#2357),#2331,.F.);
#2359=CARTESIAN_POINT('',(-44.4271342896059,-7.465402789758,3.99999999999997));
#2360=DIRECTION('',(0.165713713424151,-0.986173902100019,0.));
#2361=DIRECTION('',(0.,0.,1.));
#2362=AXIS2_PLACEMENT_3D('',#2359,#2360,#2361);
#2363=PLANE('',#2362);
#2364=ORIENTED_EDGE('',*,*,#2353,.F.);
#2365=DIRECTION('',(0.,0.,-1.));
#2366=VECTOR('',#2365,1.);
#2367=CARTESIAN_POINT('',(-44.4369960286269,-7.46705992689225,6.));
#2368=LINE('',#2367,#2366);
#2369=EDGE_CURVE('E978',#2346,#1403,#2368,.F.);
#2370=ORIENTED_EDGE('',*,*,#2369,.T.);
#2371=ORIENTED_EDGE('',*,*,#1404,.T.);
#2372=ORIENTED_EDGE('',*,*,#1223,.F.);
#2373=EDGE_LOOP('',(#2364,#2370,#2371,#2372));
#2374=FACE_BOUND('',#2373,.T.);
#2375=ADVANCED_FACE('F2424',(#2374),#2363,.F.);
#2376=CARTESIAN_POINT('',(-44.3935538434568,-7.66256335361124,3.99999999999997));
#2377=DIRECTION('',(-0.170090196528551,0.985428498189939,0.));
#2378=DIRECTION('',(0.,0.,-1.));
#2379=AXIS2_PLACEMENT_3D('',#2376,#2377,#2378);
#2380=PLANE('',#2379);
#2381=DIRECTION('',(0.,0.,-1.));
#2382=VECTOR('',#2381,1.);
#2383=CARTESIAN_POINT('',(-44.4034081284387,-7.66426425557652,6.));
#2384=LINE('',#2383,#2382);
#2385=EDGE_CURVE('E989',#1412,#2337,#2384,.T.);
#2386=ORIENTED_EDGE('',*,*,#2385,.T.);
#2387=ORIENTED_EDGE('',*,*,#2338,.T.);
#2388=ORIENTED_EDGE('',*,*,#1206,.F.);
#2389=ORIENTED_EDGE('',*,*,#1419,.F.);
#2390=EDGE_LOOP('',(#2386,#2387,#2388,#2389));
#2391=FACE_BOUND('',#2390,.T.);
#2392=ADVANCED_FACE('F2415',(#2391),#2380,.F.);
#2393=CARTESIAN_POINT('',(0.,0.,6.));
#2394=DIRECTION('',(0.,0.,-1.));
#2395=DIRECTION('',(-1.,0.,0.));
#2396=AXIS2_PLACEMENT_3D('',#2393,#2394,#2395);
#2397=CYLINDRICAL_SURFACE('',#2396,45.06);
#2398=ORIENTED_EDGE('',*,*,#1413,.F.);
#2399=ORIENTED_EDGE('',*,*,#2369,.F.);
#2400=ORIENTED_EDGE('',*,*,#2347,.F.);
#2401=ORIENTED_EDGE('',*,*,#2385,.F.);
#2402=EDGE_LOOP('',(#2398,#2399,#2400,#2401));
#2403=FACE_BOUND('',#2402,.T.);
#2404=ADVANCED_FACE('F2406',(#2403),#2397,.T.);
#2405=CARTESIAN_POINT('',(0.,0.,1.99999999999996));
#2406=DIRECTION('',(0.,0.,1.));
#2407=DIRECTION('',(1.,0.,0.));
#2408=AXIS2_PLACEMENT_3D('',#2405,#2406,#2407);
#2409=PLANE('',#2408);
#2410=DIRECTION('',(0.991436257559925,0.130591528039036,0.));
#2411=VECTOR('',#2410,1.);
#2412=CARTESIAN_POINT('',(-44.6642034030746,-5.88314833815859,1.99999999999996));
#2413=LINE('',#2412,#2411);
#2414=CARTESIAN_POINT('',(-44.6741177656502,-5.88445425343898,1.99999999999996));
#2415=VERTEX_POINT('',#2414);
#2416=EDGE_CURVE('E906',#2415,#1234,#2413,.T.);
#2417=ORIENTED_EDGE('',*,*,#2416,.F.);
#2418=CARTESIAN_POINT('',(0.,0.,1.99999999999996));
#2419=DIRECTION('',(0.,0.,-1.));
#2420=DIRECTION('',(-1.,0.,0.));
#2421=AXIS2_PLACEMENT_3D('',#2418,#2419,#2420);
#2422=CIRCLE('',#2421,45.06);
#2423=CARTESIAN_POINT('',(-44.6998015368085,-5.6860656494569,1.99999999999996));
#2424=VERTEX_POINT('',#2423);
#2425=EDGE_CURVE('E943',#2415,#2424,#2422,.T.);
#2426=ORIENTED_EDGE('',*,*,#2425,.T.);
#2427=DIRECTION('',(0.992006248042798,0.126188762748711,0.));
#2428=VECTOR('',#2427,1.);
#2429=CARTESIAN_POINT('',(-44.6898814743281,-5.68480376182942,1.99999999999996));
#2430=LINE('',#2429,#2428);
#2431=EDGE_CURVE('E942',#2424,#1243,#2430,.T.);
#2432=ORIENTED_EDGE('',*,*,#2431,.T.);
#2433=ORIENTED_EDGE('',*,*,#1244,.F.);
#2434=EDGE_LOOP('',(#2417,#2426,#2432,#2433));
#2435=FACE_BOUND('',#2434,.T.);
#2436=ADVANCED_FACE('F2397',(#2435),#2409,.F.);
#2437=CARTESIAN_POINT('',(-44.6898814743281,-5.68480376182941,3.99999999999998));
#2438=DIRECTION('',(0.126188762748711,-0.992006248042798,0.));
#2439=DIRECTION('',(0.,0.,1.));
#2440=AXIS2_PLACEMENT_3D('',#2437,#2438,#2439);
#2441=PLANE('',#2440);
#2442=ORIENTED_EDGE('',*,*,#2431,.F.);
#2443=DIRECTION('',(0.,0.,-1.));
#2444=VECTOR('',#2443,1.);
#2445=CARTESIAN_POINT('',(-44.6998015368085,-5.6860656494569,6.));
#2446=LINE('',#2445,#2444);
#2447=EDGE_CURVE('E937',#2424,#1379,#2446,.F.);
#2448=ORIENTED_EDGE('',*,*,#2447,.T.);
#2449=ORIENTED_EDGE('',*,*,#1380,.T.);
#2450=ORIENTED_EDGE('',*,*,#1252,.F.);
#2451=EDGE_LOOP('',(#2442,#2448,#2449,#2450));
#2452=FACE_BOUND('',#2451,.T.);
#2453=ADVANCED_FACE('F2388',(#2452),#2441,.F.);
#2454=CARTESIAN_POINT('',(-44.6642034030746,-5.88314833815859,3.99999999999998));
#2455=DIRECTION('',(-0.130591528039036,0.991436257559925,0.));
#2456=DIRECTION('',(0.,0.,-1.));
#2457=AXIS2_PLACEMENT_3D('',#2454,#2455,#2456);
#2458=PLANE('',#2457);
#2459=DIRECTION('',(0.,0.,-1.));
#2460=VECTOR('',#2459,1.);
#2461=CARTESIAN_POINT('',(-44.6741177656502,-5.88445425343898,6.));
#2462=LINE('',#2461,#2460);
#2463=EDGE_CURVE('E948',#1388,#2415,#2462,.T.);
#2464=ORIENTED_EDGE('',*,*,#2463,.T.);
#2465=ORIENTED_EDGE('',*,*,#2416,.T.);
#2466=ORIENTED_EDGE('',*,*,#1235,.F.);
#2467=ORIENTED_EDGE('',*,*,#1395,.F.);
#2468=EDGE_LOOP('',(#2464,#2465,#2466,#2467));
#2469=FACE_BOUND('',#2468,.T.);
#2470=ADVANCED_FACE('F2379',(#2469),#2458,.F.);
#2471=CARTESIAN_POINT('',(0.,0.,6.));
#2472=DIRECTION('',(0.,0.,-1.));
#2473=DIRECTION('',(-1.,0.,0.));
#2474=AXIS2_PLACEMENT_3D('',#2471,#2472,#2473);
#2475=CYLINDRICAL_SURFACE('',#2474,45.06);
#2476=ORIENTED_EDGE('',*,*,#1389,.F.);
#2477=ORIENTED_EDGE('',*,*,#2447,.F.);
#2478=ORIENTED_EDGE('',*,*,#2425,.F.);
#2479=ORIENTED_EDGE('',*,*,#2463,.F.);
#2480=EDGE_LOOP('',(#2476,#2477,#2478,#2479));
#2481=FACE_BOUND('',#2480,.T.);
#2482=ADVANCED_FACE('F2370',(#2481),#2475,.T.);
#2483=CARTESIAN_POINT('',(0.,0.,1.99999999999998));
#2484=DIRECTION('',(0.,0.,1.));
#2485=DIRECTION('',(1.,0.,0.));
#2486=AXIS2_PLACEMENT_3D('',#2483,#2484,#2485);
#2487=PLANE('',#2486);
#2488=DIRECTION('',(0.995861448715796,0.0908844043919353,0.));
#2489=VECTOR('',#2488,1.);
#2490=CARTESIAN_POINT('',(-44.8635582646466,-4.09434241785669,1.99999999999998));
#2491=LINE('',#2490,#2489);
#2492=CARTESIAN_POINT('',(-44.8735168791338,-4.09525126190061,1.99999999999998));
#2493=VERTEX_POINT('',#2492);
#2494=EDGE_CURVE('E785',#2493,#1263,#2491,.T.);
#2495=ORIENTED_EDGE('',*,*,#2494,.F.);
#2496=CARTESIAN_POINT('',(0.,0.,1.99999999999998));
#2497=DIRECTION('',(0.,0.,-1.));
#2498=DIRECTION('',(-1.,0.,0.));
#2499=AXIS2_PLACEMENT_3D('',#2496,#2497,#2498);
#2500=CIRCLE('',#2499,45.06);
#2501=CARTESIAN_POINT('',(-44.891255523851,-3.89599505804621,1.99999999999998));
#2502=VERTEX_POINT('',#2501);
#2503=EDGE_CURVE('E902',#2493,#2502,#2500,.T.);
#2504=ORIENTED_EDGE('',*,*,#2503,.T.);
#2505=DIRECTION('',(0.996255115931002,0.0864623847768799,0.));
#2506=VECTOR('',#2505,1.);
#2507=CARTESIAN_POINT('',(-44.8812929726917,-3.89513043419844,1.99999999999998));
#2508=LINE('',#2507,#2506);
#2509=EDGE_CURVE('E901',#2502,#1272,#2508,.T.);
#2510=ORIENTED_EDGE('',*,*,#2509,.T.);
#2511=ORIENTED_EDGE('',*,*,#1273,.F.);
#2512=EDGE_LOOP('',(#2495,#2504,#2510,#2511));
#2513=FACE_BOUND('',#2512,.T.);
#2514=ADVANCED_FACE('F2361',(#2513),#2487,.F.);
#2515=CARTESIAN_POINT('',(-44.8812929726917,-3.89513043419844,3.99999999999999));
#2516=DIRECTION('',(0.0864623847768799,-0.996255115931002,0.));
#2517=DIRECTION('',(0.,0.,1.));
#2518=AXIS2_PLACEMENT_3D('',#2515,#2516,#2517);
#2519=PLANE('',#2518);
#2520=ORIENTED_EDGE('',*,*,#2509,.F.);
#2521=DIRECTION('',(0.,0.,-1.));
#2522=VECTOR('',#2521,1.);
#2523=CARTESIAN_POINT('',(-44.891255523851,-3.89599505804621,6.));
#2524=LINE('',#2523,#2522);
#2525=EDGE_CURVE('E896',#2502,#1355,#2524,.F.);
#2526=ORIENTED_EDGE('',*,*,#2525,.T.);
#2527=ORIENTED_EDGE('',*,*,#1356,.T.);
#2528=ORIENTED_EDGE('',*,*,#1281,.F.);
#2529=EDGE_LOOP('',(#2520,#2526,#2527,#2528));
#2530=FACE_BOUND('',#2529,.T.);
#2531=ADVANCED_FACE('F2352',(#2530),#2519,.F.);
#2532=CARTESIAN_POINT('',(-44.8635582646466,-4.09434241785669,3.99999999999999));
#2533=DIRECTION('',(-0.0908844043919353,0.995861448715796,0.));
#2534=DIRECTION('',(0.,0.,-1.));
#2535=AXIS2_PLACEMENT_3D('',#2532,#2533,#2534);
#2536=PLANE('',#2535);
#2537=DIRECTION('',(0.,0.,-1.));
#2538=VECTOR('',#2537,1.);
#2539=CARTESIAN_POINT('',(-44.8735168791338,-4.09525126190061,6.));
#2540=LINE('',#2539,#2538);
#2541=EDGE_CURVE('E907',#1364,#2493,#2540,.T.);
#2542=ORIENTED_EDGE('',*,*,#2541,.T.);
#2543=ORIENTED_EDGE('',*,*,#2494,.T.);
#2544=ORIENTED_EDGE('',*,*,#1264,.F.);
#2545=ORIENTED_EDGE('',*,*,#1371,.F.);
#2546=EDGE_LOOP('',(#2542,#2543,#2544,#2545));
#2547=FACE_BOUND('',#2546,.T.);
#2548=ADVANCED_FACE('F2343',(#2547),#2536,.F.);
#2549=CARTESIAN_POINT('',(0.,0.,6.));
#2550=DIRECTION('',(0.,0.,-1.));
#2551=DIRECTION('',(-1.,0.,0.));
#2552=AXIS2_PLACEMENT_3D('',#2549,#2550,#2551);
#2553=CYLINDRICAL_SURFACE('',#2552,45.06);
#2554=ORIENTED_EDGE('',*,*,#1365,.F.);
#2555=ORIENTED_EDGE('',*,*,#2525,.F.);
#2556=ORIENTED_EDGE('',*,*,#2503,.F.);
#2557=ORIENTED_EDGE('',*,*,#2541,.F.);
#2558=EDGE_LOOP('',(#2554,#2555,#2556,#2557));
#2559=FACE_BOUND('',#2558,.T.);
#2560=ADVANCED_FACE('F2091',(#2559),#2553,.T.);
#2561=CARTESIAN_POINT('',(0.,0.,2.));
#2562=DIRECTION('',(0.,0.,1.));
#2563=DIRECTION('',(1.,0.,0.));
#2564=AXIS2_PLACEMENT_3D('',#2561,#2562,#2563);
#2565=PLANE('',#2564);
#2566=DIRECTION('',(0.998697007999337,0.0510322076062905,0.));
#2567=VECTOR('',#2566,1.);
#2568=CARTESIAN_POINT('',(-44.9913002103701,-2.29900095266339,2.));
#2569=LINE('',#2568,#2567);
#2570=CARTESIAN_POINT('',(-45.0012871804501,-2.29951127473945,2.));
#2571=VERTEX_POINT('',#2570);
#2572=EDGE_CURVE('E790',#2571,#982,#2569,.T.);
#2573=ORIENTED_EDGE('',*,*,#2572,.F.);
#2574=CARTESIAN_POINT('',(0.,0.,2.));
#2575=DIRECTION('',(0.,0.,-1.));
#2576=DIRECTION('',(-1.,0.,0.));
#2577=AXIS2_PLACEMENT_3D('',#2574,#2575,#2576);
#2578=CIRCLE('',#2577,45.06);
#2579=CARTESIAN_POINT('',(-45.0110523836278,-2.09970553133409,2.));
#2580=VERTEX_POINT('',#2579);
#2581=EDGE_CURVE('E747',#2571,#2580,#2578,.T.);
#2582=ORIENTED_EDGE('',*,*,#2581,.T.);
#2583=DIRECTION('',(0.998913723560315,0.0465979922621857,0.));
#2584=VECTOR('',#2583,1.);
#2585=CARTESIAN_POINT('',(-45.0010632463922,-2.09923955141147,2.));
#2586=LINE('',#2585,#2584);
#2587=EDGE_CURVE('E740',#2580,#984,#2586,.T.);
#2588=ORIENTED_EDGE('',*,*,#2587,.T.);
#2589=ORIENTED_EDGE('',*,*,#985,.F.);
#2590=EDGE_LOOP('',(#2573,#2582,#2588,#2589));
#2591=FACE_BOUND('',#2590,.T.);
#2592=ADVANCED_FACE('F742',(#2591),#2565,.F.);
#2593=CARTESIAN_POINT('',(-45.0010632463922,-2.09923955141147,4.));
#2594=DIRECTION('',(0.0465979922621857,-0.998913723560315,0.));
#2595=DIRECTION('',(0.,0.,1.));
#2596=AXIS2_PLACEMENT_3D('',#2593,#2594,#2595);
#2597=PLANE('',#2596);
#2598=ORIENTED_EDGE('',*,*,#2587,.F.);
#2599=DIRECTION('',(0.,0.,-1.));
#2600=VECTOR('',#2599,1.);
#2601=CARTESIAN_POINT('',(-45.0110523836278,-2.09970553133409,6.));
#2602=LINE('',#2601,#2600);
#2603=EDGE_CURVE('E751',#2580,#1331,#2602,.F.);
#2604=ORIENTED_EDGE('',*,*,#2603,.T.);
#2605=ORIENTED_EDGE('',*,*,#1332,.T.);
#2606=ORIENTED_EDGE('',*,*,#993,.F.);
#2607=EDGE_LOOP('',(#2598,#2604,#2605,#2606));
#2608=FACE_BOUND('',#2607,.T.);
#2609=ADVANCED_FACE('F755',(#2608),#2597,.F.);
#2610=CARTESIAN_POINT('',(-44.9913002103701,-2.29900095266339,4.));
#2611=DIRECTION('',(-0.0510322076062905,0.998697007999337,0.));
#2612=DIRECTION('',(0.,0.,-1.));
#2613=AXIS2_PLACEMENT_3D('',#2610,#2611,#2612);
#2614=PLANE('',#2613);
#2615=DIRECTION('',(0.,0.,-1.));
#2616=VECTOR('',#2615,1.);
#2617=CARTESIAN_POINT('',(-45.0012871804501,-2.29951127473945,6.));
#2618=LINE('',#2617,#2616);
#2619=EDGE_CURVE('E786',#1340,#2571,#2618,.T.);
#2620=ORIENTED_EDGE('',*,*,#2619,.T.);
#2621=ORIENTED_EDGE('',*,*,#2572,.T.);
#2622=ORIENTED_EDGE('',*,*,#1291,.F.);
#2623=ORIENTED_EDGE('',*,*,#1347,.F.);
#2624=EDGE_LOOP('',(#2620,#2621,#2622,#2623));
#2625=FACE_BOUND('',#2624,.T.);
#2626=ADVANCED_FACE('F2086',(#2625),#2614,.F.);
#2627=CARTESIAN_POINT('',(0.,0.,6.));
#2628=DIRECTION('',(0.,0.,-1.));
#2629=DIRECTION('',(-1.,0.,0.));
#2630=AXIS2_PLACEMENT_3D('',#2627,#2628,#2629);
#2631=CYLINDRICAL_SURFACE('',#2630,45.06);
#2632=ORIENTED_EDGE('',*,*,#1341,.F.);
#2633=ORIENTED_EDGE('',*,*,#2603,.F.);
#2634=ORIENTED_EDGE('',*,*,#2581,.F.);
#2635=ORIENTED_EDGE('',*,*,#2619,.F.);
#2636=EDGE_LOOP('',(#2632,#2633,#2634,#2635));
#2637=FACE_BOUND('',#2636,.T.);
#2638=ADVANCED_FACE('F692',(#2637),#2631,.T.);
#2639=CARTESIAN_POINT('',(-44.6529564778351,5.96791234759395,3.99999999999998));
#2640=DIRECTION('',(0.132473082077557,0.991186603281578,0.));
#2641=DIRECTION('',(0.,0.,-1.));
#2642=AXIS2_PLACEMENT_3D('',#2639,#2640,#2641);
#2643=PLANE('',#2642);
#2644=ORIENTED_EDGE('',*,*,#564,.F.);
#2645=DIRECTION('',(0.,0.,-1.));
#2646=VECTOR('',#2645,1.);
#2647=CARTESIAN_POINT('',(-44.6628683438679,5.96923707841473,6.));
#2648=LINE('',#2647,#2646);
#2649=CARTESIAN_POINT('',(-44.6628683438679,5.96923707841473,1.99999999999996));
#2650=VERTEX_POINT('',#2649);
#2651=EDGE_CURVE('E794',#557,#2650,#2648,.T.);
#2652=ORIENTED_EDGE('',*,*,#2651,.T.);
#2653=DIRECTION('',(0.991186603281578,-0.132473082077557,0.));
#2654=VECTOR('',#2653,1.);
#2655=CARTESIAN_POINT('',(-44.6529564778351,5.96791234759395,1.99999999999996));
#2656=LINE('',#2655,#2654);
#2657=EDGE_CURVE('E1229',#2650,#202,#2656,.T.);
#2658=ORIENTED_EDGE('',*,*,#2657,.T.);
#2659=ORIENTED_EDGE('',*,*,#203,.F.);
#2660=EDGE_LOOP('',(#2644,#2652,#2658,#2659));
#2661=FACE_BOUND('',#2660,.T.);
#2662=ADVANCED_FACE('F1277',(#2661),#2643,.F.);
#2663=CARTESIAN_POINT('',(0.,0.,1.99999999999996));
#2664=DIRECTION('',(0.,0.,1.));
#2665=DIRECTION('',(1.,0.,0.));
#2666=AXIS2_PLACEMENT_3D('',#2663,#2664,#2665);
#2667=PLANE('',#2666);
#2668=ORIENTED_EDGE('',*,*,#2657,.F.);
#2669=CARTESIAN_POINT('',(0.,0.,1.99999999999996));
#2670=DIRECTION('',(0.,0.,-1.));
#2671=DIRECTION('',(-1.,0.,0.));
#2672=AXIS2_PLACEMENT_3D('',#2669,#2670,#2671);
#2673=CIRCLE('',#2672,45.06);
#2674=CARTESIAN_POINT('',(-44.6359277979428,6.16745892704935,1.99999999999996));
#2675=VERTEX_POINT('',#2674);
#2676=EDGE_CURVE('E1225',#2650,#2675,#2673,.T.);
#2677=ORIENTED_EDGE('',*,*,#2676,.T.);
#2678=DIRECTION('',(0.990588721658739,-0.136872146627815,0.));
#2679=VECTOR('',#2678,1.);
#2680=CARTESIAN_POINT('',(-44.6260219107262,6.16609020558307,1.99999999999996));
#2681=LINE('',#2680,#2679);
#2682=EDGE_CURVE('E1224',#2675,#211,#2681,.T.);
#2683=ORIENTED_EDGE('',*,*,#2682,.T.);
#2684=ORIENTED_EDGE('',*,*,#212,.F.);
#2685=EDGE_LOOP('',(#2668,#2677,#2683,#2684));
#2686=FACE_BOUND('',#2685,.T.);
#2687=ADVANCED_FACE('F2114',(#2686),#2667,.F.);
#2688=CARTESIAN_POINT('',(-44.6260219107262,6.16609020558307,3.99999999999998));
#2689=DIRECTION('',(-0.136872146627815,-0.990588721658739,0.));
#2690=DIRECTION('',(0.,0.,1.));
#2691=AXIS2_PLACEMENT_3D('',#2688,#2689,#2690);
#2692=PLANE('',#2691);
#2693=ORIENTED_EDGE('',*,*,#2682,.F.);
#2694=DIRECTION('',(0.,0.,-1.));
#2695=VECTOR('',#2694,1.);
#2696=CARTESIAN_POINT('',(-44.6359277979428,6.16745892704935,6.));
#2697=LINE('',#2696,#2695);
#2698=EDGE_CURVE('E1220',#2675,#548,#2697,.F.);
#2699=ORIENTED_EDGE('',*,*,#2698,.T.);
#2700=ORIENTED_EDGE('',*,*,#549,.T.);
#2701=ORIENTED_EDGE('',*,*,#220,.F.);
#2702=EDGE_LOOP('',(#2693,#2699,#2700,#2701));
#2703=FACE_BOUND('',#2702,.T.);
#2704=ADVANCED_FACE('F2120',(#2703),#2692,.F.);
#2705=CARTESIAN_POINT('',(0.,0.,6.));
#2706=DIRECTION('',(0.,0.,-1.));
#2707=DIRECTION('',(-1.,0.,0.));
#2708=AXIS2_PLACEMENT_3D('',#2705,#2706,#2707);
#2709=CYLINDRICAL_SURFACE('',#2708,45.06);
#2710=ORIENTED_EDGE('',*,*,#2698,.F.);
#2711=ORIENTED_EDGE('',*,*,#2676,.F.);
#2712=ORIENTED_EDGE('',*,*,#2651,.F.);
#2713=ORIENTED_EDGE('',*,*,#558,.F.);
#2714=EDGE_LOOP('',(#2710,#2711,#2712,#2713));
#2715=FACE_BOUND('',#2714,.T.);
#2716=ADVANCED_FACE('F2127',(#2715),#2709,.T.);
#2717=CARTESIAN_POINT('',(-44.3789299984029,7.74681045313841,3.99999999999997));
#2718=DIRECTION('',(0.171960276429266,0.985103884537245,0.));
#2719=DIRECTION('',(0.,0.,-1.));
#2720=AXIS2_PLACEMENT_3D('',#2717,#2718,#2719);
#2721=PLANE('',#2720);
#2722=ORIENTED_EDGE('',*,*,#540,.F.);
#2723=DIRECTION('',(0.,0.,-1.));
#2724=VECTOR('',#2723,1.);
#2725=CARTESIAN_POINT('',(-44.3887810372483,7.74853005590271,6.));
#2726=LINE('',#2725,#2724);
#2727=CARTESIAN_POINT('',(-44.3887810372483,7.74853005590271,1.99999999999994));
#2728=VERTEX_POINT('',#2727);
#2729=EDGE_CURVE('E1191',#533,#2728,#2726,.T.);
#2730=ORIENTED_EDGE('',*,*,#2729,.T.);
#2731=DIRECTION('',(0.985103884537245,-0.171960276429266,0.));
#2732=VECTOR('',#2731,1.);
#2733=CARTESIAN_POINT('',(-44.3789299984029,7.74681045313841,1.99999999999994));
#2734=LINE('',#2733,#2732);
#2735=EDGE_CURVE('E1190',#2728,#231,#2734,.T.);
#2736=ORIENTED_EDGE('',*,*,#2735,.T.);
#2737=ORIENTED_EDGE('',*,*,#232,.F.);
#2738=EDGE_LOOP('',(#2722,#2730,#2736,#2737));
#2739=FACE_BOUND('',#2738,.T.);
#2740=ADVANCED_FACE('F2135',(#2739),#2721,.F.);
#2741=CARTESIAN_POINT('',(0.,0.,1.99999999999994));
#2742=DIRECTION('',(0.,0.,1.));
#2743=DIRECTION('',(1.,0.,0.));
#2744=AXIS2_PLACEMENT_3D('',#2741,#2742,#2743);
#2745=PLANE('',#2744);
#2746=ORIENTED_EDGE('',*,*,#2735,.F.);
#2747=CARTESIAN_POINT('',(0.,0.,1.99999999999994));
#2748=DIRECTION('',(0.,0.,-1.));
#2749=DIRECTION('',(-1.,0.,0.));
#2750=AXIS2_PLACEMENT_3D('',#2747,#2748,#2749);
#2751=CIRCLE('',#2750,45.06);
#2752=CARTESIAN_POINT('',(-44.3539440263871,7.94551756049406,1.99999999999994));
#2753=VERTEX_POINT('',#2752);
#2754=EDGE_CURVE('E1186',#2728,#2753,#2751,.T.);
#2755=ORIENTED_EDGE('',*,*,#2754,.T.);
#2756=DIRECTION('',(0.984330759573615,-0.176331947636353,0.));
#2757=VECTOR('',#2756,1.);
#2758=CARTESIAN_POINT('',(-44.3441007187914,7.9437542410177,1.99999999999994));
#2759=LINE('',#2758,#2757);
#2760=EDGE_CURVE('E1185',#2753,#240,#2759,.T.);
#2761=ORIENTED_EDGE('',*,*,#2760,.T.);
#2762=ORIENTED_EDGE('',*,*,#241,.F.);
#2763=EDGE_LOOP('',(#2746,#2755,#2761,#2762));
#2764=FACE_BOUND('',#2763,.T.);
#2765=ADVANCED_FACE('F2143',(#2764),#2745,.F.);
#2766=CARTESIAN_POINT('',(-44.3441007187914,7.9437542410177,3.99999999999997));
#2767=DIRECTION('',(-0.176331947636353,-0.984330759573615,0.));
#2768=DIRECTION('',(0.,0.,1.));
#2769=AXIS2_PLACEMENT_3D('',#2766,#2767,#2768);
#2770=PLANE('',#2769);
#2771=ORIENTED_EDGE('',*,*,#2760,.F.);
#2772=DIRECTION('',(0.,0.,-1.));
#2773=VECTOR('',#2772,1.);
#2774=CARTESIAN_POINT('',(-44.3539440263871,7.94551756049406,6.));
#2775=LINE('',#2774,#2773);
#2776=EDGE_CURVE('E1181',#2753,#524,#2775,.F.);
#2777=ORIENTED_EDGE('',*,*,#2776,.T.);
#2778=ORIENTED_EDGE('',*,*,#525,.T.);
#2779=ORIENTED_EDGE('',*,*,#249,.F.);
#2780=EDGE_LOOP('',(#2771,#2777,#2778,#2779));
#2781=FACE_BOUND('',#2780,.T.);
#2782=ADVANCED_FACE('F2151',(#2781),#2770,.F.);
#2783=CARTESIAN_POINT('',(0.,0.,6.));
#2784=DIRECTION('',(0.,0.,-1.));
#2785=DIRECTION('',(-1.,0.,0.));
#2786=AXIS2_PLACEMENT_3D('',#2783,#2784,#2785);
#2787=CYLINDRICAL_SURFACE('',#2786,45.06);
#2788=ORIENTED_EDGE('',*,*,#2776,.F.);
#2789=ORIENTED_EDGE('',*,*,#2754,.F.);
#2790=ORIENTED_EDGE('',*,*,#2729,.F.);
#2791=ORIENTED_EDGE('',*,*,#534,.F.);
#2792=EDGE_LOOP('',(#2788,#2789,#2790,#2791));
#2793=FACE_BOUND('',#2792,.T.);
#2794=ADVANCED_FACE('F2159',(#2793),#2787,.T.);
#2795=CARTESIAN_POINT('',(-44.0340641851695,9.51334280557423,3.99999999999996));
#2796=DIRECTION('',(0.21117298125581,0.977448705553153,0.));
#2797=DIRECTION('',(0.,0.,-1.));
#2798=AXIS2_PLACEMENT_3D('',#2795,#2796,#2797);
#2799=PLANE('',#2798);
#2800=ORIENTED_EDGE('',*,*,#516,.F.);
#2801=DIRECTION('',(0.,0.,-1.));
#2802=VECTOR('',#2801,1.);
#2803=CARTESIAN_POINT('',(-44.0438386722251,9.51545453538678,6.));
#2804=LINE('',#2803,#2802);
#2805=CARTESIAN_POINT('',(-44.0438386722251,9.51545453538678,1.99999999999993));
#2806=VERTEX_POINT('',#2805);
#2807=EDGE_CURVE('E1150',#509,#2806,#2804,.T.);
#2808=ORIENTED_EDGE('',*,*,#2807,.T.);
#2809=DIRECTION('',(0.977448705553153,-0.21117298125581,0.));
#2810=VECTOR('',#2809,1.);
#2811=CARTESIAN_POINT('',(-44.0340641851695,9.51334280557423,1.99999999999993));
#2812=LINE('',#2811,#2810);
#2813=EDGE_CURVE('E1149',#2806,#260,#2812,.T.);
#2814=ORIENTED_EDGE('',*,*,#2813,.T.);
#2815=ORIENTED_EDGE('',*,*,#261,.F.);
#2816=EDGE_LOOP('',(#2800,#2808,#2814,#2815));
#2817=FACE_BOUND('',#2816,.T.);
#2818=ADVANCED_FACE('F2167',(#2817),#2799,.F.);
#2819=CARTESIAN_POINT('',(0.,0.,1.99999999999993));
#2820=DIRECTION('',(0.,0.,1.));
#2821=DIRECTION('',(1.,0.,0.));
#2822=AXIS2_PLACEMENT_3D('',#2819,#2820,#2821);
#2823=PLANE('',#2822);
#2824=ORIENTED_EDGE('',*,*,#2813,.F.);
#2825=CARTESIAN_POINT('',(0.,0.,1.99999999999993));
#2826=DIRECTION('',(0.,0.,-1.));
#2827=DIRECTION('',(-1.,0.,0.));
#2828=AXIS2_PLACEMENT_3D('',#2825,#2826,#2827);
#2829=CIRCLE('',#2828,45.06);
#2830=CARTESIAN_POINT('',(-44.0011608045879,9.71089325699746,1.99999999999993));
#2831=VERTEX_POINT('',#2830);
#2832=EDGE_CURVE('E1145',#2806,#2831,#2829,.T.);
#2833=ORIENTED_EDGE('',*,*,#2832,.T.);
#2834=DIRECTION('',(0.976501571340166,-0.215510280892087,0.));
#2835=VECTOR('',#2834,1.);
#2836=CARTESIAN_POINT('',(-43.9913957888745,9.70873815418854,1.99999999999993));
#2837=LINE('',#2836,#2835);
#2838=EDGE_CURVE('E1144',#2831,#269,#2837,.T.);
#2839=ORIENTED_EDGE('',*,*,#2838,.T.);
#2840=ORIENTED_EDGE('',*,*,#270,.F.);
#2841=EDGE_LOOP('',(#2824,#2833,#2839,#2840));
#2842=FACE_BOUND('',#2841,.T.);
#2843=ADVANCED_FACE('F2175',(#2842),#2823,.F.);
#2844=CARTESIAN_POINT('',(-43.9913957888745,9.70873815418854,3.99999999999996));
#2845=DIRECTION('',(-0.215510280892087,-0.976501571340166,0.));
#2846=DIRECTION('',(0.,0.,1.));
#2847=AXIS2_PLACEMENT_3D('',#2844,#2845,#2846);
#2848=PLANE('',#2847);
#2849=ORIENTED_EDGE('',*,*,#2838,.F.);
#2850=DIRECTION('',(0.,0.,-1.));
#2851=VECTOR('',#2850,1.);
#2852=CARTESIAN_POINT('',(-44.0011608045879,9.71089325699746,6.));
#2853=LINE('',#2852,#2851);
#2854=EDGE_CURVE('E1140',#2831,#500,#2853,.F.);
#2855=ORIENTED_EDGE('',*,*,#2854,.T.);
#2856=ORIENTED_EDGE('',*,*,#501,.T.);
#2857=ORIENTED_EDGE('',*,*,#278,.F.);
#2858=EDGE_LOOP('',(#2849,#2855,#2856,#2857));
#2859=FACE_BOUND('',#2858,.T.);
#2860=ADVANCED_FACE('F2183',(#2859),#2848,.F.);
#2861=CARTESIAN_POINT('',(0.,0.,6.));
#2862=DIRECTION('',(0.,0.,-1.));
#2863=DIRECTION('',(-1.,0.,0.));
#2864=AXIS2_PLACEMENT_3D('',#2861,#2862,#2863);
#2865=CYLINDRICAL_SURFACE('',#2864,45.06);
#2866=ORIENTED_EDGE('',*,*,#2854,.F.);
#2867=ORIENTED_EDGE('',*,*,#2832,.F.);
#2868=ORIENTED_EDGE('',*,*,#2807,.F.);
#2869=ORIENTED_EDGE('',*,*,#510,.F.);
#2870=EDGE_LOOP('',(#2866,#2867,#2868,#2869));
#2871=FACE_BOUND('',#2870,.T.);
#2872=ADVANCED_FACE('F2191',(#2871),#2865,.T.);
#2873=CARTESIAN_POINT('',(-43.6189095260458,11.2646895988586,3.99999999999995));
#2874=DIRECTION('',(0.250048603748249,0.968233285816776,0.));
#2875=DIRECTION('',(0.,0.,-1.));
#2876=AXIS2_PLACEMENT_3D('',#2873,#2874,#2875);
#2877=PLANE('',#2876);
#2878=ORIENTED_EDGE('',*,*,#492,.F.);
#2879=DIRECTION('',(0.,0.,-1.));
#2880=VECTOR('',#2879,1.);
#2881=CARTESIAN_POINT('',(-43.6285918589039,11.2671900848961,6.));
#2882=LINE('',#2881,#2880);
#2883=CARTESIAN_POINT('',(-43.6285918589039,11.2671900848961,1.99999999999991));
#2884=VERTEX_POINT('',#2883);
#2885=EDGE_CURVE('E1108',#485,#2884,#2882,.T.);
#2886=ORIENTED_EDGE('',*,*,#2885,.T.);
#2887=DIRECTION('',(0.968233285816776,-0.250048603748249,0.));
#2888=VECTOR('',#2887,1.);
#2889=CARTESIAN_POINT('',(-43.6189095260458,11.2646895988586,1.99999999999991));
#2890=LINE('',#2889,#2888);
#2891=EDGE_CURVE('E1107',#2884,#289,#2890,.T.);
#2892=ORIENTED_EDGE('',*,*,#2891,.T.);
#2893=ORIENTED_EDGE('',*,*,#290,.F.);
#2894=EDGE_LOOP('',(#2878,#2886,#2892,#2893));
#2895=FACE_BOUND('',#2894,.T.);
#2896=ADVANCED_FACE('F2199',(#2895),#2877,.F.);
#2897=CARTESIAN_POINT('',(0.,0.,1.99999999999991));
#2898=DIRECTION('',(0.,0.,1.));
#2899=DIRECTION('',(1.,0.,0.));
#2900=AXIS2_PLACEMENT_3D('',#2897,#2898,#2899);
#2901=PLANE('',#2900);
#2902=ORIENTED_EDGE('',*,*,#2891,.F.);
#2903=CARTESIAN_POINT('',(0.,0.,1.99999999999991));
#2904=DIRECTION('',(0.,0.,-1.));
#2905=DIRECTION('',(-1.,0.,0.));
#2906=AXIS2_PLACEMENT_3D('',#2903,#2904,#2905);
#2907=CIRCLE('',#2906,45.06);
#2908=CARTESIAN_POINT('',(-43.5781412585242,11.4607680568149,1.99999999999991));
#2909=VERTEX_POINT('',#2908);
#2910=EDGE_CURVE('E1103',#2884,#2909,#2907,.T.);
#2911=ORIENTED_EDGE('',*,*,#2910,.T.);
#2912=DIRECTION('',(0.967113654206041,-0.254344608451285,0.));
#2913=VECTOR('',#2912,1.);
#2914=CARTESIAN_POINT('',(-43.5684701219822,11.4582246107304,1.99999999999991));
#2915=LINE('',#2914,#2913);
#2916=EDGE_CURVE('E1102',#2909,#298,#2915,.T.);
#2917=ORIENTED_EDGE('',*,*,#2916,.T.);
#2918=ORIENTED_EDGE('',*,*,#299,.F.);
#2919=EDGE_LOOP('',(#2902,#2911,#2917,#2918));
#2920=FACE_BOUND('',#2919,.T.);
#2921=ADVANCED_FACE('F2207',(#2920),#2901,.F.);
#2922=CARTESIAN_POINT('',(-43.5684701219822,11.4582246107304,3.99999999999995));
#2923=DIRECTION('',(-0.254344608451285,-0.967113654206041,0.));
#2924=DIRECTION('',(0.,0.,1.));
#2925=AXIS2_PLACEMENT_3D('',#2922,#2923,#2924);
#2926=PLANE('',#2925);
#2927=ORIENTED_EDGE('',*,*,#2916,.F.);
#2928=DIRECTION('',(0.,0.,-1.));
#2929=VECTOR('',#2928,1.);
#2930=CARTESIAN_POINT('',(-43.5781412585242,11.4607680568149,6.));
#2931=LINE('',#2930,#2929);
#2932=EDGE_CURVE('E1098',#2909,#476,#2931,.F.);
#2933=ORIENTED_EDGE('',*,*,#2932,.T.);
#2934=ORIENTED_EDGE('',*,*,#477,.T.);
#2935=ORIENTED_EDGE('',*,*,#307,.F.);
#2936=EDGE_LOOP('',(#2927,#2933,#2934,#2935));
#2937=FACE_BOUND('',#2936,.T.);
#2938=ADVANCED_FACE('F2215',(#2937),#2926,.F.);
#2939=CARTESIAN_POINT('',(0.,0.,6.));
#2940=DIRECTION('',(0.,0.,-1.));
#2941=DIRECTION('',(-1.,0.,0.));
#2942=AXIS2_PLACEMENT_3D('',#2939,#2940,#2941);
#2943=CYLINDRICAL_SURFACE('',#2942,45.06);
#2944=ORIENTED_EDGE('',*,*,#2932,.F.);
#2945=ORIENTED_EDGE('',*,*,#2910,.F.);
#2946=ORIENTED_EDGE('',*,*,#2885,.F.);
#2947=ORIENTED_EDGE('',*,*,#486,.F.);
#2948=EDGE_LOOP('',(#2944,#2945,#2946,#2947));
#2949=FACE_BOUND('',#2948,.T.);
#2950=ADVANCED_FACE('F2223',(#2949),#2943,.T.);
#2951=CARTESIAN_POINT('',(-44.8557062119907,4.1794880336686,3.99999999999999));
#2952=DIRECTION('',(0.0927744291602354,0.995687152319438,0.));
#2953=DIRECTION('',(0.,0.,-1.));
#2954=AXIS2_PLACEMENT_3D('',#2951,#2952,#2953);
#2955=PLANE('',#2954);
#2956=ORIENTED_EDGE('',*,*,#588,.F.);
#2957=DIRECTION('',(0.,0.,-1.));
#2958=VECTOR('',#2957,1.);
#2959=CARTESIAN_POINT('',(-44.8656630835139,4.18041577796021,6.));
#2960=LINE('',#2959,#2958);
#2961=CARTESIAN_POINT('',(-44.8656630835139,4.18041577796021,1.99999999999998));
#2962=VERTEX_POINT('',#2961);
#2963=EDGE_CURVE('E859',#581,#2962,#2960,.T.);
#2964=ORIENTED_EDGE('',*,*,#2963,.T.);
#2965=DIRECTION('',(0.995687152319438,-0.0927744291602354,0.));
#2966=VECTOR('',#2965,1.);
#2967=CARTESIAN_POINT('',(-44.8557062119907,4.1794880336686,1.99999999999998));
#2968=LINE('',#2967,#2966);
#2969=EDGE_CURVE('E858',#2962,#173,#2968,.T.);
#2970=ORIENTED_EDGE('',*,*,#2969,.T.);
#2971=ORIENTED_EDGE('',*,*,#174,.F.);
#2972=EDGE_LOOP('',(#2956,#2964,#2970,#2971));
#2973=FACE_BOUND('',#2972,.T.);
#2974=ADVANCED_FACE('F2054',(#2973),#2955,.F.);
#2975=CARTESIAN_POINT('',(0.,0.,1.99999999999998));
#2976=DIRECTION('',(0.,0.,1.));
#2977=DIRECTION('',(1.,0.,0.));
#2978=AXIS2_PLACEMENT_3D('',#2975,#2976,#2977);
#2979=PLANE('',#2978);
#2980=ORIENTED_EDGE('',*,*,#2969,.F.);
#2981=CARTESIAN_POINT('',(0.,0.,1.99999999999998));
#2982=DIRECTION('',(0.,0.,-1.));
#2983=DIRECTION('',(-1.,0.,0.));
#2984=AXIS2_PLACEMENT_3D('',#2981,#2982,#2983);
#2985=CIRCLE('',#2984,45.06);
#2986=CARTESIAN_POINT('',(-44.8466620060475,4.37955556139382,1.99999999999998));
#2987=VERTEX_POINT('',#2986);
#2988=EDGE_CURVE('E854',#2962,#2987,#2985,.T.);
#2989=ORIENTED_EDGE('',*,*,#2988,.T.);
#2990=DIRECTION('',(0.995265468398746,-0.0971938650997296,0.));
#2991=VECTOR('',#2990,1.);
#2992=CARTESIAN_POINT('',(-44.8367093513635,4.37858362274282,1.99999999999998));
#2993=LINE('',#2992,#2991);
#2994=EDGE_CURVE('E853',#2987,#182,#2993,.T.);
#2995=ORIENTED_EDGE('',*,*,#2994,.T.);
#2996=ORIENTED_EDGE('',*,*,#183,.F.);
#2997=EDGE_LOOP('',(#2980,#2989,#2995,#2996));
#2998=FACE_BOUND('',#2997,.T.);
#2999=ADVANCED_FACE('F2060',(#2998),#2979,.F.);
#3000=CARTESIAN_POINT('',(-44.8367093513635,4.37858362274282,3.99999999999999));
#3001=DIRECTION('',(-0.0971938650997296,-0.995265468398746,0.));
#3002=DIRECTION('',(0.,0.,1.));
#3003=AXIS2_PLACEMENT_3D('',#3000,#3001,#3002);
#3004=PLANE('',#3003);
#3005=ORIENTED_EDGE('',*,*,#2994,.F.);
#3006=DIRECTION('',(0.,0.,-1.));
#3007=VECTOR('',#3006,1.);
#3008=CARTESIAN_POINT('',(-44.8466620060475,4.37955556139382,6.));
#3009=LINE('',#3008,#3007);
#3010=EDGE_CURVE('E849',#2987,#572,#3009,.F.);
#3011=ORIENTED_EDGE('',*,*,#3010,.T.);
#3012=ORIENTED_EDGE('',*,*,#573,.T.);
#3013=ORIENTED_EDGE('',*,*,#191,.F.);
#3014=EDGE_LOOP('',(#3005,#3011,#3012,#3013));
#3015=FACE_BOUND('',#3014,.T.);
#3016=ADVANCED_FACE('F2063',(#3015),#3004,.F.);
#3017=CARTESIAN_POINT('',(0.,0.,6.));
#3018=DIRECTION('',(0.,0.,-1.));
#3019=DIRECTION('',(-1.,0.,0.));
#3020=AXIS2_PLACEMENT_3D('',#3017,#3018,#3019);
#3021=CYLINDRICAL_SURFACE('',#3020,45.06);
#3022=ORIENTED_EDGE('',*,*,#3010,.F.);
#3023=ORIENTED_EDGE('',*,*,#2988,.F.);
#3024=ORIENTED_EDGE('',*,*,#2963,.F.);
#3025=ORIENTED_EDGE('',*,*,#582,.F.);
#3026=EDGE_LOOP('',(#3022,#3023,#3024,#3025));
#3027=FACE_BOUND('',#3026,.T.);
#3028=ADVANCED_FACE('F2058',(#3027),#3021,.T.);
#3029=CARTESIAN_POINT('',(-44.9868555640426,2.38439226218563,4.));
#3030=DIRECTION('',(0.0529276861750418,0.998598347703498,0.));
#3031=DIRECTION('',(0.,0.,-1.));
#3032=AXIS2_PLACEMENT_3D('',#3029,#3030,#3031);
#3033=PLANE('',#3032);
#3034=ORIENTED_EDGE('',*,*,#612,.F.);
#3035=DIRECTION('',(0.,0.,-1.));
#3036=VECTOR('',#3035,1.);
#3037=CARTESIAN_POINT('',(-44.9968415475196,2.38492153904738,6.));
#3038=LINE('',#3037,#3036);
#3039=CARTESIAN_POINT('',(-44.9968415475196,2.38492153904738,2.));
#3040=VERTEX_POINT('',#3039);
#3041=EDGE_CURVE('E819',#605,#3040,#3038,.T.);
#3042=ORIENTED_EDGE('',*,*,#3041,.T.);
#3043=DIRECTION('',(0.998598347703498,-0.0529276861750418,0.));
#3044=VECTOR('',#3043,1.);
#3045=CARTESIAN_POINT('',(-44.9868555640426,2.38439226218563,2.));
#3046=LINE('',#3045,#3044);
#3047=EDGE_CURVE('E818',#3040,#144,#3046,.T.);
#3048=ORIENTED_EDGE('',*,*,#3047,.T.);
#3049=ORIENTED_EDGE('',*,*,#145,.F.);
#3050=EDGE_LOOP('',(#3034,#3042,#3048,#3049));
#3051=FACE_BOUND('',#3050,.T.);
#3052=ADVANCED_FACE('F2070',(#3051),#3033,.F.);
#3053=CARTESIAN_POINT('',(0.,0.,2.));
#3054=DIRECTION('',(0.,0.,1.));
#3055=DIRECTION('',(1.,0.,0.));
#3056=AXIS2_PLACEMENT_3D('',#3053,#3054,#3055);
#3057=PLANE('',#3056);
#3058=ORIENTED_EDGE('',*,*,#3047,.F.);
#3059=CARTESIAN_POINT('',(0.,0.,2.));
#3060=DIRECTION('',(0.,0.,-1.));
#3061=DIRECTION('',(-1.,0.,0.));
#3062=AXIS2_PLACEMENT_3D('',#3059,#3060,#3061);
#3063=CIRCLE('',#3062,45.06);
#3064=CARTESIAN_POINT('',(-44.9858102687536,2.58466138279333,2.));
#3065=VERTEX_POINT('',#3064);
#3066=EDGE_CURVE('E814',#3040,#3065,#3063,.T.);
#3067=ORIENTED_EDGE('',*,*,#3066,.T.);
#3068=DIRECTION('',(0.998353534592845,-0.0573604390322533,0.));
#3069=VECTOR('',#3068,1.);
#3070=CARTESIAN_POINT('',(-44.9758267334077,2.58408777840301,2.));
#3071=LINE('',#3070,#3069);
#3072=EDGE_CURVE('E813',#3065,#153,#3071,.T.);
#3073=ORIENTED_EDGE('',*,*,#3072,.T.);
#3074=ORIENTED_EDGE('',*,*,#154,.F.);
#3075=EDGE_LOOP('',(#3058,#3067,#3073,#3074));
#3076=FACE_BOUND('',#3075,.T.);
#3077=ADVANCED_FACE('F2045',(#3076),#3057,.F.);
#3078=CARTESIAN_POINT('',(-44.9758267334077,2.58408777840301,4.));
#3079=DIRECTION('',(-0.0573604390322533,-0.998353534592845,0.));
#3080=DIRECTION('',(0.,0.,1.));
#3081=AXIS2_PLACEMENT_3D('',#3078,#3079,#3080);
#3082=PLANE('',#3081);
#3083=ORIENTED_EDGE('',*,*,#3072,.F.);
#3084=DIRECTION('',(0.,0.,-1.));
#3085=VECTOR('',#3084,1.);
#3086=CARTESIAN_POINT('',(-44.9858102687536,2.58466138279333,6.));
#3087=LINE('',#3086,#3085);
#3088=EDGE_CURVE('E700',#3065,#596,#3087,.F.);
#3089=ORIENTED_EDGE('',*,*,#3088,.T.);
#3090=ORIENTED_EDGE('',*,*,#597,.T.);
#3091=ORIENTED_EDGE('',*,*,#162,.F.);
#3092=EDGE_LOOP('',(#3083,#3089,#3090,#3091));
#3093=FACE_BOUND('',#3092,.T.);
#3094=ADVANCED_FACE('F2048',(#3093),#3082,.F.);
#3095=CARTESIAN_POINT('',(0.,0.,6.));
#3096=DIRECTION('',(0.,0.,-1.));
#3097=DIRECTION('',(-1.,0.,0.));
#3098=AXIS2_PLACEMENT_3D('',#3095,#3096,#3097);
#3099=CYLINDRICAL_SURFACE('',#3098,45.06);
#3100=ORIENTED_EDGE('',*,*,#3088,.F.);
#3101=ORIENTED_EDGE('',*,*,#3066,.F.);
#3102=ORIENTED_EDGE('',*,*,#3041,.F.);
#3103=ORIENTED_EDGE('',*,*,#606,.F.);
#3104=EDGE_LOOP('',(#3100,#3101,#3102,#3103));
#3105=FACE_BOUND('',#3104,.T.);
#3106=ADVANCED_FACE('F2082',(#3105),#3099,.T.);
#3107=CLOSED_SHELL('',(#464,#640,#917,#939,#1295,#1317,#1478,#1522,#1545,#1567,#1589,#1601,
#1613,#1625,#1637,#1649,#1661,#1673,#1685,#1713,#1735,#1746,#1778,#1802,#1827,#1844,#1856,#1888,
#1912,#1937,#1961,#1986,#2010,#2035,#2059,#2084,#2108,#2133,#2150,#2170,#2202,#2219,#2236,#2248,
#2280,#2297,#2314,#2326,#2358,#2375,#2392,#2404,#2436,#2453,#2470,#2482,#2514,#2531,#2548,#2560,
#2592,#2609,#2626,#2638,#2662,#2687,#2704,#2716,#2740,#2765,#2782,#2794,#2818,#2843,#2860,#2872,
#2896,#2921,#2938,#2950,#2974,#2999,#3016,#3028,#3052,#3077,#3094,#3106));
#3108=MANIFOLD_SOLID_BREP('B2',#3107);
#3109=ADVANCED_BREP_SHAPE_REPRESENTATION('',(#18,#3108),#14);
#3110=SHAPE_DEFINITION_REPRESENTATION(#9,#3109);
ENDSEC;
END-ISO-10303-21;
